# Generated deterministically by seda-macro-lef-normalizer-v1; recipe orfs-ng45-fakeram-metal3-coupledl2-pg-v1.
VERSION 5.8 ;
BUSBITCHARS "[]" ;
DIVIDERCHAR "/" ;

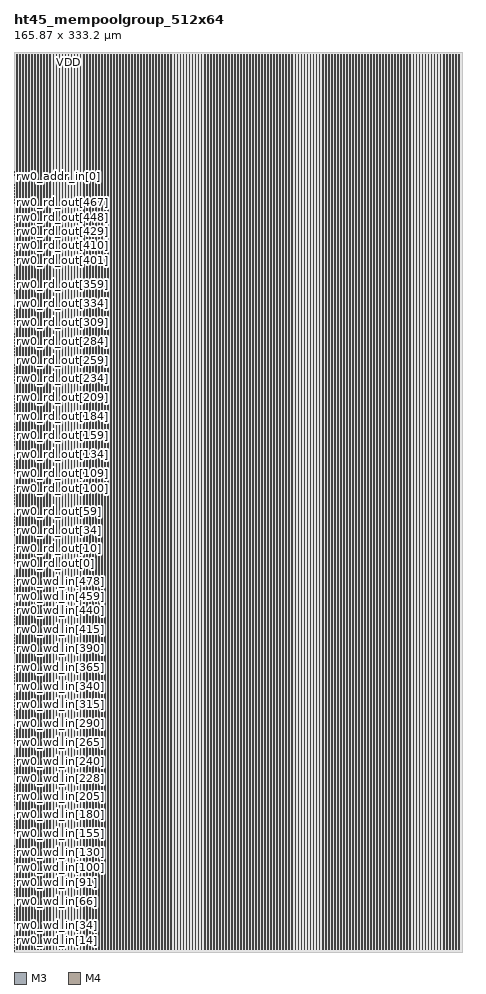
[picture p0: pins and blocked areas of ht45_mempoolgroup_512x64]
MACRO ht45_mempoolgroup_512x64
  FOREIGN ht45_mempoolgroup_512x64 0 0 ;
  CLASS BLOCK ;
  ORIGIN 0 0 ;
  SIZE 165.87 BY 333.2 ;
  SYMMETRY X Y R90 ;
  PIN rw0_wmask_in[0]
    DIRECTION INPUT ;
    USE SIGNAL ;
    SHAPE ABUTMENT ;
    PORT
      LAYER M3 ;
      RECT 0 0.035 0.07 0.105 ;
    END
  END rw0_wmask_in[0]
  PIN rw0_wd_in[0]
    DIRECTION INPUT ;
    USE SIGNAL ;
    SHAPE ABUTMENT ;
    PORT
      LAYER M3 ;
      RECT 0 0.315 0.07 0.385 ;
    END
  END rw0_wd_in[0]
  PIN rw0_wd_in[1]
    DIRECTION INPUT ;
    USE SIGNAL ;
    SHAPE ABUTMENT ;
    PORT
      LAYER M3 ;
      RECT 0 0.595 0.07 0.665 ;
    END
  END rw0_wd_in[1]
  PIN rw0_wd_in[2]
    DIRECTION INPUT ;
    USE SIGNAL ;
    SHAPE ABUTMENT ;
    PORT
      LAYER M3 ;
      RECT 0 0.875 0.07 0.945 ;
    END
  END rw0_wd_in[2]
  PIN rw0_wd_in[3]
    DIRECTION INPUT ;
    USE SIGNAL ;
    SHAPE ABUTMENT ;
    PORT
      LAYER M3 ;
      RECT 0 1.155 0.07 1.225 ;
    END
  END rw0_wd_in[3]
  PIN rw0_wd_in[4]
    DIRECTION INPUT ;
    USE SIGNAL ;
    SHAPE ABUTMENT ;
    PORT
      LAYER M3 ;
      RECT 0 1.435 0.07 1.505 ;
    END
  END rw0_wd_in[4]
  PIN rw0_wd_in[5]
    DIRECTION INPUT ;
    USE SIGNAL ;
    SHAPE ABUTMENT ;
    PORT
      LAYER M3 ;
      RECT 0 1.715 0.07 1.785 ;
    END
  END rw0_wd_in[5]
  PIN rw0_wd_in[6]
    DIRECTION INPUT ;
    USE SIGNAL ;
    SHAPE ABUTMENT ;
    PORT
      LAYER M3 ;
      RECT 0 1.995 0.07 2.065 ;
    END
  END rw0_wd_in[6]
  PIN rw0_wd_in[7]
    DIRECTION INPUT ;
    USE SIGNAL ;
    SHAPE ABUTMENT ;
    PORT
      LAYER M3 ;
      RECT 0 2.275 0.07 2.345 ;
    END
  END rw0_wd_in[7]
  PIN rw0_wd_in[8]
    DIRECTION INPUT ;
    USE SIGNAL ;
    SHAPE ABUTMENT ;
    PORT
      LAYER M3 ;
      RECT 0 2.555 0.07 2.625 ;
    END
  END rw0_wd_in[8]
  PIN rw0_wd_in[9]
    DIRECTION INPUT ;
    USE SIGNAL ;
    SHAPE ABUTMENT ;
    PORT
      LAYER M3 ;
      RECT 0 2.835 0.07 2.905 ;
    END
  END rw0_wd_in[9]
  PIN rw0_wd_in[10]
    DIRECTION INPUT ;
    USE SIGNAL ;
    SHAPE ABUTMENT ;
    PORT
      LAYER M3 ;
      RECT 0 3.115 0.07 3.185 ;
    END
  END rw0_wd_in[10]
  PIN rw0_wd_in[11]
    DIRECTION INPUT ;
    USE SIGNAL ;
    SHAPE ABUTMENT ;
    PORT
      LAYER M3 ;
      RECT 0 3.395 0.07 3.465 ;
    END
  END rw0_wd_in[11]
  PIN rw0_wd_in[12]
    DIRECTION INPUT ;
    USE SIGNAL ;
    SHAPE ABUTMENT ;
    PORT
      LAYER M3 ;
      RECT 0 3.675 0.07 3.745 ;
    END
  END rw0_wd_in[12]
  PIN rw0_wd_in[13]
    DIRECTION INPUT ;
    USE SIGNAL ;
    SHAPE ABUTMENT ;
    PORT
      LAYER M3 ;
      RECT 0 3.955 0.07 4.025 ;
    END
  END rw0_wd_in[13]
  PIN rw0_wd_in[14]
    DIRECTION INPUT ;
    USE SIGNAL ;
    SHAPE ABUTMENT ;
    PORT
      LAYER M3 ;
      RECT 0 4.235 0.07 4.305 ;
    END
  END rw0_wd_in[14]
  PIN rw0_wd_in[15]
    DIRECTION INPUT ;
    USE SIGNAL ;
    SHAPE ABUTMENT ;
    PORT
      LAYER M3 ;
      RECT 0 4.515 0.07 4.585 ;
    END
  END rw0_wd_in[15]
  PIN rw0_wd_in[16]
    DIRECTION INPUT ;
    USE SIGNAL ;
    SHAPE ABUTMENT ;
    PORT
      LAYER M3 ;
      RECT 0 4.795 0.07 4.865 ;
    END
  END rw0_wd_in[16]
  PIN rw0_wd_in[17]
    DIRECTION INPUT ;
    USE SIGNAL ;
    SHAPE ABUTMENT ;
    PORT
      LAYER M3 ;
      RECT 0 5.075 0.07 5.145 ;
    END
  END rw0_wd_in[17]
  PIN rw0_wd_in[18]
    DIRECTION INPUT ;
    USE SIGNAL ;
    SHAPE ABUTMENT ;
    PORT
      LAYER M3 ;
      RECT 0 5.355 0.07 5.425 ;
    END
  END rw0_wd_in[18]
  PIN rw0_wd_in[19]
    DIRECTION INPUT ;
    USE SIGNAL ;
    SHAPE ABUTMENT ;
    PORT
      LAYER M3 ;
      RECT 0 5.635 0.07 5.705 ;
    END
  END rw0_wd_in[19]
  PIN rw0_wd_in[20]
    DIRECTION INPUT ;
    USE SIGNAL ;
    SHAPE ABUTMENT ;
    PORT
      LAYER M3 ;
      RECT 0 5.915 0.07 5.985 ;
    END
  END rw0_wd_in[20]
  PIN rw0_wd_in[21]
    DIRECTION INPUT ;
    USE SIGNAL ;
    SHAPE ABUTMENT ;
    PORT
      LAYER M3 ;
      RECT 0 6.195 0.07 6.265 ;
    END
  END rw0_wd_in[21]
  PIN rw0_wd_in[22]
    DIRECTION INPUT ;
    USE SIGNAL ;
    SHAPE ABUTMENT ;
    PORT
      LAYER M3 ;
      RECT 0 6.475 0.07 6.545 ;
    END
  END rw0_wd_in[22]
  PIN rw0_wd_in[23]
    DIRECTION INPUT ;
    USE SIGNAL ;
    SHAPE ABUTMENT ;
    PORT
      LAYER M3 ;
      RECT 0 6.755 0.07 6.825 ;
    END
  END rw0_wd_in[23]
  PIN rw0_wd_in[24]
    DIRECTION INPUT ;
    USE SIGNAL ;
    SHAPE ABUTMENT ;
    PORT
      LAYER M3 ;
      RECT 0 7.035 0.07 7.105 ;
    END
  END rw0_wd_in[24]
  PIN rw0_wd_in[25]
    DIRECTION INPUT ;
    USE SIGNAL ;
    SHAPE ABUTMENT ;
    PORT
      LAYER M3 ;
      RECT 0 7.315 0.07 7.385 ;
    END
  END rw0_wd_in[25]
  PIN rw0_wd_in[26]
    DIRECTION INPUT ;
    USE SIGNAL ;
    SHAPE ABUTMENT ;
    PORT
      LAYER M3 ;
      RECT 0 7.595 0.07 7.665 ;
    END
  END rw0_wd_in[26]
  PIN rw0_wd_in[27]
    DIRECTION INPUT ;
    USE SIGNAL ;
    SHAPE ABUTMENT ;
    PORT
      LAYER M3 ;
      RECT 0 7.875 0.07 7.945 ;
    END
  END rw0_wd_in[27]
  PIN rw0_wd_in[28]
    DIRECTION INPUT ;
    USE SIGNAL ;
    SHAPE ABUTMENT ;
    PORT
      LAYER M3 ;
      RECT 0 8.155 0.07 8.225 ;
    END
  END rw0_wd_in[28]
  PIN rw0_wd_in[29]
    DIRECTION INPUT ;
    USE SIGNAL ;
    SHAPE ABUTMENT ;
    PORT
      LAYER M3 ;
      RECT 0 8.435 0.07 8.505 ;
    END
  END rw0_wd_in[29]
  PIN rw0_wd_in[30]
    DIRECTION INPUT ;
    USE SIGNAL ;
    SHAPE ABUTMENT ;
    PORT
      LAYER M3 ;
      RECT 0 8.715 0.07 8.785 ;
    END
  END rw0_wd_in[30]
  PIN rw0_wd_in[31]
    DIRECTION INPUT ;
    USE SIGNAL ;
    SHAPE ABUTMENT ;
    PORT
      LAYER M3 ;
      RECT 0 8.995 0.07 9.065 ;
    END
  END rw0_wd_in[31]
  PIN rw0_wd_in[32]
    DIRECTION INPUT ;
    USE SIGNAL ;
    SHAPE ABUTMENT ;
    PORT
      LAYER M3 ;
      RECT 0 9.275 0.07 9.345 ;
    END
  END rw0_wd_in[32]
  PIN rw0_wd_in[33]
    DIRECTION INPUT ;
    USE SIGNAL ;
    SHAPE ABUTMENT ;
    PORT
      LAYER M3 ;
      RECT 0 9.555 0.07 9.625 ;
    END
  END rw0_wd_in[33]
  PIN rw0_wd_in[34]
    DIRECTION INPUT ;
    USE SIGNAL ;
    SHAPE ABUTMENT ;
    PORT
      LAYER M3 ;
      RECT 0 9.835 0.07 9.905 ;
    END
  END rw0_wd_in[34]
  PIN rw0_wd_in[35]
    DIRECTION INPUT ;
    USE SIGNAL ;
    SHAPE ABUTMENT ;
    PORT
      LAYER M3 ;
      RECT 0 10.115 0.07 10.185 ;
    END
  END rw0_wd_in[35]
  PIN rw0_wd_in[36]
    DIRECTION INPUT ;
    USE SIGNAL ;
    SHAPE ABUTMENT ;
    PORT
      LAYER M3 ;
      RECT 0 10.395 0.07 10.465 ;
    END
  END rw0_wd_in[36]
  PIN rw0_wd_in[37]
    DIRECTION INPUT ;
    USE SIGNAL ;
    SHAPE ABUTMENT ;
    PORT
      LAYER M3 ;
      RECT 0 10.675 0.07 10.745 ;
    END
  END rw0_wd_in[37]
  PIN rw0_wd_in[38]
    DIRECTION INPUT ;
    USE SIGNAL ;
    SHAPE ABUTMENT ;
    PORT
      LAYER M3 ;
      RECT 0 10.955 0.07 11.025 ;
    END
  END rw0_wd_in[38]
  PIN rw0_wd_in[39]
    DIRECTION INPUT ;
    USE SIGNAL ;
    SHAPE ABUTMENT ;
    PORT
      LAYER M3 ;
      RECT 0 11.235 0.07 11.305 ;
    END
  END rw0_wd_in[39]
  PIN rw0_wd_in[40]
    DIRECTION INPUT ;
    USE SIGNAL ;
    SHAPE ABUTMENT ;
    PORT
      LAYER M3 ;
      RECT 0 11.515 0.07 11.585 ;
    END
  END rw0_wd_in[40]
  PIN rw0_wd_in[41]
    DIRECTION INPUT ;
    USE SIGNAL ;
    SHAPE ABUTMENT ;
    PORT
      LAYER M3 ;
      RECT 0 11.795 0.07 11.865 ;
    END
  END rw0_wd_in[41]
  PIN rw0_wd_in[42]
    DIRECTION INPUT ;
    USE SIGNAL ;
    SHAPE ABUTMENT ;
    PORT
      LAYER M3 ;
      RECT 0 12.075 0.07 12.145 ;
    END
  END rw0_wd_in[42]
  PIN rw0_wd_in[43]
    DIRECTION INPUT ;
    USE SIGNAL ;
    SHAPE ABUTMENT ;
    PORT
      LAYER M3 ;
      RECT 0 12.355 0.07 12.425 ;
    END
  END rw0_wd_in[43]
  PIN rw0_wd_in[44]
    DIRECTION INPUT ;
    USE SIGNAL ;
    SHAPE ABUTMENT ;
    PORT
      LAYER M3 ;
      RECT 0 12.635 0.07 12.705 ;
    END
  END rw0_wd_in[44]
  PIN rw0_wd_in[45]
    DIRECTION INPUT ;
    USE SIGNAL ;
    SHAPE ABUTMENT ;
    PORT
      LAYER M3 ;
      RECT 0 12.915 0.07 12.985 ;
    END
  END rw0_wd_in[45]
  PIN rw0_wd_in[46]
    DIRECTION INPUT ;
    USE SIGNAL ;
    SHAPE ABUTMENT ;
    PORT
      LAYER M3 ;
      RECT 0 13.195 0.07 13.265 ;
    END
  END rw0_wd_in[46]
  PIN rw0_wd_in[47]
    DIRECTION INPUT ;
    USE SIGNAL ;
    SHAPE ABUTMENT ;
    PORT
      LAYER M3 ;
      RECT 0 13.475 0.07 13.545 ;
    END
  END rw0_wd_in[47]
  PIN rw0_wd_in[48]
    DIRECTION INPUT ;
    USE SIGNAL ;
    SHAPE ABUTMENT ;
    PORT
      LAYER M3 ;
      RECT 0 13.755 0.07 13.825 ;
    END
  END rw0_wd_in[48]
  PIN rw0_wd_in[49]
    DIRECTION INPUT ;
    USE SIGNAL ;
    SHAPE ABUTMENT ;
    PORT
      LAYER M3 ;
      RECT 0 14.035 0.07 14.105 ;
    END
  END rw0_wd_in[49]
  PIN rw0_wd_in[50]
    DIRECTION INPUT ;
    USE SIGNAL ;
    SHAPE ABUTMENT ;
    PORT
      LAYER M3 ;
      RECT 0 14.315 0.07 14.385 ;
    END
  END rw0_wd_in[50]
  PIN rw0_wd_in[51]
    DIRECTION INPUT ;
    USE SIGNAL ;
    SHAPE ABUTMENT ;
    PORT
      LAYER M3 ;
      RECT 0 14.595 0.07 14.665 ;
    END
  END rw0_wd_in[51]
  PIN rw0_wd_in[52]
    DIRECTION INPUT ;
    USE SIGNAL ;
    SHAPE ABUTMENT ;
    PORT
      LAYER M3 ;
      RECT 0 14.875 0.07 14.945 ;
    END
  END rw0_wd_in[52]
  PIN rw0_wd_in[53]
    DIRECTION INPUT ;
    USE SIGNAL ;
    SHAPE ABUTMENT ;
    PORT
      LAYER M3 ;
      RECT 0 15.155 0.07 15.225 ;
    END
  END rw0_wd_in[53]
  PIN rw0_wd_in[54]
    DIRECTION INPUT ;
    USE SIGNAL ;
    SHAPE ABUTMENT ;
    PORT
      LAYER M3 ;
      RECT 0 15.435 0.07 15.505 ;
    END
  END rw0_wd_in[54]
  PIN rw0_wd_in[55]
    DIRECTION INPUT ;
    USE SIGNAL ;
    SHAPE ABUTMENT ;
    PORT
      LAYER M3 ;
      RECT 0 15.715 0.07 15.785 ;
    END
  END rw0_wd_in[55]
  PIN rw0_wd_in[56]
    DIRECTION INPUT ;
    USE SIGNAL ;
    SHAPE ABUTMENT ;
    PORT
      LAYER M3 ;
      RECT 0 15.995 0.07 16.065 ;
    END
  END rw0_wd_in[56]
  PIN rw0_wd_in[57]
    DIRECTION INPUT ;
    USE SIGNAL ;
    SHAPE ABUTMENT ;
    PORT
      LAYER M3 ;
      RECT 0 16.275 0.07 16.345 ;
    END
  END rw0_wd_in[57]
  PIN rw0_wd_in[58]
    DIRECTION INPUT ;
    USE SIGNAL ;
    SHAPE ABUTMENT ;
    PORT
      LAYER M3 ;
      RECT 0 16.555 0.07 16.625 ;
    END
  END rw0_wd_in[58]
  PIN rw0_wd_in[59]
    DIRECTION INPUT ;
    USE SIGNAL ;
    SHAPE ABUTMENT ;
    PORT
      LAYER M3 ;
      RECT 0 16.835 0.07 16.905 ;
    END
  END rw0_wd_in[59]
  PIN rw0_wd_in[60]
    DIRECTION INPUT ;
    USE SIGNAL ;
    SHAPE ABUTMENT ;
    PORT
      LAYER M3 ;
      RECT 0 17.115 0.07 17.185 ;
    END
  END rw0_wd_in[60]
  PIN rw0_wd_in[61]
    DIRECTION INPUT ;
    USE SIGNAL ;
    SHAPE ABUTMENT ;
    PORT
      LAYER M3 ;
      RECT 0 17.395 0.07 17.465 ;
    END
  END rw0_wd_in[61]
  PIN rw0_wd_in[62]
    DIRECTION INPUT ;
    USE SIGNAL ;
    SHAPE ABUTMENT ;
    PORT
      LAYER M3 ;
      RECT 0 17.675 0.07 17.745 ;
    END
  END rw0_wd_in[62]
  PIN rw0_wd_in[63]
    DIRECTION INPUT ;
    USE SIGNAL ;
    SHAPE ABUTMENT ;
    PORT
      LAYER M3 ;
      RECT 0 17.955 0.07 18.025 ;
    END
  END rw0_wd_in[63]
  PIN rw0_wd_in[64]
    DIRECTION INPUT ;
    USE SIGNAL ;
    SHAPE ABUTMENT ;
    PORT
      LAYER M3 ;
      RECT 0 18.235 0.07 18.305 ;
    END
  END rw0_wd_in[64]
  PIN rw0_wd_in[65]
    DIRECTION INPUT ;
    USE SIGNAL ;
    SHAPE ABUTMENT ;
    PORT
      LAYER M3 ;
      RECT 0 18.515 0.07 18.585 ;
    END
  END rw0_wd_in[65]
  PIN rw0_wd_in[66]
    DIRECTION INPUT ;
    USE SIGNAL ;
    SHAPE ABUTMENT ;
    PORT
      LAYER M3 ;
      RECT 0 18.795 0.07 18.865 ;
    END
  END rw0_wd_in[66]
  PIN rw0_wd_in[67]
    DIRECTION INPUT ;
    USE SIGNAL ;
    SHAPE ABUTMENT ;
    PORT
      LAYER M3 ;
      RECT 0 19.075 0.07 19.145 ;
    END
  END rw0_wd_in[67]
  PIN rw0_wd_in[68]
    DIRECTION INPUT ;
    USE SIGNAL ;
    SHAPE ABUTMENT ;
    PORT
      LAYER M3 ;
      RECT 0 19.355 0.07 19.425 ;
    END
  END rw0_wd_in[68]
  PIN rw0_wd_in[69]
    DIRECTION INPUT ;
    USE SIGNAL ;
    SHAPE ABUTMENT ;
    PORT
      LAYER M3 ;
      RECT 0 19.635 0.07 19.705 ;
    END
  END rw0_wd_in[69]
  PIN rw0_wd_in[70]
    DIRECTION INPUT ;
    USE SIGNAL ;
    SHAPE ABUTMENT ;
    PORT
      LAYER M3 ;
      RECT 0 19.915 0.07 19.985 ;
    END
  END rw0_wd_in[70]
  PIN rw0_wd_in[71]
    DIRECTION INPUT ;
    USE SIGNAL ;
    SHAPE ABUTMENT ;
    PORT
      LAYER M3 ;
      RECT 0 20.195 0.07 20.265 ;
    END
  END rw0_wd_in[71]
  PIN rw0_wd_in[72]
    DIRECTION INPUT ;
    USE SIGNAL ;
    SHAPE ABUTMENT ;
    PORT
      LAYER M3 ;
      RECT 0 20.475 0.07 20.545 ;
    END
  END rw0_wd_in[72]
  PIN rw0_wd_in[73]
    DIRECTION INPUT ;
    USE SIGNAL ;
    SHAPE ABUTMENT ;
    PORT
      LAYER M3 ;
      RECT 0 20.755 0.07 20.825 ;
    END
  END rw0_wd_in[73]
  PIN rw0_wd_in[74]
    DIRECTION INPUT ;
    USE SIGNAL ;
    SHAPE ABUTMENT ;
    PORT
      LAYER M3 ;
      RECT 0 21.035 0.07 21.105 ;
    END
  END rw0_wd_in[74]
  PIN rw0_wd_in[75]
    DIRECTION INPUT ;
    USE SIGNAL ;
    SHAPE ABUTMENT ;
    PORT
      LAYER M3 ;
      RECT 0 21.315 0.07 21.385 ;
    END
  END rw0_wd_in[75]
  PIN rw0_wd_in[76]
    DIRECTION INPUT ;
    USE SIGNAL ;
    SHAPE ABUTMENT ;
    PORT
      LAYER M3 ;
      RECT 0 21.595 0.07 21.665 ;
    END
  END rw0_wd_in[76]
  PIN rw0_wd_in[77]
    DIRECTION INPUT ;
    USE SIGNAL ;
    SHAPE ABUTMENT ;
    PORT
      LAYER M3 ;
      RECT 0 21.875 0.07 21.945 ;
    END
  END rw0_wd_in[77]
  PIN rw0_wd_in[78]
    DIRECTION INPUT ;
    USE SIGNAL ;
    SHAPE ABUTMENT ;
    PORT
      LAYER M3 ;
      RECT 0 22.155 0.07 22.225 ;
    END
  END rw0_wd_in[78]
  PIN rw0_wd_in[79]
    DIRECTION INPUT ;
    USE SIGNAL ;
    SHAPE ABUTMENT ;
    PORT
      LAYER M3 ;
      RECT 0 22.435 0.07 22.505 ;
    END
  END rw0_wd_in[79]
  PIN rw0_wd_in[80]
    DIRECTION INPUT ;
    USE SIGNAL ;
    SHAPE ABUTMENT ;
    PORT
      LAYER M3 ;
      RECT 0 22.715 0.07 22.785 ;
    END
  END rw0_wd_in[80]
  PIN rw0_wd_in[81]
    DIRECTION INPUT ;
    USE SIGNAL ;
    SHAPE ABUTMENT ;
    PORT
      LAYER M3 ;
      RECT 0 22.995 0.07 23.065 ;
    END
  END rw0_wd_in[81]
  PIN rw0_wd_in[82]
    DIRECTION INPUT ;
    USE SIGNAL ;
    SHAPE ABUTMENT ;
    PORT
      LAYER M3 ;
      RECT 0 23.275 0.07 23.345 ;
    END
  END rw0_wd_in[82]
  PIN rw0_wd_in[83]
    DIRECTION INPUT ;
    USE SIGNAL ;
    SHAPE ABUTMENT ;
    PORT
      LAYER M3 ;
      RECT 0 23.555 0.07 23.625 ;
    END
  END rw0_wd_in[83]
  PIN rw0_wd_in[84]
    DIRECTION INPUT ;
    USE SIGNAL ;
    SHAPE ABUTMENT ;
    PORT
      LAYER M3 ;
      RECT 0 23.835 0.07 23.905 ;
    END
  END rw0_wd_in[84]
  PIN rw0_wd_in[85]
    DIRECTION INPUT ;
    USE SIGNAL ;
    SHAPE ABUTMENT ;
    PORT
      LAYER M3 ;
      RECT 0 24.115 0.07 24.185 ;
    END
  END rw0_wd_in[85]
  PIN rw0_wd_in[86]
    DIRECTION INPUT ;
    USE SIGNAL ;
    SHAPE ABUTMENT ;
    PORT
      LAYER M3 ;
      RECT 0 24.395 0.07 24.465 ;
    END
  END rw0_wd_in[86]
  PIN rw0_wd_in[87]
    DIRECTION INPUT ;
    USE SIGNAL ;
    SHAPE ABUTMENT ;
    PORT
      LAYER M3 ;
      RECT 0 24.675 0.07 24.745 ;
    END
  END rw0_wd_in[87]
  PIN rw0_wd_in[88]
    DIRECTION INPUT ;
    USE SIGNAL ;
    SHAPE ABUTMENT ;
    PORT
      LAYER M3 ;
      RECT 0 24.955 0.07 25.025 ;
    END
  END rw0_wd_in[88]
  PIN rw0_wd_in[89]
    DIRECTION INPUT ;
    USE SIGNAL ;
    SHAPE ABUTMENT ;
    PORT
      LAYER M3 ;
      RECT 0 25.235 0.07 25.305 ;
    END
  END rw0_wd_in[89]
  PIN rw0_wd_in[90]
    DIRECTION INPUT ;
    USE SIGNAL ;
    SHAPE ABUTMENT ;
    PORT
      LAYER M3 ;
      RECT 0 25.515 0.07 25.585 ;
    END
  END rw0_wd_in[90]
  PIN rw0_wd_in[91]
    DIRECTION INPUT ;
    USE SIGNAL ;
    SHAPE ABUTMENT ;
    PORT
      LAYER M3 ;
      RECT 0 25.795 0.07 25.865 ;
    END
  END rw0_wd_in[91]
  PIN rw0_wd_in[92]
    DIRECTION INPUT ;
    USE SIGNAL ;
    SHAPE ABUTMENT ;
    PORT
      LAYER M3 ;
      RECT 0 26.075 0.07 26.145 ;
    END
  END rw0_wd_in[92]
  PIN rw0_wd_in[93]
    DIRECTION INPUT ;
    USE SIGNAL ;
    SHAPE ABUTMENT ;
    PORT
      LAYER M3 ;
      RECT 0 26.355 0.07 26.425 ;
    END
  END rw0_wd_in[93]
  PIN rw0_wd_in[94]
    DIRECTION INPUT ;
    USE SIGNAL ;
    SHAPE ABUTMENT ;
    PORT
      LAYER M3 ;
      RECT 0 26.635 0.07 26.705 ;
    END
  END rw0_wd_in[94]
  PIN rw0_wd_in[95]
    DIRECTION INPUT ;
    USE SIGNAL ;
    SHAPE ABUTMENT ;
    PORT
      LAYER M3 ;
      RECT 0 26.915 0.07 26.985 ;
    END
  END rw0_wd_in[95]
  PIN rw0_wd_in[96]
    DIRECTION INPUT ;
    USE SIGNAL ;
    SHAPE ABUTMENT ;
    PORT
      LAYER M3 ;
      RECT 0 27.195 0.07 27.265 ;
    END
  END rw0_wd_in[96]
  PIN rw0_wd_in[97]
    DIRECTION INPUT ;
    USE SIGNAL ;
    SHAPE ABUTMENT ;
    PORT
      LAYER M3 ;
      RECT 0 27.475 0.07 27.545 ;
    END
  END rw0_wd_in[97]
  PIN rw0_wd_in[98]
    DIRECTION INPUT ;
    USE SIGNAL ;
    SHAPE ABUTMENT ;
    PORT
      LAYER M3 ;
      RECT 0 27.755 0.07 27.825 ;
    END
  END rw0_wd_in[98]
  PIN rw0_wd_in[99]
    DIRECTION INPUT ;
    USE SIGNAL ;
    SHAPE ABUTMENT ;
    PORT
      LAYER M3 ;
      RECT 0 28.035 0.07 28.105 ;
    END
  END rw0_wd_in[99]
  PIN rw0_wd_in[100]
    DIRECTION INPUT ;
    USE SIGNAL ;
    SHAPE ABUTMENT ;
    PORT
      LAYER M3 ;
      RECT 0 28.315 0.07 28.385 ;
    END
  END rw0_wd_in[100]
  PIN rw0_wd_in[101]
    DIRECTION INPUT ;
    USE SIGNAL ;
    SHAPE ABUTMENT ;
    PORT
      LAYER M3 ;
      RECT 0 28.595 0.07 28.665 ;
    END
  END rw0_wd_in[101]
  PIN rw0_wd_in[102]
    DIRECTION INPUT ;
    USE SIGNAL ;
    SHAPE ABUTMENT ;
    PORT
      LAYER M3 ;
      RECT 0 28.875 0.07 28.945 ;
    END
  END rw0_wd_in[102]
  PIN rw0_wd_in[103]
    DIRECTION INPUT ;
    USE SIGNAL ;
    SHAPE ABUTMENT ;
    PORT
      LAYER M3 ;
      RECT 0 29.155 0.07 29.225 ;
    END
  END rw0_wd_in[103]
  PIN rw0_wd_in[104]
    DIRECTION INPUT ;
    USE SIGNAL ;
    SHAPE ABUTMENT ;
    PORT
      LAYER M3 ;
      RECT 0 29.435 0.07 29.505 ;
    END
  END rw0_wd_in[104]
  PIN rw0_wd_in[105]
    DIRECTION INPUT ;
    USE SIGNAL ;
    SHAPE ABUTMENT ;
    PORT
      LAYER M3 ;
      RECT 0 29.715 0.07 29.785 ;
    END
  END rw0_wd_in[105]
  PIN rw0_wd_in[106]
    DIRECTION INPUT ;
    USE SIGNAL ;
    SHAPE ABUTMENT ;
    PORT
      LAYER M3 ;
      RECT 0 29.995 0.07 30.065 ;
    END
  END rw0_wd_in[106]
  PIN rw0_wd_in[107]
    DIRECTION INPUT ;
    USE SIGNAL ;
    SHAPE ABUTMENT ;
    PORT
      LAYER M3 ;
      RECT 0 30.275 0.07 30.345 ;
    END
  END rw0_wd_in[107]
  PIN rw0_wd_in[108]
    DIRECTION INPUT ;
    USE SIGNAL ;
    SHAPE ABUTMENT ;
    PORT
      LAYER M3 ;
      RECT 0 30.555 0.07 30.625 ;
    END
  END rw0_wd_in[108]
  PIN rw0_wd_in[109]
    DIRECTION INPUT ;
    USE SIGNAL ;
    SHAPE ABUTMENT ;
    PORT
      LAYER M3 ;
      RECT 0 30.835 0.07 30.905 ;
    END
  END rw0_wd_in[109]
  PIN rw0_wd_in[110]
    DIRECTION INPUT ;
    USE SIGNAL ;
    SHAPE ABUTMENT ;
    PORT
      LAYER M3 ;
      RECT 0 31.115 0.07 31.185 ;
    END
  END rw0_wd_in[110]
  PIN rw0_wd_in[111]
    DIRECTION INPUT ;
    USE SIGNAL ;
    SHAPE ABUTMENT ;
    PORT
      LAYER M3 ;
      RECT 0 31.395 0.07 31.465 ;
    END
  END rw0_wd_in[111]
  PIN rw0_wd_in[112]
    DIRECTION INPUT ;
    USE SIGNAL ;
    SHAPE ABUTMENT ;
    PORT
      LAYER M3 ;
      RECT 0 31.675 0.07 31.745 ;
    END
  END rw0_wd_in[112]
  PIN rw0_wd_in[113]
    DIRECTION INPUT ;
    USE SIGNAL ;
    SHAPE ABUTMENT ;
    PORT
      LAYER M3 ;
      RECT 0 31.955 0.07 32.025 ;
    END
  END rw0_wd_in[113]
  PIN rw0_wd_in[114]
    DIRECTION INPUT ;
    USE SIGNAL ;
    SHAPE ABUTMENT ;
    PORT
      LAYER M3 ;
      RECT 0 32.235 0.07 32.305 ;
    END
  END rw0_wd_in[114]
  PIN rw0_wd_in[115]
    DIRECTION INPUT ;
    USE SIGNAL ;
    SHAPE ABUTMENT ;
    PORT
      LAYER M3 ;
      RECT 0 32.515 0.07 32.585 ;
    END
  END rw0_wd_in[115]
  PIN rw0_wd_in[116]
    DIRECTION INPUT ;
    USE SIGNAL ;
    SHAPE ABUTMENT ;
    PORT
      LAYER M3 ;
      RECT 0 32.795 0.07 32.865 ;
    END
  END rw0_wd_in[116]
  PIN rw0_wd_in[117]
    DIRECTION INPUT ;
    USE SIGNAL ;
    SHAPE ABUTMENT ;
    PORT
      LAYER M3 ;
      RECT 0 33.075 0.07 33.145 ;
    END
  END rw0_wd_in[117]
  PIN rw0_wd_in[118]
    DIRECTION INPUT ;
    USE SIGNAL ;
    SHAPE ABUTMENT ;
    PORT
      LAYER M3 ;
      RECT 0 33.355 0.07 33.425 ;
    END
  END rw0_wd_in[118]
  PIN rw0_wd_in[119]
    DIRECTION INPUT ;
    USE SIGNAL ;
    SHAPE ABUTMENT ;
    PORT
      LAYER M3 ;
      RECT 0 33.635 0.07 33.705 ;
    END
  END rw0_wd_in[119]
  PIN rw0_wd_in[120]
    DIRECTION INPUT ;
    USE SIGNAL ;
    SHAPE ABUTMENT ;
    PORT
      LAYER M3 ;
      RECT 0 33.915 0.07 33.985 ;
    END
  END rw0_wd_in[120]
  PIN rw0_wd_in[121]
    DIRECTION INPUT ;
    USE SIGNAL ;
    SHAPE ABUTMENT ;
    PORT
      LAYER M3 ;
      RECT 0 34.195 0.07 34.265 ;
    END
  END rw0_wd_in[121]
  PIN rw0_wd_in[122]
    DIRECTION INPUT ;
    USE SIGNAL ;
    SHAPE ABUTMENT ;
    PORT
      LAYER M3 ;
      RECT 0 34.475 0.07 34.545 ;
    END
  END rw0_wd_in[122]
  PIN rw0_wd_in[123]
    DIRECTION INPUT ;
    USE SIGNAL ;
    SHAPE ABUTMENT ;
    PORT
      LAYER M3 ;
      RECT 0 34.755 0.07 34.825 ;
    END
  END rw0_wd_in[123]
  PIN rw0_wd_in[124]
    DIRECTION INPUT ;
    USE SIGNAL ;
    SHAPE ABUTMENT ;
    PORT
      LAYER M3 ;
      RECT 0 35.035 0.07 35.105 ;
    END
  END rw0_wd_in[124]
  PIN rw0_wd_in[125]
    DIRECTION INPUT ;
    USE SIGNAL ;
    SHAPE ABUTMENT ;
    PORT
      LAYER M3 ;
      RECT 0 35.315 0.07 35.385 ;
    END
  END rw0_wd_in[125]
  PIN rw0_wd_in[126]
    DIRECTION INPUT ;
    USE SIGNAL ;
    SHAPE ABUTMENT ;
    PORT
      LAYER M3 ;
      RECT 0 35.595 0.07 35.665 ;
    END
  END rw0_wd_in[126]
  PIN rw0_wd_in[127]
    DIRECTION INPUT ;
    USE SIGNAL ;
    SHAPE ABUTMENT ;
    PORT
      LAYER M3 ;
      RECT 0 35.875 0.07 35.945 ;
    END
  END rw0_wd_in[127]
  PIN rw0_wd_in[128]
    DIRECTION INPUT ;
    USE SIGNAL ;
    SHAPE ABUTMENT ;
    PORT
      LAYER M3 ;
      RECT 0 36.155 0.07 36.225 ;
    END
  END rw0_wd_in[128]
  PIN rw0_wd_in[129]
    DIRECTION INPUT ;
    USE SIGNAL ;
    SHAPE ABUTMENT ;
    PORT
      LAYER M3 ;
      RECT 0 36.435 0.07 36.505 ;
    END
  END rw0_wd_in[129]
  PIN rw0_wd_in[130]
    DIRECTION INPUT ;
    USE SIGNAL ;
    SHAPE ABUTMENT ;
    PORT
      LAYER M3 ;
      RECT 0 36.715 0.07 36.785 ;
    END
  END rw0_wd_in[130]
  PIN rw0_wd_in[131]
    DIRECTION INPUT ;
    USE SIGNAL ;
    SHAPE ABUTMENT ;
    PORT
      LAYER M3 ;
      RECT 0 36.995 0.07 37.065 ;
    END
  END rw0_wd_in[131]
  PIN rw0_wd_in[132]
    DIRECTION INPUT ;
    USE SIGNAL ;
    SHAPE ABUTMENT ;
    PORT
      LAYER M3 ;
      RECT 0 37.275 0.07 37.345 ;
    END
  END rw0_wd_in[132]
  PIN rw0_wd_in[133]
    DIRECTION INPUT ;
    USE SIGNAL ;
    SHAPE ABUTMENT ;
    PORT
      LAYER M3 ;
      RECT 0 37.555 0.07 37.625 ;
    END
  END rw0_wd_in[133]
  PIN rw0_wd_in[134]
    DIRECTION INPUT ;
    USE SIGNAL ;
    SHAPE ABUTMENT ;
    PORT
      LAYER M3 ;
      RECT 0 37.835 0.07 37.905 ;
    END
  END rw0_wd_in[134]
  PIN rw0_wd_in[135]
    DIRECTION INPUT ;
    USE SIGNAL ;
    SHAPE ABUTMENT ;
    PORT
      LAYER M3 ;
      RECT 0 38.115 0.07 38.185 ;
    END
  END rw0_wd_in[135]
  PIN rw0_wd_in[136]
    DIRECTION INPUT ;
    USE SIGNAL ;
    SHAPE ABUTMENT ;
    PORT
      LAYER M3 ;
      RECT 0 38.395 0.07 38.465 ;
    END
  END rw0_wd_in[136]
  PIN rw0_wd_in[137]
    DIRECTION INPUT ;
    USE SIGNAL ;
    SHAPE ABUTMENT ;
    PORT
      LAYER M3 ;
      RECT 0 38.675 0.07 38.745 ;
    END
  END rw0_wd_in[137]
  PIN rw0_wd_in[138]
    DIRECTION INPUT ;
    USE SIGNAL ;
    SHAPE ABUTMENT ;
    PORT
      LAYER M3 ;
      RECT 0 38.955 0.07 39.025 ;
    END
  END rw0_wd_in[138]
  PIN rw0_wd_in[139]
    DIRECTION INPUT ;
    USE SIGNAL ;
    SHAPE ABUTMENT ;
    PORT
      LAYER M3 ;
      RECT 0 39.235 0.07 39.305 ;
    END
  END rw0_wd_in[139]
  PIN rw0_wd_in[140]
    DIRECTION INPUT ;
    USE SIGNAL ;
    SHAPE ABUTMENT ;
    PORT
      LAYER M3 ;
      RECT 0 39.515 0.07 39.585 ;
    END
  END rw0_wd_in[140]
  PIN rw0_wd_in[141]
    DIRECTION INPUT ;
    USE SIGNAL ;
    SHAPE ABUTMENT ;
    PORT
      LAYER M3 ;
      RECT 0 39.795 0.07 39.865 ;
    END
  END rw0_wd_in[141]
  PIN rw0_wd_in[142]
    DIRECTION INPUT ;
    USE SIGNAL ;
    SHAPE ABUTMENT ;
    PORT
      LAYER M3 ;
      RECT 0 40.075 0.07 40.145 ;
    END
  END rw0_wd_in[142]
  PIN rw0_wd_in[143]
    DIRECTION INPUT ;
    USE SIGNAL ;
    SHAPE ABUTMENT ;
    PORT
      LAYER M3 ;
      RECT 0 40.355 0.07 40.425 ;
    END
  END rw0_wd_in[143]
  PIN rw0_wd_in[144]
    DIRECTION INPUT ;
    USE SIGNAL ;
    SHAPE ABUTMENT ;
    PORT
      LAYER M3 ;
      RECT 0 40.635 0.07 40.705 ;
    END
  END rw0_wd_in[144]
  PIN rw0_wd_in[145]
    DIRECTION INPUT ;
    USE SIGNAL ;
    SHAPE ABUTMENT ;
    PORT
      LAYER M3 ;
      RECT 0 40.915 0.07 40.985 ;
    END
  END rw0_wd_in[145]
  PIN rw0_wd_in[146]
    DIRECTION INPUT ;
    USE SIGNAL ;
    SHAPE ABUTMENT ;
    PORT
      LAYER M3 ;
      RECT 0 41.195 0.07 41.265 ;
    END
  END rw0_wd_in[146]
  PIN rw0_wd_in[147]
    DIRECTION INPUT ;
    USE SIGNAL ;
    SHAPE ABUTMENT ;
    PORT
      LAYER M3 ;
      RECT 0 41.475 0.07 41.545 ;
    END
  END rw0_wd_in[147]
  PIN rw0_wd_in[148]
    DIRECTION INPUT ;
    USE SIGNAL ;
    SHAPE ABUTMENT ;
    PORT
      LAYER M3 ;
      RECT 0 41.755 0.07 41.825 ;
    END
  END rw0_wd_in[148]
  PIN rw0_wd_in[149]
    DIRECTION INPUT ;
    USE SIGNAL ;
    SHAPE ABUTMENT ;
    PORT
      LAYER M3 ;
      RECT 0 42.035 0.07 42.105 ;
    END
  END rw0_wd_in[149]
  PIN rw0_wd_in[150]
    DIRECTION INPUT ;
    USE SIGNAL ;
    SHAPE ABUTMENT ;
    PORT
      LAYER M3 ;
      RECT 0 42.315 0.07 42.385 ;
    END
  END rw0_wd_in[150]
  PIN rw0_wd_in[151]
    DIRECTION INPUT ;
    USE SIGNAL ;
    SHAPE ABUTMENT ;
    PORT
      LAYER M3 ;
      RECT 0 42.595 0.07 42.665 ;
    END
  END rw0_wd_in[151]
  PIN rw0_wd_in[152]
    DIRECTION INPUT ;
    USE SIGNAL ;
    SHAPE ABUTMENT ;
    PORT
      LAYER M3 ;
      RECT 0 42.875 0.07 42.945 ;
    END
  END rw0_wd_in[152]
  PIN rw0_wd_in[153]
    DIRECTION INPUT ;
    USE SIGNAL ;
    SHAPE ABUTMENT ;
    PORT
      LAYER M3 ;
      RECT 0 43.155 0.07 43.225 ;
    END
  END rw0_wd_in[153]
  PIN rw0_wd_in[154]
    DIRECTION INPUT ;
    USE SIGNAL ;
    SHAPE ABUTMENT ;
    PORT
      LAYER M3 ;
      RECT 0 43.435 0.07 43.505 ;
    END
  END rw0_wd_in[154]
  PIN rw0_wd_in[155]
    DIRECTION INPUT ;
    USE SIGNAL ;
    SHAPE ABUTMENT ;
    PORT
      LAYER M3 ;
      RECT 0 43.715 0.07 43.785 ;
    END
  END rw0_wd_in[155]
  PIN rw0_wd_in[156]
    DIRECTION INPUT ;
    USE SIGNAL ;
    SHAPE ABUTMENT ;
    PORT
      LAYER M3 ;
      RECT 0 43.995 0.07 44.065 ;
    END
  END rw0_wd_in[156]
  PIN rw0_wd_in[157]
    DIRECTION INPUT ;
    USE SIGNAL ;
    SHAPE ABUTMENT ;
    PORT
      LAYER M3 ;
      RECT 0 44.275 0.07 44.345 ;
    END
  END rw0_wd_in[157]
  PIN rw0_wd_in[158]
    DIRECTION INPUT ;
    USE SIGNAL ;
    SHAPE ABUTMENT ;
    PORT
      LAYER M3 ;
      RECT 0 44.555 0.07 44.625 ;
    END
  END rw0_wd_in[158]
  PIN rw0_wd_in[159]
    DIRECTION INPUT ;
    USE SIGNAL ;
    SHAPE ABUTMENT ;
    PORT
      LAYER M3 ;
      RECT 0 44.835 0.07 44.905 ;
    END
  END rw0_wd_in[159]
  PIN rw0_wd_in[160]
    DIRECTION INPUT ;
    USE SIGNAL ;
    SHAPE ABUTMENT ;
    PORT
      LAYER M3 ;
      RECT 0 45.115 0.07 45.185 ;
    END
  END rw0_wd_in[160]
  PIN rw0_wd_in[161]
    DIRECTION INPUT ;
    USE SIGNAL ;
    SHAPE ABUTMENT ;
    PORT
      LAYER M3 ;
      RECT 0 45.395 0.07 45.465 ;
    END
  END rw0_wd_in[161]
  PIN rw0_wd_in[162]
    DIRECTION INPUT ;
    USE SIGNAL ;
    SHAPE ABUTMENT ;
    PORT
      LAYER M3 ;
      RECT 0 45.675 0.07 45.745 ;
    END
  END rw0_wd_in[162]
  PIN rw0_wd_in[163]
    DIRECTION INPUT ;
    USE SIGNAL ;
    SHAPE ABUTMENT ;
    PORT
      LAYER M3 ;
      RECT 0 45.955 0.07 46.025 ;
    END
  END rw0_wd_in[163]
  PIN rw0_wd_in[164]
    DIRECTION INPUT ;
    USE SIGNAL ;
    SHAPE ABUTMENT ;
    PORT
      LAYER M3 ;
      RECT 0 46.235 0.07 46.305 ;
    END
  END rw0_wd_in[164]
  PIN rw0_wd_in[165]
    DIRECTION INPUT ;
    USE SIGNAL ;
    SHAPE ABUTMENT ;
    PORT
      LAYER M3 ;
      RECT 0 46.515 0.07 46.585 ;
    END
  END rw0_wd_in[165]
  PIN rw0_wd_in[166]
    DIRECTION INPUT ;
    USE SIGNAL ;
    SHAPE ABUTMENT ;
    PORT
      LAYER M3 ;
      RECT 0 46.795 0.07 46.865 ;
    END
  END rw0_wd_in[166]
  PIN rw0_wd_in[167]
    DIRECTION INPUT ;
    USE SIGNAL ;
    SHAPE ABUTMENT ;
    PORT
      LAYER M3 ;
      RECT 0 47.075 0.07 47.145 ;
    END
  END rw0_wd_in[167]
  PIN rw0_wd_in[168]
    DIRECTION INPUT ;
    USE SIGNAL ;
    SHAPE ABUTMENT ;
    PORT
      LAYER M3 ;
      RECT 0 47.355 0.07 47.425 ;
    END
  END rw0_wd_in[168]
  PIN rw0_wd_in[169]
    DIRECTION INPUT ;
    USE SIGNAL ;
    SHAPE ABUTMENT ;
    PORT
      LAYER M3 ;
      RECT 0 47.635 0.07 47.705 ;
    END
  END rw0_wd_in[169]
  PIN rw0_wd_in[170]
    DIRECTION INPUT ;
    USE SIGNAL ;
    SHAPE ABUTMENT ;
    PORT
      LAYER M3 ;
      RECT 0 47.915 0.07 47.985 ;
    END
  END rw0_wd_in[170]
  PIN rw0_wd_in[171]
    DIRECTION INPUT ;
    USE SIGNAL ;
    SHAPE ABUTMENT ;
    PORT
      LAYER M3 ;
      RECT 0 48.195 0.07 48.265 ;
    END
  END rw0_wd_in[171]
  PIN rw0_wd_in[172]
    DIRECTION INPUT ;
    USE SIGNAL ;
    SHAPE ABUTMENT ;
    PORT
      LAYER M3 ;
      RECT 0 48.475 0.07 48.545 ;
    END
  END rw0_wd_in[172]
  PIN rw0_wd_in[173]
    DIRECTION INPUT ;
    USE SIGNAL ;
    SHAPE ABUTMENT ;
    PORT
      LAYER M3 ;
      RECT 0 48.755 0.07 48.825 ;
    END
  END rw0_wd_in[173]
  PIN rw0_wd_in[174]
    DIRECTION INPUT ;
    USE SIGNAL ;
    SHAPE ABUTMENT ;
    PORT
      LAYER M3 ;
      RECT 0 49.035 0.07 49.105 ;
    END
  END rw0_wd_in[174]
  PIN rw0_wd_in[175]
    DIRECTION INPUT ;
    USE SIGNAL ;
    SHAPE ABUTMENT ;
    PORT
      LAYER M3 ;
      RECT 0 49.315 0.07 49.385 ;
    END
  END rw0_wd_in[175]
  PIN rw0_wd_in[176]
    DIRECTION INPUT ;
    USE SIGNAL ;
    SHAPE ABUTMENT ;
    PORT
      LAYER M3 ;
      RECT 0 49.595 0.07 49.665 ;
    END
  END rw0_wd_in[176]
  PIN rw0_wd_in[177]
    DIRECTION INPUT ;
    USE SIGNAL ;
    SHAPE ABUTMENT ;
    PORT
      LAYER M3 ;
      RECT 0 49.875 0.07 49.945 ;
    END
  END rw0_wd_in[177]
  PIN rw0_wd_in[178]
    DIRECTION INPUT ;
    USE SIGNAL ;
    SHAPE ABUTMENT ;
    PORT
      LAYER M3 ;
      RECT 0 50.155 0.07 50.225 ;
    END
  END rw0_wd_in[178]
  PIN rw0_wd_in[179]
    DIRECTION INPUT ;
    USE SIGNAL ;
    SHAPE ABUTMENT ;
    PORT
      LAYER M3 ;
      RECT 0 50.435 0.07 50.505 ;
    END
  END rw0_wd_in[179]
  PIN rw0_wd_in[180]
    DIRECTION INPUT ;
    USE SIGNAL ;
    SHAPE ABUTMENT ;
    PORT
      LAYER M3 ;
      RECT 0 50.715 0.07 50.785 ;
    END
  END rw0_wd_in[180]
  PIN rw0_wd_in[181]
    DIRECTION INPUT ;
    USE SIGNAL ;
    SHAPE ABUTMENT ;
    PORT
      LAYER M3 ;
      RECT 0 50.995 0.07 51.065 ;
    END
  END rw0_wd_in[181]
  PIN rw0_wd_in[182]
    DIRECTION INPUT ;
    USE SIGNAL ;
    SHAPE ABUTMENT ;
    PORT
      LAYER M3 ;
      RECT 0 51.275 0.07 51.345 ;
    END
  END rw0_wd_in[182]
  PIN rw0_wd_in[183]
    DIRECTION INPUT ;
    USE SIGNAL ;
    SHAPE ABUTMENT ;
    PORT
      LAYER M3 ;
      RECT 0 51.555 0.07 51.625 ;
    END
  END rw0_wd_in[183]
  PIN rw0_wd_in[184]
    DIRECTION INPUT ;
    USE SIGNAL ;
    SHAPE ABUTMENT ;
    PORT
      LAYER M3 ;
      RECT 0 51.835 0.07 51.905 ;
    END
  END rw0_wd_in[184]
  PIN rw0_wd_in[185]
    DIRECTION INPUT ;
    USE SIGNAL ;
    SHAPE ABUTMENT ;
    PORT
      LAYER M3 ;
      RECT 0 52.115 0.07 52.185 ;
    END
  END rw0_wd_in[185]
  PIN rw0_wd_in[186]
    DIRECTION INPUT ;
    USE SIGNAL ;
    SHAPE ABUTMENT ;
    PORT
      LAYER M3 ;
      RECT 0 52.395 0.07 52.465 ;
    END
  END rw0_wd_in[186]
  PIN rw0_wd_in[187]
    DIRECTION INPUT ;
    USE SIGNAL ;
    SHAPE ABUTMENT ;
    PORT
      LAYER M3 ;
      RECT 0 52.675 0.07 52.745 ;
    END
  END rw0_wd_in[187]
  PIN rw0_wd_in[188]
    DIRECTION INPUT ;
    USE SIGNAL ;
    SHAPE ABUTMENT ;
    PORT
      LAYER M3 ;
      RECT 0 52.955 0.07 53.025 ;
    END
  END rw0_wd_in[188]
  PIN rw0_wd_in[189]
    DIRECTION INPUT ;
    USE SIGNAL ;
    SHAPE ABUTMENT ;
    PORT
      LAYER M3 ;
      RECT 0 53.235 0.07 53.305 ;
    END
  END rw0_wd_in[189]
  PIN rw0_wd_in[190]
    DIRECTION INPUT ;
    USE SIGNAL ;
    SHAPE ABUTMENT ;
    PORT
      LAYER M3 ;
      RECT 0 53.515 0.07 53.585 ;
    END
  END rw0_wd_in[190]
  PIN rw0_wd_in[191]
    DIRECTION INPUT ;
    USE SIGNAL ;
    SHAPE ABUTMENT ;
    PORT
      LAYER M3 ;
      RECT 0 53.795 0.07 53.865 ;
    END
  END rw0_wd_in[191]
  PIN rw0_wd_in[192]
    DIRECTION INPUT ;
    USE SIGNAL ;
    SHAPE ABUTMENT ;
    PORT
      LAYER M3 ;
      RECT 0 54.075 0.07 54.145 ;
    END
  END rw0_wd_in[192]
  PIN rw0_wd_in[193]
    DIRECTION INPUT ;
    USE SIGNAL ;
    SHAPE ABUTMENT ;
    PORT
      LAYER M3 ;
      RECT 0 54.355 0.07 54.425 ;
    END
  END rw0_wd_in[193]
  PIN rw0_wd_in[194]
    DIRECTION INPUT ;
    USE SIGNAL ;
    SHAPE ABUTMENT ;
    PORT
      LAYER M3 ;
      RECT 0 54.635 0.07 54.705 ;
    END
  END rw0_wd_in[194]
  PIN rw0_wd_in[195]
    DIRECTION INPUT ;
    USE SIGNAL ;
    SHAPE ABUTMENT ;
    PORT
      LAYER M3 ;
      RECT 0 54.915 0.07 54.985 ;
    END
  END rw0_wd_in[195]
  PIN rw0_wd_in[196]
    DIRECTION INPUT ;
    USE SIGNAL ;
    SHAPE ABUTMENT ;
    PORT
      LAYER M3 ;
      RECT 0 55.195 0.07 55.265 ;
    END
  END rw0_wd_in[196]
  PIN rw0_wd_in[197]
    DIRECTION INPUT ;
    USE SIGNAL ;
    SHAPE ABUTMENT ;
    PORT
      LAYER M3 ;
      RECT 0 55.475 0.07 55.545 ;
    END
  END rw0_wd_in[197]
  PIN rw0_wd_in[198]
    DIRECTION INPUT ;
    USE SIGNAL ;
    SHAPE ABUTMENT ;
    PORT
      LAYER M3 ;
      RECT 0 55.755 0.07 55.825 ;
    END
  END rw0_wd_in[198]
  PIN rw0_wd_in[199]
    DIRECTION INPUT ;
    USE SIGNAL ;
    SHAPE ABUTMENT ;
    PORT
      LAYER M3 ;
      RECT 0 56.035 0.07 56.105 ;
    END
  END rw0_wd_in[199]
  PIN rw0_wd_in[200]
    DIRECTION INPUT ;
    USE SIGNAL ;
    SHAPE ABUTMENT ;
    PORT
      LAYER M3 ;
      RECT 0 56.315 0.07 56.385 ;
    END
  END rw0_wd_in[200]
  PIN rw0_wd_in[201]
    DIRECTION INPUT ;
    USE SIGNAL ;
    SHAPE ABUTMENT ;
    PORT
      LAYER M3 ;
      RECT 0 56.595 0.07 56.665 ;
    END
  END rw0_wd_in[201]
  PIN rw0_wd_in[202]
    DIRECTION INPUT ;
    USE SIGNAL ;
    SHAPE ABUTMENT ;
    PORT
      LAYER M3 ;
      RECT 0 56.875 0.07 56.945 ;
    END
  END rw0_wd_in[202]
  PIN rw0_wd_in[203]
    DIRECTION INPUT ;
    USE SIGNAL ;
    SHAPE ABUTMENT ;
    PORT
      LAYER M3 ;
      RECT 0 57.155 0.07 57.225 ;
    END
  END rw0_wd_in[203]
  PIN rw0_wd_in[204]
    DIRECTION INPUT ;
    USE SIGNAL ;
    SHAPE ABUTMENT ;
    PORT
      LAYER M3 ;
      RECT 0 57.435 0.07 57.505 ;
    END
  END rw0_wd_in[204]
  PIN rw0_wd_in[205]
    DIRECTION INPUT ;
    USE SIGNAL ;
    SHAPE ABUTMENT ;
    PORT
      LAYER M3 ;
      RECT 0 57.715 0.07 57.785 ;
    END
  END rw0_wd_in[205]
  PIN rw0_wd_in[206]
    DIRECTION INPUT ;
    USE SIGNAL ;
    SHAPE ABUTMENT ;
    PORT
      LAYER M3 ;
      RECT 0 57.995 0.07 58.065 ;
    END
  END rw0_wd_in[206]
  PIN rw0_wd_in[207]
    DIRECTION INPUT ;
    USE SIGNAL ;
    SHAPE ABUTMENT ;
    PORT
      LAYER M3 ;
      RECT 0 58.275 0.07 58.345 ;
    END
  END rw0_wd_in[207]
  PIN rw0_wd_in[208]
    DIRECTION INPUT ;
    USE SIGNAL ;
    SHAPE ABUTMENT ;
    PORT
      LAYER M3 ;
      RECT 0 58.555 0.07 58.625 ;
    END
  END rw0_wd_in[208]
  PIN rw0_wd_in[209]
    DIRECTION INPUT ;
    USE SIGNAL ;
    SHAPE ABUTMENT ;
    PORT
      LAYER M3 ;
      RECT 0 58.835 0.07 58.905 ;
    END
  END rw0_wd_in[209]
  PIN rw0_wd_in[210]
    DIRECTION INPUT ;
    USE SIGNAL ;
    SHAPE ABUTMENT ;
    PORT
      LAYER M3 ;
      RECT 0 59.115 0.07 59.185 ;
    END
  END rw0_wd_in[210]
  PIN rw0_wd_in[211]
    DIRECTION INPUT ;
    USE SIGNAL ;
    SHAPE ABUTMENT ;
    PORT
      LAYER M3 ;
      RECT 0 59.395 0.07 59.465 ;
    END
  END rw0_wd_in[211]
  PIN rw0_wd_in[212]
    DIRECTION INPUT ;
    USE SIGNAL ;
    SHAPE ABUTMENT ;
    PORT
      LAYER M3 ;
      RECT 0 59.675 0.07 59.745 ;
    END
  END rw0_wd_in[212]
  PIN rw0_wd_in[213]
    DIRECTION INPUT ;
    USE SIGNAL ;
    SHAPE ABUTMENT ;
    PORT
      LAYER M3 ;
      RECT 0 59.955 0.07 60.025 ;
    END
  END rw0_wd_in[213]
  PIN rw0_wd_in[214]
    DIRECTION INPUT ;
    USE SIGNAL ;
    SHAPE ABUTMENT ;
    PORT
      LAYER M3 ;
      RECT 0 60.235 0.07 60.305 ;
    END
  END rw0_wd_in[214]
  PIN rw0_wd_in[215]
    DIRECTION INPUT ;
    USE SIGNAL ;
    SHAPE ABUTMENT ;
    PORT
      LAYER M3 ;
      RECT 0 60.515 0.07 60.585 ;
    END
  END rw0_wd_in[215]
  PIN rw0_wd_in[216]
    DIRECTION INPUT ;
    USE SIGNAL ;
    SHAPE ABUTMENT ;
    PORT
      LAYER M3 ;
      RECT 0 60.795 0.07 60.865 ;
    END
  END rw0_wd_in[216]
  PIN rw0_wd_in[217]
    DIRECTION INPUT ;
    USE SIGNAL ;
    SHAPE ABUTMENT ;
    PORT
      LAYER M3 ;
      RECT 0 61.075 0.07 61.145 ;
    END
  END rw0_wd_in[217]
  PIN rw0_wd_in[218]
    DIRECTION INPUT ;
    USE SIGNAL ;
    SHAPE ABUTMENT ;
    PORT
      LAYER M3 ;
      RECT 0 61.355 0.07 61.425 ;
    END
  END rw0_wd_in[218]
  PIN rw0_wd_in[219]
    DIRECTION INPUT ;
    USE SIGNAL ;
    SHAPE ABUTMENT ;
    PORT
      LAYER M3 ;
      RECT 0 61.635 0.07 61.705 ;
    END
  END rw0_wd_in[219]
  PIN rw0_wd_in[220]
    DIRECTION INPUT ;
    USE SIGNAL ;
    SHAPE ABUTMENT ;
    PORT
      LAYER M3 ;
      RECT 0 61.915 0.07 61.985 ;
    END
  END rw0_wd_in[220]
  PIN rw0_wd_in[221]
    DIRECTION INPUT ;
    USE SIGNAL ;
    SHAPE ABUTMENT ;
    PORT
      LAYER M3 ;
      RECT 0 62.195 0.07 62.265 ;
    END
  END rw0_wd_in[221]
  PIN rw0_wd_in[222]
    DIRECTION INPUT ;
    USE SIGNAL ;
    SHAPE ABUTMENT ;
    PORT
      LAYER M3 ;
      RECT 0 62.475 0.07 62.545 ;
    END
  END rw0_wd_in[222]
  PIN rw0_wd_in[223]
    DIRECTION INPUT ;
    USE SIGNAL ;
    SHAPE ABUTMENT ;
    PORT
      LAYER M3 ;
      RECT 0 62.755 0.07 62.825 ;
    END
  END rw0_wd_in[223]
  PIN rw0_wd_in[224]
    DIRECTION INPUT ;
    USE SIGNAL ;
    SHAPE ABUTMENT ;
    PORT
      LAYER M3 ;
      RECT 0 63.035 0.07 63.105 ;
    END
  END rw0_wd_in[224]
  PIN rw0_wd_in[225]
    DIRECTION INPUT ;
    USE SIGNAL ;
    SHAPE ABUTMENT ;
    PORT
      LAYER M3 ;
      RECT 0 63.315 0.07 63.385 ;
    END
  END rw0_wd_in[225]
  PIN rw0_wd_in[226]
    DIRECTION INPUT ;
    USE SIGNAL ;
    SHAPE ABUTMENT ;
    PORT
      LAYER M3 ;
      RECT 0 63.595 0.07 63.665 ;
    END
  END rw0_wd_in[226]
  PIN rw0_wd_in[227]
    DIRECTION INPUT ;
    USE SIGNAL ;
    SHAPE ABUTMENT ;
    PORT
      LAYER M3 ;
      RECT 0 63.875 0.07 63.945 ;
    END
  END rw0_wd_in[227]
  PIN rw0_wd_in[228]
    DIRECTION INPUT ;
    USE SIGNAL ;
    SHAPE ABUTMENT ;
    PORT
      LAYER M3 ;
      RECT 0 64.155 0.07 64.225 ;
    END
  END rw0_wd_in[228]
  PIN rw0_wd_in[229]
    DIRECTION INPUT ;
    USE SIGNAL ;
    SHAPE ABUTMENT ;
    PORT
      LAYER M3 ;
      RECT 0 64.435 0.07 64.505 ;
    END
  END rw0_wd_in[229]
  PIN rw0_wd_in[230]
    DIRECTION INPUT ;
    USE SIGNAL ;
    SHAPE ABUTMENT ;
    PORT
      LAYER M3 ;
      RECT 0 64.715 0.07 64.785 ;
    END
  END rw0_wd_in[230]
  PIN rw0_wd_in[231]
    DIRECTION INPUT ;
    USE SIGNAL ;
    SHAPE ABUTMENT ;
    PORT
      LAYER M3 ;
      RECT 0 64.995 0.07 65.065 ;
    END
  END rw0_wd_in[231]
  PIN rw0_wd_in[232]
    DIRECTION INPUT ;
    USE SIGNAL ;
    SHAPE ABUTMENT ;
    PORT
      LAYER M3 ;
      RECT 0 65.275 0.07 65.345 ;
    END
  END rw0_wd_in[232]
  PIN rw0_wd_in[233]
    DIRECTION INPUT ;
    USE SIGNAL ;
    SHAPE ABUTMENT ;
    PORT
      LAYER M3 ;
      RECT 0 65.555 0.07 65.625 ;
    END
  END rw0_wd_in[233]
  PIN rw0_wd_in[234]
    DIRECTION INPUT ;
    USE SIGNAL ;
    SHAPE ABUTMENT ;
    PORT
      LAYER M3 ;
      RECT 0 65.835 0.07 65.905 ;
    END
  END rw0_wd_in[234]
  PIN rw0_wd_in[235]
    DIRECTION INPUT ;
    USE SIGNAL ;
    SHAPE ABUTMENT ;
    PORT
      LAYER M3 ;
      RECT 0 66.115 0.07 66.185 ;
    END
  END rw0_wd_in[235]
  PIN rw0_wd_in[236]
    DIRECTION INPUT ;
    USE SIGNAL ;
    SHAPE ABUTMENT ;
    PORT
      LAYER M3 ;
      RECT 0 66.395 0.07 66.465 ;
    END
  END rw0_wd_in[236]
  PIN rw0_wd_in[237]
    DIRECTION INPUT ;
    USE SIGNAL ;
    SHAPE ABUTMENT ;
    PORT
      LAYER M3 ;
      RECT 0 66.675 0.07 66.745 ;
    END
  END rw0_wd_in[237]
  PIN rw0_wd_in[238]
    DIRECTION INPUT ;
    USE SIGNAL ;
    SHAPE ABUTMENT ;
    PORT
      LAYER M3 ;
      RECT 0 66.955 0.07 67.025 ;
    END
  END rw0_wd_in[238]
  PIN rw0_wd_in[239]
    DIRECTION INPUT ;
    USE SIGNAL ;
    SHAPE ABUTMENT ;
    PORT
      LAYER M3 ;
      RECT 0 67.235 0.07 67.305 ;
    END
  END rw0_wd_in[239]
  PIN rw0_wd_in[240]
    DIRECTION INPUT ;
    USE SIGNAL ;
    SHAPE ABUTMENT ;
    PORT
      LAYER M3 ;
      RECT 0 67.515 0.07 67.585 ;
    END
  END rw0_wd_in[240]
  PIN rw0_wd_in[241]
    DIRECTION INPUT ;
    USE SIGNAL ;
    SHAPE ABUTMENT ;
    PORT
      LAYER M3 ;
      RECT 0 67.795 0.07 67.865 ;
    END
  END rw0_wd_in[241]
  PIN rw0_wd_in[242]
    DIRECTION INPUT ;
    USE SIGNAL ;
    SHAPE ABUTMENT ;
    PORT
      LAYER M3 ;
      RECT 0 68.075 0.07 68.145 ;
    END
  END rw0_wd_in[242]
  PIN rw0_wd_in[243]
    DIRECTION INPUT ;
    USE SIGNAL ;
    SHAPE ABUTMENT ;
    PORT
      LAYER M3 ;
      RECT 0 68.355 0.07 68.425 ;
    END
  END rw0_wd_in[243]
  PIN rw0_wd_in[244]
    DIRECTION INPUT ;
    USE SIGNAL ;
    SHAPE ABUTMENT ;
    PORT
      LAYER M3 ;
      RECT 0 68.635 0.07 68.705 ;
    END
  END rw0_wd_in[244]
  PIN rw0_wd_in[245]
    DIRECTION INPUT ;
    USE SIGNAL ;
    SHAPE ABUTMENT ;
    PORT
      LAYER M3 ;
      RECT 0 68.915 0.07 68.985 ;
    END
  END rw0_wd_in[245]
  PIN rw0_wd_in[246]
    DIRECTION INPUT ;
    USE SIGNAL ;
    SHAPE ABUTMENT ;
    PORT
      LAYER M3 ;
      RECT 0 69.195 0.07 69.265 ;
    END
  END rw0_wd_in[246]
  PIN rw0_wd_in[247]
    DIRECTION INPUT ;
    USE SIGNAL ;
    SHAPE ABUTMENT ;
    PORT
      LAYER M3 ;
      RECT 0 69.475 0.07 69.545 ;
    END
  END rw0_wd_in[247]
  PIN rw0_wd_in[248]
    DIRECTION INPUT ;
    USE SIGNAL ;
    SHAPE ABUTMENT ;
    PORT
      LAYER M3 ;
      RECT 0 69.755 0.07 69.825 ;
    END
  END rw0_wd_in[248]
  PIN rw0_wd_in[249]
    DIRECTION INPUT ;
    USE SIGNAL ;
    SHAPE ABUTMENT ;
    PORT
      LAYER M3 ;
      RECT 0 70.035 0.07 70.105 ;
    END
  END rw0_wd_in[249]
  PIN rw0_wd_in[250]
    DIRECTION INPUT ;
    USE SIGNAL ;
    SHAPE ABUTMENT ;
    PORT
      LAYER M3 ;
      RECT 0 70.315 0.07 70.385 ;
    END
  END rw0_wd_in[250]
  PIN rw0_wd_in[251]
    DIRECTION INPUT ;
    USE SIGNAL ;
    SHAPE ABUTMENT ;
    PORT
      LAYER M3 ;
      RECT 0 70.595 0.07 70.665 ;
    END
  END rw0_wd_in[251]
  PIN rw0_wd_in[252]
    DIRECTION INPUT ;
    USE SIGNAL ;
    SHAPE ABUTMENT ;
    PORT
      LAYER M3 ;
      RECT 0 70.875 0.07 70.945 ;
    END
  END rw0_wd_in[252]
  PIN rw0_wd_in[253]
    DIRECTION INPUT ;
    USE SIGNAL ;
    SHAPE ABUTMENT ;
    PORT
      LAYER M3 ;
      RECT 0 71.155 0.07 71.225 ;
    END
  END rw0_wd_in[253]
  PIN rw0_wd_in[254]
    DIRECTION INPUT ;
    USE SIGNAL ;
    SHAPE ABUTMENT ;
    PORT
      LAYER M3 ;
      RECT 0 71.435 0.07 71.505 ;
    END
  END rw0_wd_in[254]
  PIN rw0_wd_in[255]
    DIRECTION INPUT ;
    USE SIGNAL ;
    SHAPE ABUTMENT ;
    PORT
      LAYER M3 ;
      RECT 0 71.715 0.07 71.785 ;
    END
  END rw0_wd_in[255]
  PIN rw0_wd_in[256]
    DIRECTION INPUT ;
    USE SIGNAL ;
    SHAPE ABUTMENT ;
    PORT
      LAYER M3 ;
      RECT 0 71.995 0.07 72.065 ;
    END
  END rw0_wd_in[256]
  PIN rw0_wd_in[257]
    DIRECTION INPUT ;
    USE SIGNAL ;
    SHAPE ABUTMENT ;
    PORT
      LAYER M3 ;
      RECT 0 72.275 0.07 72.345 ;
    END
  END rw0_wd_in[257]
  PIN rw0_wd_in[258]
    DIRECTION INPUT ;
    USE SIGNAL ;
    SHAPE ABUTMENT ;
    PORT
      LAYER M3 ;
      RECT 0 72.555 0.07 72.625 ;
    END
  END rw0_wd_in[258]
  PIN rw0_wd_in[259]
    DIRECTION INPUT ;
    USE SIGNAL ;
    SHAPE ABUTMENT ;
    PORT
      LAYER M3 ;
      RECT 0 72.835 0.07 72.905 ;
    END
  END rw0_wd_in[259]
  PIN rw0_wd_in[260]
    DIRECTION INPUT ;
    USE SIGNAL ;
    SHAPE ABUTMENT ;
    PORT
      LAYER M3 ;
      RECT 0 73.115 0.07 73.185 ;
    END
  END rw0_wd_in[260]
  PIN rw0_wd_in[261]
    DIRECTION INPUT ;
    USE SIGNAL ;
    SHAPE ABUTMENT ;
    PORT
      LAYER M3 ;
      RECT 0 73.395 0.07 73.465 ;
    END
  END rw0_wd_in[261]
  PIN rw0_wd_in[262]
    DIRECTION INPUT ;
    USE SIGNAL ;
    SHAPE ABUTMENT ;
    PORT
      LAYER M3 ;
      RECT 0 73.675 0.07 73.745 ;
    END
  END rw0_wd_in[262]
  PIN rw0_wd_in[263]
    DIRECTION INPUT ;
    USE SIGNAL ;
    SHAPE ABUTMENT ;
    PORT
      LAYER M3 ;
      RECT 0 73.955 0.07 74.025 ;
    END
  END rw0_wd_in[263]
  PIN rw0_wd_in[264]
    DIRECTION INPUT ;
    USE SIGNAL ;
    SHAPE ABUTMENT ;
    PORT
      LAYER M3 ;
      RECT 0 74.235 0.07 74.305 ;
    END
  END rw0_wd_in[264]
  PIN rw0_wd_in[265]
    DIRECTION INPUT ;
    USE SIGNAL ;
    SHAPE ABUTMENT ;
    PORT
      LAYER M3 ;
      RECT 0 74.515 0.07 74.585 ;
    END
  END rw0_wd_in[265]
  PIN rw0_wd_in[266]
    DIRECTION INPUT ;
    USE SIGNAL ;
    SHAPE ABUTMENT ;
    PORT
      LAYER M3 ;
      RECT 0 74.795 0.07 74.865 ;
    END
  END rw0_wd_in[266]
  PIN rw0_wd_in[267]
    DIRECTION INPUT ;
    USE SIGNAL ;
    SHAPE ABUTMENT ;
    PORT
      LAYER M3 ;
      RECT 0 75.075 0.07 75.145 ;
    END
  END rw0_wd_in[267]
  PIN rw0_wd_in[268]
    DIRECTION INPUT ;
    USE SIGNAL ;
    SHAPE ABUTMENT ;
    PORT
      LAYER M3 ;
      RECT 0 75.355 0.07 75.425 ;
    END
  END rw0_wd_in[268]
  PIN rw0_wd_in[269]
    DIRECTION INPUT ;
    USE SIGNAL ;
    SHAPE ABUTMENT ;
    PORT
      LAYER M3 ;
      RECT 0 75.635 0.07 75.705 ;
    END
  END rw0_wd_in[269]
  PIN rw0_wd_in[270]
    DIRECTION INPUT ;
    USE SIGNAL ;
    SHAPE ABUTMENT ;
    PORT
      LAYER M3 ;
      RECT 0 75.915 0.07 75.985 ;
    END
  END rw0_wd_in[270]
  PIN rw0_wd_in[271]
    DIRECTION INPUT ;
    USE SIGNAL ;
    SHAPE ABUTMENT ;
    PORT
      LAYER M3 ;
      RECT 0 76.195 0.07 76.265 ;
    END
  END rw0_wd_in[271]
  PIN rw0_wd_in[272]
    DIRECTION INPUT ;
    USE SIGNAL ;
    SHAPE ABUTMENT ;
    PORT
      LAYER M3 ;
      RECT 0 76.475 0.07 76.545 ;
    END
  END rw0_wd_in[272]
  PIN rw0_wd_in[273]
    DIRECTION INPUT ;
    USE SIGNAL ;
    SHAPE ABUTMENT ;
    PORT
      LAYER M3 ;
      RECT 0 76.755 0.07 76.825 ;
    END
  END rw0_wd_in[273]
  PIN rw0_wd_in[274]
    DIRECTION INPUT ;
    USE SIGNAL ;
    SHAPE ABUTMENT ;
    PORT
      LAYER M3 ;
      RECT 0 77.035 0.07 77.105 ;
    END
  END rw0_wd_in[274]
  PIN rw0_wd_in[275]
    DIRECTION INPUT ;
    USE SIGNAL ;
    SHAPE ABUTMENT ;
    PORT
      LAYER M3 ;
      RECT 0 77.315 0.07 77.385 ;
    END
  END rw0_wd_in[275]
  PIN rw0_wd_in[276]
    DIRECTION INPUT ;
    USE SIGNAL ;
    SHAPE ABUTMENT ;
    PORT
      LAYER M3 ;
      RECT 0 77.595 0.07 77.665 ;
    END
  END rw0_wd_in[276]
  PIN rw0_wd_in[277]
    DIRECTION INPUT ;
    USE SIGNAL ;
    SHAPE ABUTMENT ;
    PORT
      LAYER M3 ;
      RECT 0 77.875 0.07 77.945 ;
    END
  END rw0_wd_in[277]
  PIN rw0_wd_in[278]
    DIRECTION INPUT ;
    USE SIGNAL ;
    SHAPE ABUTMENT ;
    PORT
      LAYER M3 ;
      RECT 0 78.155 0.07 78.225 ;
    END
  END rw0_wd_in[278]
  PIN rw0_wd_in[279]
    DIRECTION INPUT ;
    USE SIGNAL ;
    SHAPE ABUTMENT ;
    PORT
      LAYER M3 ;
      RECT 0 78.435 0.07 78.505 ;
    END
  END rw0_wd_in[279]
  PIN rw0_wd_in[280]
    DIRECTION INPUT ;
    USE SIGNAL ;
    SHAPE ABUTMENT ;
    PORT
      LAYER M3 ;
      RECT 0 78.715 0.07 78.785 ;
    END
  END rw0_wd_in[280]
  PIN rw0_wd_in[281]
    DIRECTION INPUT ;
    USE SIGNAL ;
    SHAPE ABUTMENT ;
    PORT
      LAYER M3 ;
      RECT 0 78.995 0.07 79.065 ;
    END
  END rw0_wd_in[281]
  PIN rw0_wd_in[282]
    DIRECTION INPUT ;
    USE SIGNAL ;
    SHAPE ABUTMENT ;
    PORT
      LAYER M3 ;
      RECT 0 79.275 0.07 79.345 ;
    END
  END rw0_wd_in[282]
  PIN rw0_wd_in[283]
    DIRECTION INPUT ;
    USE SIGNAL ;
    SHAPE ABUTMENT ;
    PORT
      LAYER M3 ;
      RECT 0 79.555 0.07 79.625 ;
    END
  END rw0_wd_in[283]
  PIN rw0_wd_in[284]
    DIRECTION INPUT ;
    USE SIGNAL ;
    SHAPE ABUTMENT ;
    PORT
      LAYER M3 ;
      RECT 0 79.835 0.07 79.905 ;
    END
  END rw0_wd_in[284]
  PIN rw0_wd_in[285]
    DIRECTION INPUT ;
    USE SIGNAL ;
    SHAPE ABUTMENT ;
    PORT
      LAYER M3 ;
      RECT 0 80.115 0.07 80.185 ;
    END
  END rw0_wd_in[285]
  PIN rw0_wd_in[286]
    DIRECTION INPUT ;
    USE SIGNAL ;
    SHAPE ABUTMENT ;
    PORT
      LAYER M3 ;
      RECT 0 80.395 0.07 80.465 ;
    END
  END rw0_wd_in[286]
  PIN rw0_wd_in[287]
    DIRECTION INPUT ;
    USE SIGNAL ;
    SHAPE ABUTMENT ;
    PORT
      LAYER M3 ;
      RECT 0 80.675 0.07 80.745 ;
    END
  END rw0_wd_in[287]
  PIN rw0_wd_in[288]
    DIRECTION INPUT ;
    USE SIGNAL ;
    SHAPE ABUTMENT ;
    PORT
      LAYER M3 ;
      RECT 0 80.955 0.07 81.025 ;
    END
  END rw0_wd_in[288]
  PIN rw0_wd_in[289]
    DIRECTION INPUT ;
    USE SIGNAL ;
    SHAPE ABUTMENT ;
    PORT
      LAYER M3 ;
      RECT 0 81.235 0.07 81.305 ;
    END
  END rw0_wd_in[289]
  PIN rw0_wd_in[290]
    DIRECTION INPUT ;
    USE SIGNAL ;
    SHAPE ABUTMENT ;
    PORT
      LAYER M3 ;
      RECT 0 81.515 0.07 81.585 ;
    END
  END rw0_wd_in[290]
  PIN rw0_wd_in[291]
    DIRECTION INPUT ;
    USE SIGNAL ;
    SHAPE ABUTMENT ;
    PORT
      LAYER M3 ;
      RECT 0 81.795 0.07 81.865 ;
    END
  END rw0_wd_in[291]
  PIN rw0_wd_in[292]
    DIRECTION INPUT ;
    USE SIGNAL ;
    SHAPE ABUTMENT ;
    PORT
      LAYER M3 ;
      RECT 0 82.075 0.07 82.145 ;
    END
  END rw0_wd_in[292]
  PIN rw0_wd_in[293]
    DIRECTION INPUT ;
    USE SIGNAL ;
    SHAPE ABUTMENT ;
    PORT
      LAYER M3 ;
      RECT 0 82.355 0.07 82.425 ;
    END
  END rw0_wd_in[293]
  PIN rw0_wd_in[294]
    DIRECTION INPUT ;
    USE SIGNAL ;
    SHAPE ABUTMENT ;
    PORT
      LAYER M3 ;
      RECT 0 82.635 0.07 82.705 ;
    END
  END rw0_wd_in[294]
  PIN rw0_wd_in[295]
    DIRECTION INPUT ;
    USE SIGNAL ;
    SHAPE ABUTMENT ;
    PORT
      LAYER M3 ;
      RECT 0 82.915 0.07 82.985 ;
    END
  END rw0_wd_in[295]
  PIN rw0_wd_in[296]
    DIRECTION INPUT ;
    USE SIGNAL ;
    SHAPE ABUTMENT ;
    PORT
      LAYER M3 ;
      RECT 0 83.195 0.07 83.265 ;
    END
  END rw0_wd_in[296]
  PIN rw0_wd_in[297]
    DIRECTION INPUT ;
    USE SIGNAL ;
    SHAPE ABUTMENT ;
    PORT
      LAYER M3 ;
      RECT 0 83.475 0.07 83.545 ;
    END
  END rw0_wd_in[297]
  PIN rw0_wd_in[298]
    DIRECTION INPUT ;
    USE SIGNAL ;
    SHAPE ABUTMENT ;
    PORT
      LAYER M3 ;
      RECT 0 83.755 0.07 83.825 ;
    END
  END rw0_wd_in[298]
  PIN rw0_wd_in[299]
    DIRECTION INPUT ;
    USE SIGNAL ;
    SHAPE ABUTMENT ;
    PORT
      LAYER M3 ;
      RECT 0 84.035 0.07 84.105 ;
    END
  END rw0_wd_in[299]
  PIN rw0_wd_in[300]
    DIRECTION INPUT ;
    USE SIGNAL ;
    SHAPE ABUTMENT ;
    PORT
      LAYER M3 ;
      RECT 0 84.315 0.07 84.385 ;
    END
  END rw0_wd_in[300]
  PIN rw0_wd_in[301]
    DIRECTION INPUT ;
    USE SIGNAL ;
    SHAPE ABUTMENT ;
    PORT
      LAYER M3 ;
      RECT 0 84.595 0.07 84.665 ;
    END
  END rw0_wd_in[301]
  PIN rw0_wd_in[302]
    DIRECTION INPUT ;
    USE SIGNAL ;
    SHAPE ABUTMENT ;
    PORT
      LAYER M3 ;
      RECT 0 84.875 0.07 84.945 ;
    END
  END rw0_wd_in[302]
  PIN rw0_wd_in[303]
    DIRECTION INPUT ;
    USE SIGNAL ;
    SHAPE ABUTMENT ;
    PORT
      LAYER M3 ;
      RECT 0 85.155 0.07 85.225 ;
    END
  END rw0_wd_in[303]
  PIN rw0_wd_in[304]
    DIRECTION INPUT ;
    USE SIGNAL ;
    SHAPE ABUTMENT ;
    PORT
      LAYER M3 ;
      RECT 0 85.435 0.07 85.505 ;
    END
  END rw0_wd_in[304]
  PIN rw0_wd_in[305]
    DIRECTION INPUT ;
    USE SIGNAL ;
    SHAPE ABUTMENT ;
    PORT
      LAYER M3 ;
      RECT 0 85.715 0.07 85.785 ;
    END
  END rw0_wd_in[305]
  PIN rw0_wd_in[306]
    DIRECTION INPUT ;
    USE SIGNAL ;
    SHAPE ABUTMENT ;
    PORT
      LAYER M3 ;
      RECT 0 85.995 0.07 86.065 ;
    END
  END rw0_wd_in[306]
  PIN rw0_wd_in[307]
    DIRECTION INPUT ;
    USE SIGNAL ;
    SHAPE ABUTMENT ;
    PORT
      LAYER M3 ;
      RECT 0 86.275 0.07 86.345 ;
    END
  END rw0_wd_in[307]
  PIN rw0_wd_in[308]
    DIRECTION INPUT ;
    USE SIGNAL ;
    SHAPE ABUTMENT ;
    PORT
      LAYER M3 ;
      RECT 0 86.555 0.07 86.625 ;
    END
  END rw0_wd_in[308]
  PIN rw0_wd_in[309]
    DIRECTION INPUT ;
    USE SIGNAL ;
    SHAPE ABUTMENT ;
    PORT
      LAYER M3 ;
      RECT 0 86.835 0.07 86.905 ;
    END
  END rw0_wd_in[309]
  PIN rw0_wd_in[310]
    DIRECTION INPUT ;
    USE SIGNAL ;
    SHAPE ABUTMENT ;
    PORT
      LAYER M3 ;
      RECT 0 87.115 0.07 87.185 ;
    END
  END rw0_wd_in[310]
  PIN rw0_wd_in[311]
    DIRECTION INPUT ;
    USE SIGNAL ;
    SHAPE ABUTMENT ;
    PORT
      LAYER M3 ;
      RECT 0 87.395 0.07 87.465 ;
    END
  END rw0_wd_in[311]
  PIN rw0_wd_in[312]
    DIRECTION INPUT ;
    USE SIGNAL ;
    SHAPE ABUTMENT ;
    PORT
      LAYER M3 ;
      RECT 0 87.675 0.07 87.745 ;
    END
  END rw0_wd_in[312]
  PIN rw0_wd_in[313]
    DIRECTION INPUT ;
    USE SIGNAL ;
    SHAPE ABUTMENT ;
    PORT
      LAYER M3 ;
      RECT 0 87.955 0.07 88.025 ;
    END
  END rw0_wd_in[313]
  PIN rw0_wd_in[314]
    DIRECTION INPUT ;
    USE SIGNAL ;
    SHAPE ABUTMENT ;
    PORT
      LAYER M3 ;
      RECT 0 88.235 0.07 88.305 ;
    END
  END rw0_wd_in[314]
  PIN rw0_wd_in[315]
    DIRECTION INPUT ;
    USE SIGNAL ;
    SHAPE ABUTMENT ;
    PORT
      LAYER M3 ;
      RECT 0 88.515 0.07 88.585 ;
    END
  END rw0_wd_in[315]
  PIN rw0_wd_in[316]
    DIRECTION INPUT ;
    USE SIGNAL ;
    SHAPE ABUTMENT ;
    PORT
      LAYER M3 ;
      RECT 0 88.795 0.07 88.865 ;
    END
  END rw0_wd_in[316]
  PIN rw0_wd_in[317]
    DIRECTION INPUT ;
    USE SIGNAL ;
    SHAPE ABUTMENT ;
    PORT
      LAYER M3 ;
      RECT 0 89.075 0.07 89.145 ;
    END
  END rw0_wd_in[317]
  PIN rw0_wd_in[318]
    DIRECTION INPUT ;
    USE SIGNAL ;
    SHAPE ABUTMENT ;
    PORT
      LAYER M3 ;
      RECT 0 89.355 0.07 89.425 ;
    END
  END rw0_wd_in[318]
  PIN rw0_wd_in[319]
    DIRECTION INPUT ;
    USE SIGNAL ;
    SHAPE ABUTMENT ;
    PORT
      LAYER M3 ;
      RECT 0 89.635 0.07 89.705 ;
    END
  END rw0_wd_in[319]
  PIN rw0_wd_in[320]
    DIRECTION INPUT ;
    USE SIGNAL ;
    SHAPE ABUTMENT ;
    PORT
      LAYER M3 ;
      RECT 0 89.915 0.07 89.985 ;
    END
  END rw0_wd_in[320]
  PIN rw0_wd_in[321]
    DIRECTION INPUT ;
    USE SIGNAL ;
    SHAPE ABUTMENT ;
    PORT
      LAYER M3 ;
      RECT 0 90.195 0.07 90.265 ;
    END
  END rw0_wd_in[321]
  PIN rw0_wd_in[322]
    DIRECTION INPUT ;
    USE SIGNAL ;
    SHAPE ABUTMENT ;
    PORT
      LAYER M3 ;
      RECT 0 90.475 0.07 90.545 ;
    END
  END rw0_wd_in[322]
  PIN rw0_wd_in[323]
    DIRECTION INPUT ;
    USE SIGNAL ;
    SHAPE ABUTMENT ;
    PORT
      LAYER M3 ;
      RECT 0 90.755 0.07 90.825 ;
    END
  END rw0_wd_in[323]
  PIN rw0_wd_in[324]
    DIRECTION INPUT ;
    USE SIGNAL ;
    SHAPE ABUTMENT ;
    PORT
      LAYER M3 ;
      RECT 0 91.035 0.07 91.105 ;
    END
  END rw0_wd_in[324]
  PIN rw0_wd_in[325]
    DIRECTION INPUT ;
    USE SIGNAL ;
    SHAPE ABUTMENT ;
    PORT
      LAYER M3 ;
      RECT 0 91.315 0.07 91.385 ;
    END
  END rw0_wd_in[325]
  PIN rw0_wd_in[326]
    DIRECTION INPUT ;
    USE SIGNAL ;
    SHAPE ABUTMENT ;
    PORT
      LAYER M3 ;
      RECT 0 91.595 0.07 91.665 ;
    END
  END rw0_wd_in[326]
  PIN rw0_wd_in[327]
    DIRECTION INPUT ;
    USE SIGNAL ;
    SHAPE ABUTMENT ;
    PORT
      LAYER M3 ;
      RECT 0 91.875 0.07 91.945 ;
    END
  END rw0_wd_in[327]
  PIN rw0_wd_in[328]
    DIRECTION INPUT ;
    USE SIGNAL ;
    SHAPE ABUTMENT ;
    PORT
      LAYER M3 ;
      RECT 0 92.155 0.07 92.225 ;
    END
  END rw0_wd_in[328]
  PIN rw0_wd_in[329]
    DIRECTION INPUT ;
    USE SIGNAL ;
    SHAPE ABUTMENT ;
    PORT
      LAYER M3 ;
      RECT 0 92.435 0.07 92.505 ;
    END
  END rw0_wd_in[329]
  PIN rw0_wd_in[330]
    DIRECTION INPUT ;
    USE SIGNAL ;
    SHAPE ABUTMENT ;
    PORT
      LAYER M3 ;
      RECT 0 92.715 0.07 92.785 ;
    END
  END rw0_wd_in[330]
  PIN rw0_wd_in[331]
    DIRECTION INPUT ;
    USE SIGNAL ;
    SHAPE ABUTMENT ;
    PORT
      LAYER M3 ;
      RECT 0 92.995 0.07 93.065 ;
    END
  END rw0_wd_in[331]
  PIN rw0_wd_in[332]
    DIRECTION INPUT ;
    USE SIGNAL ;
    SHAPE ABUTMENT ;
    PORT
      LAYER M3 ;
      RECT 0 93.275 0.07 93.345 ;
    END
  END rw0_wd_in[332]
  PIN rw0_wd_in[333]
    DIRECTION INPUT ;
    USE SIGNAL ;
    SHAPE ABUTMENT ;
    PORT
      LAYER M3 ;
      RECT 0 93.555 0.07 93.625 ;
    END
  END rw0_wd_in[333]
  PIN rw0_wd_in[334]
    DIRECTION INPUT ;
    USE SIGNAL ;
    SHAPE ABUTMENT ;
    PORT
      LAYER M3 ;
      RECT 0 93.835 0.07 93.905 ;
    END
  END rw0_wd_in[334]
  PIN rw0_wd_in[335]
    DIRECTION INPUT ;
    USE SIGNAL ;
    SHAPE ABUTMENT ;
    PORT
      LAYER M3 ;
      RECT 0 94.115 0.07 94.185 ;
    END
  END rw0_wd_in[335]
  PIN rw0_wd_in[336]
    DIRECTION INPUT ;
    USE SIGNAL ;
    SHAPE ABUTMENT ;
    PORT
      LAYER M3 ;
      RECT 0 94.395 0.07 94.465 ;
    END
  END rw0_wd_in[336]
  PIN rw0_wd_in[337]
    DIRECTION INPUT ;
    USE SIGNAL ;
    SHAPE ABUTMENT ;
    PORT
      LAYER M3 ;
      RECT 0 94.675 0.07 94.745 ;
    END
  END rw0_wd_in[337]
  PIN rw0_wd_in[338]
    DIRECTION INPUT ;
    USE SIGNAL ;
    SHAPE ABUTMENT ;
    PORT
      LAYER M3 ;
      RECT 0 94.955 0.07 95.025 ;
    END
  END rw0_wd_in[338]
  PIN rw0_wd_in[339]
    DIRECTION INPUT ;
    USE SIGNAL ;
    SHAPE ABUTMENT ;
    PORT
      LAYER M3 ;
      RECT 0 95.235 0.07 95.305 ;
    END
  END rw0_wd_in[339]
  PIN rw0_wd_in[340]
    DIRECTION INPUT ;
    USE SIGNAL ;
    SHAPE ABUTMENT ;
    PORT
      LAYER M3 ;
      RECT 0 95.515 0.07 95.585 ;
    END
  END rw0_wd_in[340]
  PIN rw0_wd_in[341]
    DIRECTION INPUT ;
    USE SIGNAL ;
    SHAPE ABUTMENT ;
    PORT
      LAYER M3 ;
      RECT 0 95.795 0.07 95.865 ;
    END
  END rw0_wd_in[341]
  PIN rw0_wd_in[342]
    DIRECTION INPUT ;
    USE SIGNAL ;
    SHAPE ABUTMENT ;
    PORT
      LAYER M3 ;
      RECT 0 96.075 0.07 96.145 ;
    END
  END rw0_wd_in[342]
  PIN rw0_wd_in[343]
    DIRECTION INPUT ;
    USE SIGNAL ;
    SHAPE ABUTMENT ;
    PORT
      LAYER M3 ;
      RECT 0 96.355 0.07 96.425 ;
    END
  END rw0_wd_in[343]
  PIN rw0_wd_in[344]
    DIRECTION INPUT ;
    USE SIGNAL ;
    SHAPE ABUTMENT ;
    PORT
      LAYER M3 ;
      RECT 0 96.635 0.07 96.705 ;
    END
  END rw0_wd_in[344]
  PIN rw0_wd_in[345]
    DIRECTION INPUT ;
    USE SIGNAL ;
    SHAPE ABUTMENT ;
    PORT
      LAYER M3 ;
      RECT 0 96.915 0.07 96.985 ;
    END
  END rw0_wd_in[345]
  PIN rw0_wd_in[346]
    DIRECTION INPUT ;
    USE SIGNAL ;
    SHAPE ABUTMENT ;
    PORT
      LAYER M3 ;
      RECT 0 97.195 0.07 97.265 ;
    END
  END rw0_wd_in[346]
  PIN rw0_wd_in[347]
    DIRECTION INPUT ;
    USE SIGNAL ;
    SHAPE ABUTMENT ;
    PORT
      LAYER M3 ;
      RECT 0 97.475 0.07 97.545 ;
    END
  END rw0_wd_in[347]
  PIN rw0_wd_in[348]
    DIRECTION INPUT ;
    USE SIGNAL ;
    SHAPE ABUTMENT ;
    PORT
      LAYER M3 ;
      RECT 0 97.755 0.07 97.825 ;
    END
  END rw0_wd_in[348]
  PIN rw0_wd_in[349]
    DIRECTION INPUT ;
    USE SIGNAL ;
    SHAPE ABUTMENT ;
    PORT
      LAYER M3 ;
      RECT 0 98.035 0.07 98.105 ;
    END
  END rw0_wd_in[349]
  PIN rw0_wd_in[350]
    DIRECTION INPUT ;
    USE SIGNAL ;
    SHAPE ABUTMENT ;
    PORT
      LAYER M3 ;
      RECT 0 98.315 0.07 98.385 ;
    END
  END rw0_wd_in[350]
  PIN rw0_wd_in[351]
    DIRECTION INPUT ;
    USE SIGNAL ;
    SHAPE ABUTMENT ;
    PORT
      LAYER M3 ;
      RECT 0 98.595 0.07 98.665 ;
    END
  END rw0_wd_in[351]
  PIN rw0_wd_in[352]
    DIRECTION INPUT ;
    USE SIGNAL ;
    SHAPE ABUTMENT ;
    PORT
      LAYER M3 ;
      RECT 0 98.875 0.07 98.945 ;
    END
  END rw0_wd_in[352]
  PIN rw0_wd_in[353]
    DIRECTION INPUT ;
    USE SIGNAL ;
    SHAPE ABUTMENT ;
    PORT
      LAYER M3 ;
      RECT 0 99.155 0.07 99.225 ;
    END
  END rw0_wd_in[353]
  PIN rw0_wd_in[354]
    DIRECTION INPUT ;
    USE SIGNAL ;
    SHAPE ABUTMENT ;
    PORT
      LAYER M3 ;
      RECT 0 99.435 0.07 99.505 ;
    END
  END rw0_wd_in[354]
  PIN rw0_wd_in[355]
    DIRECTION INPUT ;
    USE SIGNAL ;
    SHAPE ABUTMENT ;
    PORT
      LAYER M3 ;
      RECT 0 99.715 0.07 99.785 ;
    END
  END rw0_wd_in[355]
  PIN rw0_wd_in[356]
    DIRECTION INPUT ;
    USE SIGNAL ;
    SHAPE ABUTMENT ;
    PORT
      LAYER M3 ;
      RECT 0 99.995 0.07 100.065 ;
    END
  END rw0_wd_in[356]
  PIN rw0_wd_in[357]
    DIRECTION INPUT ;
    USE SIGNAL ;
    SHAPE ABUTMENT ;
    PORT
      LAYER M3 ;
      RECT 0 100.275 0.07 100.345 ;
    END
  END rw0_wd_in[357]
  PIN rw0_wd_in[358]
    DIRECTION INPUT ;
    USE SIGNAL ;
    SHAPE ABUTMENT ;
    PORT
      LAYER M3 ;
      RECT 0 100.555 0.07 100.625 ;
    END
  END rw0_wd_in[358]
  PIN rw0_wd_in[359]
    DIRECTION INPUT ;
    USE SIGNAL ;
    SHAPE ABUTMENT ;
    PORT
      LAYER M3 ;
      RECT 0 100.835 0.07 100.905 ;
    END
  END rw0_wd_in[359]
  PIN rw0_wd_in[360]
    DIRECTION INPUT ;
    USE SIGNAL ;
    SHAPE ABUTMENT ;
    PORT
      LAYER M3 ;
      RECT 0 101.115 0.07 101.185 ;
    END
  END rw0_wd_in[360]
  PIN rw0_wd_in[361]
    DIRECTION INPUT ;
    USE SIGNAL ;
    SHAPE ABUTMENT ;
    PORT
      LAYER M3 ;
      RECT 0 101.395 0.07 101.465 ;
    END
  END rw0_wd_in[361]
  PIN rw0_wd_in[362]
    DIRECTION INPUT ;
    USE SIGNAL ;
    SHAPE ABUTMENT ;
    PORT
      LAYER M3 ;
      RECT 0 101.675 0.07 101.745 ;
    END
  END rw0_wd_in[362]
  PIN rw0_wd_in[363]
    DIRECTION INPUT ;
    USE SIGNAL ;
    SHAPE ABUTMENT ;
    PORT
      LAYER M3 ;
      RECT 0 101.955 0.07 102.025 ;
    END
  END rw0_wd_in[363]
  PIN rw0_wd_in[364]
    DIRECTION INPUT ;
    USE SIGNAL ;
    SHAPE ABUTMENT ;
    PORT
      LAYER M3 ;
      RECT 0 102.235 0.07 102.305 ;
    END
  END rw0_wd_in[364]
  PIN rw0_wd_in[365]
    DIRECTION INPUT ;
    USE SIGNAL ;
    SHAPE ABUTMENT ;
    PORT
      LAYER M3 ;
      RECT 0 102.515 0.07 102.585 ;
    END
  END rw0_wd_in[365]
  PIN rw0_wd_in[366]
    DIRECTION INPUT ;
    USE SIGNAL ;
    SHAPE ABUTMENT ;
    PORT
      LAYER M3 ;
      RECT 0 102.795 0.07 102.865 ;
    END
  END rw0_wd_in[366]
  PIN rw0_wd_in[367]
    DIRECTION INPUT ;
    USE SIGNAL ;
    SHAPE ABUTMENT ;
    PORT
      LAYER M3 ;
      RECT 0 103.075 0.07 103.145 ;
    END
  END rw0_wd_in[367]
  PIN rw0_wd_in[368]
    DIRECTION INPUT ;
    USE SIGNAL ;
    SHAPE ABUTMENT ;
    PORT
      LAYER M3 ;
      RECT 0 103.355 0.07 103.425 ;
    END
  END rw0_wd_in[368]
  PIN rw0_wd_in[369]
    DIRECTION INPUT ;
    USE SIGNAL ;
    SHAPE ABUTMENT ;
    PORT
      LAYER M3 ;
      RECT 0 103.635 0.07 103.705 ;
    END
  END rw0_wd_in[369]
  PIN rw0_wd_in[370]
    DIRECTION INPUT ;
    USE SIGNAL ;
    SHAPE ABUTMENT ;
    PORT
      LAYER M3 ;
      RECT 0 103.915 0.07 103.985 ;
    END
  END rw0_wd_in[370]
  PIN rw0_wd_in[371]
    DIRECTION INPUT ;
    USE SIGNAL ;
    SHAPE ABUTMENT ;
    PORT
      LAYER M3 ;
      RECT 0 104.195 0.07 104.265 ;
    END
  END rw0_wd_in[371]
  PIN rw0_wd_in[372]
    DIRECTION INPUT ;
    USE SIGNAL ;
    SHAPE ABUTMENT ;
    PORT
      LAYER M3 ;
      RECT 0 104.475 0.07 104.545 ;
    END
  END rw0_wd_in[372]
  PIN rw0_wd_in[373]
    DIRECTION INPUT ;
    USE SIGNAL ;
    SHAPE ABUTMENT ;
    PORT
      LAYER M3 ;
      RECT 0 104.755 0.07 104.825 ;
    END
  END rw0_wd_in[373]
  PIN rw0_wd_in[374]
    DIRECTION INPUT ;
    USE SIGNAL ;
    SHAPE ABUTMENT ;
    PORT
      LAYER M3 ;
      RECT 0 105.035 0.07 105.105 ;
    END
  END rw0_wd_in[374]
  PIN rw0_wd_in[375]
    DIRECTION INPUT ;
    USE SIGNAL ;
    SHAPE ABUTMENT ;
    PORT
      LAYER M3 ;
      RECT 0 105.315 0.07 105.385 ;
    END
  END rw0_wd_in[375]
  PIN rw0_wd_in[376]
    DIRECTION INPUT ;
    USE SIGNAL ;
    SHAPE ABUTMENT ;
    PORT
      LAYER M3 ;
      RECT 0 105.595 0.07 105.665 ;
    END
  END rw0_wd_in[376]
  PIN rw0_wd_in[377]
    DIRECTION INPUT ;
    USE SIGNAL ;
    SHAPE ABUTMENT ;
    PORT
      LAYER M3 ;
      RECT 0 105.875 0.07 105.945 ;
    END
  END rw0_wd_in[377]
  PIN rw0_wd_in[378]
    DIRECTION INPUT ;
    USE SIGNAL ;
    SHAPE ABUTMENT ;
    PORT
      LAYER M3 ;
      RECT 0 106.155 0.07 106.225 ;
    END
  END rw0_wd_in[378]
  PIN rw0_wd_in[379]
    DIRECTION INPUT ;
    USE SIGNAL ;
    SHAPE ABUTMENT ;
    PORT
      LAYER M3 ;
      RECT 0 106.435 0.07 106.505 ;
    END
  END rw0_wd_in[379]
  PIN rw0_wd_in[380]
    DIRECTION INPUT ;
    USE SIGNAL ;
    SHAPE ABUTMENT ;
    PORT
      LAYER M3 ;
      RECT 0 106.715 0.07 106.785 ;
    END
  END rw0_wd_in[380]
  PIN rw0_wd_in[381]
    DIRECTION INPUT ;
    USE SIGNAL ;
    SHAPE ABUTMENT ;
    PORT
      LAYER M3 ;
      RECT 0 106.995 0.07 107.065 ;
    END
  END rw0_wd_in[381]
  PIN rw0_wd_in[382]
    DIRECTION INPUT ;
    USE SIGNAL ;
    SHAPE ABUTMENT ;
    PORT
      LAYER M3 ;
      RECT 0 107.275 0.07 107.345 ;
    END
  END rw0_wd_in[382]
  PIN rw0_wd_in[383]
    DIRECTION INPUT ;
    USE SIGNAL ;
    SHAPE ABUTMENT ;
    PORT
      LAYER M3 ;
      RECT 0 107.555 0.07 107.625 ;
    END
  END rw0_wd_in[383]
  PIN rw0_wd_in[384]
    DIRECTION INPUT ;
    USE SIGNAL ;
    SHAPE ABUTMENT ;
    PORT
      LAYER M3 ;
      RECT 0 107.835 0.07 107.905 ;
    END
  END rw0_wd_in[384]
  PIN rw0_wd_in[385]
    DIRECTION INPUT ;
    USE SIGNAL ;
    SHAPE ABUTMENT ;
    PORT
      LAYER M3 ;
      RECT 0 108.115 0.07 108.185 ;
    END
  END rw0_wd_in[385]
  PIN rw0_wd_in[386]
    DIRECTION INPUT ;
    USE SIGNAL ;
    SHAPE ABUTMENT ;
    PORT
      LAYER M3 ;
      RECT 0 108.395 0.07 108.465 ;
    END
  END rw0_wd_in[386]
  PIN rw0_wd_in[387]
    DIRECTION INPUT ;
    USE SIGNAL ;
    SHAPE ABUTMENT ;
    PORT
      LAYER M3 ;
      RECT 0 108.675 0.07 108.745 ;
    END
  END rw0_wd_in[387]
  PIN rw0_wd_in[388]
    DIRECTION INPUT ;
    USE SIGNAL ;
    SHAPE ABUTMENT ;
    PORT
      LAYER M3 ;
      RECT 0 108.955 0.07 109.025 ;
    END
  END rw0_wd_in[388]
  PIN rw0_wd_in[389]
    DIRECTION INPUT ;
    USE SIGNAL ;
    SHAPE ABUTMENT ;
    PORT
      LAYER M3 ;
      RECT 0 109.235 0.07 109.305 ;
    END
  END rw0_wd_in[389]
  PIN rw0_wd_in[390]
    DIRECTION INPUT ;
    USE SIGNAL ;
    SHAPE ABUTMENT ;
    PORT
      LAYER M3 ;
      RECT 0 109.515 0.07 109.585 ;
    END
  END rw0_wd_in[390]
  PIN rw0_wd_in[391]
    DIRECTION INPUT ;
    USE SIGNAL ;
    SHAPE ABUTMENT ;
    PORT
      LAYER M3 ;
      RECT 0 109.795 0.07 109.865 ;
    END
  END rw0_wd_in[391]
  PIN rw0_wd_in[392]
    DIRECTION INPUT ;
    USE SIGNAL ;
    SHAPE ABUTMENT ;
    PORT
      LAYER M3 ;
      RECT 0 110.075 0.07 110.145 ;
    END
  END rw0_wd_in[392]
  PIN rw0_wd_in[393]
    DIRECTION INPUT ;
    USE SIGNAL ;
    SHAPE ABUTMENT ;
    PORT
      LAYER M3 ;
      RECT 0 110.355 0.07 110.425 ;
    END
  END rw0_wd_in[393]
  PIN rw0_wd_in[394]
    DIRECTION INPUT ;
    USE SIGNAL ;
    SHAPE ABUTMENT ;
    PORT
      LAYER M3 ;
      RECT 0 110.635 0.07 110.705 ;
    END
  END rw0_wd_in[394]
  PIN rw0_wd_in[395]
    DIRECTION INPUT ;
    USE SIGNAL ;
    SHAPE ABUTMENT ;
    PORT
      LAYER M3 ;
      RECT 0 110.915 0.07 110.985 ;
    END
  END rw0_wd_in[395]
  PIN rw0_wd_in[396]
    DIRECTION INPUT ;
    USE SIGNAL ;
    SHAPE ABUTMENT ;
    PORT
      LAYER M3 ;
      RECT 0 111.195 0.07 111.265 ;
    END
  END rw0_wd_in[396]
  PIN rw0_wd_in[397]
    DIRECTION INPUT ;
    USE SIGNAL ;
    SHAPE ABUTMENT ;
    PORT
      LAYER M3 ;
      RECT 0 111.475 0.07 111.545 ;
    END
  END rw0_wd_in[397]
  PIN rw0_wd_in[398]
    DIRECTION INPUT ;
    USE SIGNAL ;
    SHAPE ABUTMENT ;
    PORT
      LAYER M3 ;
      RECT 0 111.755 0.07 111.825 ;
    END
  END rw0_wd_in[398]
  PIN rw0_wd_in[399]
    DIRECTION INPUT ;
    USE SIGNAL ;
    SHAPE ABUTMENT ;
    PORT
      LAYER M3 ;
      RECT 0 112.035 0.07 112.105 ;
    END
  END rw0_wd_in[399]
  PIN rw0_wd_in[400]
    DIRECTION INPUT ;
    USE SIGNAL ;
    SHAPE ABUTMENT ;
    PORT
      LAYER M3 ;
      RECT 0 112.315 0.07 112.385 ;
    END
  END rw0_wd_in[400]
  PIN rw0_wd_in[401]
    DIRECTION INPUT ;
    USE SIGNAL ;
    SHAPE ABUTMENT ;
    PORT
      LAYER M3 ;
      RECT 0 112.595 0.07 112.665 ;
    END
  END rw0_wd_in[401]
  PIN rw0_wd_in[402]
    DIRECTION INPUT ;
    USE SIGNAL ;
    SHAPE ABUTMENT ;
    PORT
      LAYER M3 ;
      RECT 0 112.875 0.07 112.945 ;
    END
  END rw0_wd_in[402]
  PIN rw0_wd_in[403]
    DIRECTION INPUT ;
    USE SIGNAL ;
    SHAPE ABUTMENT ;
    PORT
      LAYER M3 ;
      RECT 0 113.155 0.07 113.225 ;
    END
  END rw0_wd_in[403]
  PIN rw0_wd_in[404]
    DIRECTION INPUT ;
    USE SIGNAL ;
    SHAPE ABUTMENT ;
    PORT
      LAYER M3 ;
      RECT 0 113.435 0.07 113.505 ;
    END
  END rw0_wd_in[404]
  PIN rw0_wd_in[405]
    DIRECTION INPUT ;
    USE SIGNAL ;
    SHAPE ABUTMENT ;
    PORT
      LAYER M3 ;
      RECT 0 113.715 0.07 113.785 ;
    END
  END rw0_wd_in[405]
  PIN rw0_wd_in[406]
    DIRECTION INPUT ;
    USE SIGNAL ;
    SHAPE ABUTMENT ;
    PORT
      LAYER M3 ;
      RECT 0 113.995 0.07 114.065 ;
    END
  END rw0_wd_in[406]
  PIN rw0_wd_in[407]
    DIRECTION INPUT ;
    USE SIGNAL ;
    SHAPE ABUTMENT ;
    PORT
      LAYER M3 ;
      RECT 0 114.275 0.07 114.345 ;
    END
  END rw0_wd_in[407]
  PIN rw0_wd_in[408]
    DIRECTION INPUT ;
    USE SIGNAL ;
    SHAPE ABUTMENT ;
    PORT
      LAYER M3 ;
      RECT 0 114.555 0.07 114.625 ;
    END
  END rw0_wd_in[408]
  PIN rw0_wd_in[409]
    DIRECTION INPUT ;
    USE SIGNAL ;
    SHAPE ABUTMENT ;
    PORT
      LAYER M3 ;
      RECT 0 114.835 0.07 114.905 ;
    END
  END rw0_wd_in[409]
  PIN rw0_wd_in[410]
    DIRECTION INPUT ;
    USE SIGNAL ;
    SHAPE ABUTMENT ;
    PORT
      LAYER M3 ;
      RECT 0 115.115 0.07 115.185 ;
    END
  END rw0_wd_in[410]
  PIN rw0_wd_in[411]
    DIRECTION INPUT ;
    USE SIGNAL ;
    SHAPE ABUTMENT ;
    PORT
      LAYER M3 ;
      RECT 0 115.395 0.07 115.465 ;
    END
  END rw0_wd_in[411]
  PIN rw0_wd_in[412]
    DIRECTION INPUT ;
    USE SIGNAL ;
    SHAPE ABUTMENT ;
    PORT
      LAYER M3 ;
      RECT 0 115.675 0.07 115.745 ;
    END
  END rw0_wd_in[412]
  PIN rw0_wd_in[413]
    DIRECTION INPUT ;
    USE SIGNAL ;
    SHAPE ABUTMENT ;
    PORT
      LAYER M3 ;
      RECT 0 115.955 0.07 116.025 ;
    END
  END rw0_wd_in[413]
  PIN rw0_wd_in[414]
    DIRECTION INPUT ;
    USE SIGNAL ;
    SHAPE ABUTMENT ;
    PORT
      LAYER M3 ;
      RECT 0 116.235 0.07 116.305 ;
    END
  END rw0_wd_in[414]
  PIN rw0_wd_in[415]
    DIRECTION INPUT ;
    USE SIGNAL ;
    SHAPE ABUTMENT ;
    PORT
      LAYER M3 ;
      RECT 0 116.515 0.07 116.585 ;
    END
  END rw0_wd_in[415]
  PIN rw0_wd_in[416]
    DIRECTION INPUT ;
    USE SIGNAL ;
    SHAPE ABUTMENT ;
    PORT
      LAYER M3 ;
      RECT 0 116.795 0.07 116.865 ;
    END
  END rw0_wd_in[416]
  PIN rw0_wd_in[417]
    DIRECTION INPUT ;
    USE SIGNAL ;
    SHAPE ABUTMENT ;
    PORT
      LAYER M3 ;
      RECT 0 117.075 0.07 117.145 ;
    END
  END rw0_wd_in[417]
  PIN rw0_wd_in[418]
    DIRECTION INPUT ;
    USE SIGNAL ;
    SHAPE ABUTMENT ;
    PORT
      LAYER M3 ;
      RECT 0 117.355 0.07 117.425 ;
    END
  END rw0_wd_in[418]
  PIN rw0_wd_in[419]
    DIRECTION INPUT ;
    USE SIGNAL ;
    SHAPE ABUTMENT ;
    PORT
      LAYER M3 ;
      RECT 0 117.635 0.07 117.705 ;
    END
  END rw0_wd_in[419]
  PIN rw0_wd_in[420]
    DIRECTION INPUT ;
    USE SIGNAL ;
    SHAPE ABUTMENT ;
    PORT
      LAYER M3 ;
      RECT 0 117.915 0.07 117.985 ;
    END
  END rw0_wd_in[420]
  PIN rw0_wd_in[421]
    DIRECTION INPUT ;
    USE SIGNAL ;
    SHAPE ABUTMENT ;
    PORT
      LAYER M3 ;
      RECT 0 118.195 0.07 118.265 ;
    END
  END rw0_wd_in[421]
  PIN rw0_wd_in[422]
    DIRECTION INPUT ;
    USE SIGNAL ;
    SHAPE ABUTMENT ;
    PORT
      LAYER M3 ;
      RECT 0 118.475 0.07 118.545 ;
    END
  END rw0_wd_in[422]
  PIN rw0_wd_in[423]
    DIRECTION INPUT ;
    USE SIGNAL ;
    SHAPE ABUTMENT ;
    PORT
      LAYER M3 ;
      RECT 0 118.755 0.07 118.825 ;
    END
  END rw0_wd_in[423]
  PIN rw0_wd_in[424]
    DIRECTION INPUT ;
    USE SIGNAL ;
    SHAPE ABUTMENT ;
    PORT
      LAYER M3 ;
      RECT 0 119.035 0.07 119.105 ;
    END
  END rw0_wd_in[424]
  PIN rw0_wd_in[425]
    DIRECTION INPUT ;
    USE SIGNAL ;
    SHAPE ABUTMENT ;
    PORT
      LAYER M3 ;
      RECT 0 119.315 0.07 119.385 ;
    END
  END rw0_wd_in[425]
  PIN rw0_wd_in[426]
    DIRECTION INPUT ;
    USE SIGNAL ;
    SHAPE ABUTMENT ;
    PORT
      LAYER M3 ;
      RECT 0 119.595 0.07 119.665 ;
    END
  END rw0_wd_in[426]
  PIN rw0_wd_in[427]
    DIRECTION INPUT ;
    USE SIGNAL ;
    SHAPE ABUTMENT ;
    PORT
      LAYER M3 ;
      RECT 0 119.875 0.07 119.945 ;
    END
  END rw0_wd_in[427]
  PIN rw0_wd_in[428]
    DIRECTION INPUT ;
    USE SIGNAL ;
    SHAPE ABUTMENT ;
    PORT
      LAYER M3 ;
      RECT 0 120.155 0.07 120.225 ;
    END
  END rw0_wd_in[428]
  PIN rw0_wd_in[429]
    DIRECTION INPUT ;
    USE SIGNAL ;
    SHAPE ABUTMENT ;
    PORT
      LAYER M3 ;
      RECT 0 120.435 0.07 120.505 ;
    END
  END rw0_wd_in[429]
  PIN rw0_wd_in[430]
    DIRECTION INPUT ;
    USE SIGNAL ;
    SHAPE ABUTMENT ;
    PORT
      LAYER M3 ;
      RECT 0 120.715 0.07 120.785 ;
    END
  END rw0_wd_in[430]
  PIN rw0_wd_in[431]
    DIRECTION INPUT ;
    USE SIGNAL ;
    SHAPE ABUTMENT ;
    PORT
      LAYER M3 ;
      RECT 0 120.995 0.07 121.065 ;
    END
  END rw0_wd_in[431]
  PIN rw0_wd_in[432]
    DIRECTION INPUT ;
    USE SIGNAL ;
    SHAPE ABUTMENT ;
    PORT
      LAYER M3 ;
      RECT 0 121.275 0.07 121.345 ;
    END
  END rw0_wd_in[432]
  PIN rw0_wd_in[433]
    DIRECTION INPUT ;
    USE SIGNAL ;
    SHAPE ABUTMENT ;
    PORT
      LAYER M3 ;
      RECT 0 121.555 0.07 121.625 ;
    END
  END rw0_wd_in[433]
  PIN rw0_wd_in[434]
    DIRECTION INPUT ;
    USE SIGNAL ;
    SHAPE ABUTMENT ;
    PORT
      LAYER M3 ;
      RECT 0 121.835 0.07 121.905 ;
    END
  END rw0_wd_in[434]
  PIN rw0_wd_in[435]
    DIRECTION INPUT ;
    USE SIGNAL ;
    SHAPE ABUTMENT ;
    PORT
      LAYER M3 ;
      RECT 0 122.115 0.07 122.185 ;
    END
  END rw0_wd_in[435]
  PIN rw0_wd_in[436]
    DIRECTION INPUT ;
    USE SIGNAL ;
    SHAPE ABUTMENT ;
    PORT
      LAYER M3 ;
      RECT 0 122.395 0.07 122.465 ;
    END
  END rw0_wd_in[436]
  PIN rw0_wd_in[437]
    DIRECTION INPUT ;
    USE SIGNAL ;
    SHAPE ABUTMENT ;
    PORT
      LAYER M3 ;
      RECT 0 122.675 0.07 122.745 ;
    END
  END rw0_wd_in[437]
  PIN rw0_wd_in[438]
    DIRECTION INPUT ;
    USE SIGNAL ;
    SHAPE ABUTMENT ;
    PORT
      LAYER M3 ;
      RECT 0 122.955 0.07 123.025 ;
    END
  END rw0_wd_in[438]
  PIN rw0_wd_in[439]
    DIRECTION INPUT ;
    USE SIGNAL ;
    SHAPE ABUTMENT ;
    PORT
      LAYER M3 ;
      RECT 0 123.235 0.07 123.305 ;
    END
  END rw0_wd_in[439]
  PIN rw0_wd_in[440]
    DIRECTION INPUT ;
    USE SIGNAL ;
    SHAPE ABUTMENT ;
    PORT
      LAYER M3 ;
      RECT 0 123.515 0.07 123.585 ;
    END
  END rw0_wd_in[440]
  PIN rw0_wd_in[441]
    DIRECTION INPUT ;
    USE SIGNAL ;
    SHAPE ABUTMENT ;
    PORT
      LAYER M3 ;
      RECT 0 123.795 0.07 123.865 ;
    END
  END rw0_wd_in[441]
  PIN rw0_wd_in[442]
    DIRECTION INPUT ;
    USE SIGNAL ;
    SHAPE ABUTMENT ;
    PORT
      LAYER M3 ;
      RECT 0 124.075 0.07 124.145 ;
    END
  END rw0_wd_in[442]
  PIN rw0_wd_in[443]
    DIRECTION INPUT ;
    USE SIGNAL ;
    SHAPE ABUTMENT ;
    PORT
      LAYER M3 ;
      RECT 0 124.355 0.07 124.425 ;
    END
  END rw0_wd_in[443]
  PIN rw0_wd_in[444]
    DIRECTION INPUT ;
    USE SIGNAL ;
    SHAPE ABUTMENT ;
    PORT
      LAYER M3 ;
      RECT 0 124.635 0.07 124.705 ;
    END
  END rw0_wd_in[444]
  PIN rw0_wd_in[445]
    DIRECTION INPUT ;
    USE SIGNAL ;
    SHAPE ABUTMENT ;
    PORT
      LAYER M3 ;
      RECT 0 124.915 0.07 124.985 ;
    END
  END rw0_wd_in[445]
  PIN rw0_wd_in[446]
    DIRECTION INPUT ;
    USE SIGNAL ;
    SHAPE ABUTMENT ;
    PORT
      LAYER M3 ;
      RECT 0 125.195 0.07 125.265 ;
    END
  END rw0_wd_in[446]
  PIN rw0_wd_in[447]
    DIRECTION INPUT ;
    USE SIGNAL ;
    SHAPE ABUTMENT ;
    PORT
      LAYER M3 ;
      RECT 0 125.475 0.07 125.545 ;
    END
  END rw0_wd_in[447]
  PIN rw0_wd_in[448]
    DIRECTION INPUT ;
    USE SIGNAL ;
    SHAPE ABUTMENT ;
    PORT
      LAYER M3 ;
      RECT 0 125.755 0.07 125.825 ;
    END
  END rw0_wd_in[448]
  PIN rw0_wd_in[449]
    DIRECTION INPUT ;
    USE SIGNAL ;
    SHAPE ABUTMENT ;
    PORT
      LAYER M3 ;
      RECT 0 126.035 0.07 126.105 ;
    END
  END rw0_wd_in[449]
  PIN rw0_wd_in[450]
    DIRECTION INPUT ;
    USE SIGNAL ;
    SHAPE ABUTMENT ;
    PORT
      LAYER M3 ;
      RECT 0 126.315 0.07 126.385 ;
    END
  END rw0_wd_in[450]
  PIN rw0_wd_in[451]
    DIRECTION INPUT ;
    USE SIGNAL ;
    SHAPE ABUTMENT ;
    PORT
      LAYER M3 ;
      RECT 0 126.595 0.07 126.665 ;
    END
  END rw0_wd_in[451]
  PIN rw0_wd_in[452]
    DIRECTION INPUT ;
    USE SIGNAL ;
    SHAPE ABUTMENT ;
    PORT
      LAYER M3 ;
      RECT 0 126.875 0.07 126.945 ;
    END
  END rw0_wd_in[452]
  PIN rw0_wd_in[453]
    DIRECTION INPUT ;
    USE SIGNAL ;
    SHAPE ABUTMENT ;
    PORT
      LAYER M3 ;
      RECT 0 127.155 0.07 127.225 ;
    END
  END rw0_wd_in[453]
  PIN rw0_wd_in[454]
    DIRECTION INPUT ;
    USE SIGNAL ;
    SHAPE ABUTMENT ;
    PORT
      LAYER M3 ;
      RECT 0 127.435 0.07 127.505 ;
    END
  END rw0_wd_in[454]
  PIN rw0_wd_in[455]
    DIRECTION INPUT ;
    USE SIGNAL ;
    SHAPE ABUTMENT ;
    PORT
      LAYER M3 ;
      RECT 0 127.715 0.07 127.785 ;
    END
  END rw0_wd_in[455]
  PIN rw0_wd_in[456]
    DIRECTION INPUT ;
    USE SIGNAL ;
    SHAPE ABUTMENT ;
    PORT
      LAYER M3 ;
      RECT 0 127.995 0.07 128.065 ;
    END
  END rw0_wd_in[456]
  PIN rw0_wd_in[457]
    DIRECTION INPUT ;
    USE SIGNAL ;
    SHAPE ABUTMENT ;
    PORT
      LAYER M3 ;
      RECT 0 128.275 0.07 128.345 ;
    END
  END rw0_wd_in[457]
  PIN rw0_wd_in[458]
    DIRECTION INPUT ;
    USE SIGNAL ;
    SHAPE ABUTMENT ;
    PORT
      LAYER M3 ;
      RECT 0 128.555 0.07 128.625 ;
    END
  END rw0_wd_in[458]
  PIN rw0_wd_in[459]
    DIRECTION INPUT ;
    USE SIGNAL ;
    SHAPE ABUTMENT ;
    PORT
      LAYER M3 ;
      RECT 0 128.835 0.07 128.905 ;
    END
  END rw0_wd_in[459]
  PIN rw0_wd_in[460]
    DIRECTION INPUT ;
    USE SIGNAL ;
    SHAPE ABUTMENT ;
    PORT
      LAYER M3 ;
      RECT 0 129.115 0.07 129.185 ;
    END
  END rw0_wd_in[460]
  PIN rw0_wd_in[461]
    DIRECTION INPUT ;
    USE SIGNAL ;
    SHAPE ABUTMENT ;
    PORT
      LAYER M3 ;
      RECT 0 129.395 0.07 129.465 ;
    END
  END rw0_wd_in[461]
  PIN rw0_wd_in[462]
    DIRECTION INPUT ;
    USE SIGNAL ;
    SHAPE ABUTMENT ;
    PORT
      LAYER M3 ;
      RECT 0 129.675 0.07 129.745 ;
    END
  END rw0_wd_in[462]
  PIN rw0_wd_in[463]
    DIRECTION INPUT ;
    USE SIGNAL ;
    SHAPE ABUTMENT ;
    PORT
      LAYER M3 ;
      RECT 0 129.955 0.07 130.025 ;
    END
  END rw0_wd_in[463]
  PIN rw0_wd_in[464]
    DIRECTION INPUT ;
    USE SIGNAL ;
    SHAPE ABUTMENT ;
    PORT
      LAYER M3 ;
      RECT 0 130.235 0.07 130.305 ;
    END
  END rw0_wd_in[464]
  PIN rw0_wd_in[465]
    DIRECTION INPUT ;
    USE SIGNAL ;
    SHAPE ABUTMENT ;
    PORT
      LAYER M3 ;
      RECT 0 130.515 0.07 130.585 ;
    END
  END rw0_wd_in[465]
  PIN rw0_wd_in[466]
    DIRECTION INPUT ;
    USE SIGNAL ;
    SHAPE ABUTMENT ;
    PORT
      LAYER M3 ;
      RECT 0 130.795 0.07 130.865 ;
    END
  END rw0_wd_in[466]
  PIN rw0_wd_in[467]
    DIRECTION INPUT ;
    USE SIGNAL ;
    SHAPE ABUTMENT ;
    PORT
      LAYER M3 ;
      RECT 0 131.075 0.07 131.145 ;
    END
  END rw0_wd_in[467]
  PIN rw0_wd_in[468]
    DIRECTION INPUT ;
    USE SIGNAL ;
    SHAPE ABUTMENT ;
    PORT
      LAYER M3 ;
      RECT 0 131.355 0.07 131.425 ;
    END
  END rw0_wd_in[468]
  PIN rw0_wd_in[469]
    DIRECTION INPUT ;
    USE SIGNAL ;
    SHAPE ABUTMENT ;
    PORT
      LAYER M3 ;
      RECT 0 131.635 0.07 131.705 ;
    END
  END rw0_wd_in[469]
  PIN rw0_wd_in[470]
    DIRECTION INPUT ;
    USE SIGNAL ;
    SHAPE ABUTMENT ;
    PORT
      LAYER M3 ;
      RECT 0 131.915 0.07 131.985 ;
    END
  END rw0_wd_in[470]
  PIN rw0_wd_in[471]
    DIRECTION INPUT ;
    USE SIGNAL ;
    SHAPE ABUTMENT ;
    PORT
      LAYER M3 ;
      RECT 0 132.195 0.07 132.265 ;
    END
  END rw0_wd_in[471]
  PIN rw0_wd_in[472]
    DIRECTION INPUT ;
    USE SIGNAL ;
    SHAPE ABUTMENT ;
    PORT
      LAYER M3 ;
      RECT 0 132.475 0.07 132.545 ;
    END
  END rw0_wd_in[472]
  PIN rw0_wd_in[473]
    DIRECTION INPUT ;
    USE SIGNAL ;
    SHAPE ABUTMENT ;
    PORT
      LAYER M3 ;
      RECT 0 132.755 0.07 132.825 ;
    END
  END rw0_wd_in[473]
  PIN rw0_wd_in[474]
    DIRECTION INPUT ;
    USE SIGNAL ;
    SHAPE ABUTMENT ;
    PORT
      LAYER M3 ;
      RECT 0 133.035 0.07 133.105 ;
    END
  END rw0_wd_in[474]
  PIN rw0_wd_in[475]
    DIRECTION INPUT ;
    USE SIGNAL ;
    SHAPE ABUTMENT ;
    PORT
      LAYER M3 ;
      RECT 0 133.315 0.07 133.385 ;
    END
  END rw0_wd_in[475]
  PIN rw0_wd_in[476]
    DIRECTION INPUT ;
    USE SIGNAL ;
    SHAPE ABUTMENT ;
    PORT
      LAYER M3 ;
      RECT 0 133.595 0.07 133.665 ;
    END
  END rw0_wd_in[476]
  PIN rw0_wd_in[477]
    DIRECTION INPUT ;
    USE SIGNAL ;
    SHAPE ABUTMENT ;
    PORT
      LAYER M3 ;
      RECT 0 133.875 0.07 133.945 ;
    END
  END rw0_wd_in[477]
  PIN rw0_wd_in[478]
    DIRECTION INPUT ;
    USE SIGNAL ;
    SHAPE ABUTMENT ;
    PORT
      LAYER M3 ;
      RECT 0 134.155 0.07 134.225 ;
    END
  END rw0_wd_in[478]
  PIN rw0_wd_in[479]
    DIRECTION INPUT ;
    USE SIGNAL ;
    SHAPE ABUTMENT ;
    PORT
      LAYER M3 ;
      RECT 0 134.435 0.07 134.505 ;
    END
  END rw0_wd_in[479]
  PIN rw0_wd_in[480]
    DIRECTION INPUT ;
    USE SIGNAL ;
    SHAPE ABUTMENT ;
    PORT
      LAYER M3 ;
      RECT 0 134.715 0.07 134.785 ;
    END
  END rw0_wd_in[480]
  PIN rw0_wd_in[481]
    DIRECTION INPUT ;
    USE SIGNAL ;
    SHAPE ABUTMENT ;
    PORT
      LAYER M3 ;
      RECT 0 134.995 0.07 135.065 ;
    END
  END rw0_wd_in[481]
  PIN rw0_wd_in[482]
    DIRECTION INPUT ;
    USE SIGNAL ;
    SHAPE ABUTMENT ;
    PORT
      LAYER M3 ;
      RECT 0 135.275 0.07 135.345 ;
    END
  END rw0_wd_in[482]
  PIN rw0_wd_in[483]
    DIRECTION INPUT ;
    USE SIGNAL ;
    SHAPE ABUTMENT ;
    PORT
      LAYER M3 ;
      RECT 0 135.555 0.07 135.625 ;
    END
  END rw0_wd_in[483]
  PIN rw0_wd_in[484]
    DIRECTION INPUT ;
    USE SIGNAL ;
    SHAPE ABUTMENT ;
    PORT
      LAYER M3 ;
      RECT 0 135.835 0.07 135.905 ;
    END
  END rw0_wd_in[484]
  PIN rw0_wd_in[485]
    DIRECTION INPUT ;
    USE SIGNAL ;
    SHAPE ABUTMENT ;
    PORT
      LAYER M3 ;
      RECT 0 136.115 0.07 136.185 ;
    END
  END rw0_wd_in[485]
  PIN rw0_wd_in[486]
    DIRECTION INPUT ;
    USE SIGNAL ;
    SHAPE ABUTMENT ;
    PORT
      LAYER M3 ;
      RECT 0 136.395 0.07 136.465 ;
    END
  END rw0_wd_in[486]
  PIN rw0_wd_in[487]
    DIRECTION INPUT ;
    USE SIGNAL ;
    SHAPE ABUTMENT ;
    PORT
      LAYER M3 ;
      RECT 0 136.675 0.07 136.745 ;
    END
  END rw0_wd_in[487]
  PIN rw0_wd_in[488]
    DIRECTION INPUT ;
    USE SIGNAL ;
    SHAPE ABUTMENT ;
    PORT
      LAYER M3 ;
      RECT 0 136.955 0.07 137.025 ;
    END
  END rw0_wd_in[488]
  PIN rw0_wd_in[489]
    DIRECTION INPUT ;
    USE SIGNAL ;
    SHAPE ABUTMENT ;
    PORT
      LAYER M3 ;
      RECT 0 137.235 0.07 137.305 ;
    END
  END rw0_wd_in[489]
  PIN rw0_wd_in[490]
    DIRECTION INPUT ;
    USE SIGNAL ;
    SHAPE ABUTMENT ;
    PORT
      LAYER M3 ;
      RECT 0 137.515 0.07 137.585 ;
    END
  END rw0_wd_in[490]
  PIN rw0_wd_in[491]
    DIRECTION INPUT ;
    USE SIGNAL ;
    SHAPE ABUTMENT ;
    PORT
      LAYER M3 ;
      RECT 0 137.795 0.07 137.865 ;
    END
  END rw0_wd_in[491]
  PIN rw0_wd_in[492]
    DIRECTION INPUT ;
    USE SIGNAL ;
    SHAPE ABUTMENT ;
    PORT
      LAYER M3 ;
      RECT 0 138.075 0.07 138.145 ;
    END
  END rw0_wd_in[492]
  PIN rw0_wd_in[493]
    DIRECTION INPUT ;
    USE SIGNAL ;
    SHAPE ABUTMENT ;
    PORT
      LAYER M3 ;
      RECT 0 138.355 0.07 138.425 ;
    END
  END rw0_wd_in[493]
  PIN rw0_wd_in[494]
    DIRECTION INPUT ;
    USE SIGNAL ;
    SHAPE ABUTMENT ;
    PORT
      LAYER M3 ;
      RECT 0 138.635 0.07 138.705 ;
    END
  END rw0_wd_in[494]
  PIN rw0_wd_in[495]
    DIRECTION INPUT ;
    USE SIGNAL ;
    SHAPE ABUTMENT ;
    PORT
      LAYER M3 ;
      RECT 0 138.915 0.07 138.985 ;
    END
  END rw0_wd_in[495]
  PIN rw0_wd_in[496]
    DIRECTION INPUT ;
    USE SIGNAL ;
    SHAPE ABUTMENT ;
    PORT
      LAYER M3 ;
      RECT 0 139.195 0.07 139.265 ;
    END
  END rw0_wd_in[496]
  PIN rw0_wd_in[497]
    DIRECTION INPUT ;
    USE SIGNAL ;
    SHAPE ABUTMENT ;
    PORT
      LAYER M3 ;
      RECT 0 139.475 0.07 139.545 ;
    END
  END rw0_wd_in[497]
  PIN rw0_wd_in[498]
    DIRECTION INPUT ;
    USE SIGNAL ;
    SHAPE ABUTMENT ;
    PORT
      LAYER M3 ;
      RECT 0 139.755 0.07 139.825 ;
    END
  END rw0_wd_in[498]
  PIN rw0_wd_in[499]
    DIRECTION INPUT ;
    USE SIGNAL ;
    SHAPE ABUTMENT ;
    PORT
      LAYER M3 ;
      RECT 0 140.035 0.07 140.105 ;
    END
  END rw0_wd_in[499]
  PIN rw0_wd_in[500]
    DIRECTION INPUT ;
    USE SIGNAL ;
    SHAPE ABUTMENT ;
    PORT
      LAYER M3 ;
      RECT 0 140.315 0.07 140.385 ;
    END
  END rw0_wd_in[500]
  PIN rw0_wd_in[501]
    DIRECTION INPUT ;
    USE SIGNAL ;
    SHAPE ABUTMENT ;
    PORT
      LAYER M3 ;
      RECT 0 140.595 0.07 140.665 ;
    END
  END rw0_wd_in[501]
  PIN rw0_wd_in[502]
    DIRECTION INPUT ;
    USE SIGNAL ;
    SHAPE ABUTMENT ;
    PORT
      LAYER M3 ;
      RECT 0 140.875 0.07 140.945 ;
    END
  END rw0_wd_in[502]
  PIN rw0_wd_in[503]
    DIRECTION INPUT ;
    USE SIGNAL ;
    SHAPE ABUTMENT ;
    PORT
      LAYER M3 ;
      RECT 0 141.155 0.07 141.225 ;
    END
  END rw0_wd_in[503]
  PIN rw0_wd_in[504]
    DIRECTION INPUT ;
    USE SIGNAL ;
    SHAPE ABUTMENT ;
    PORT
      LAYER M3 ;
      RECT 0 141.435 0.07 141.505 ;
    END
  END rw0_wd_in[504]
  PIN rw0_wd_in[505]
    DIRECTION INPUT ;
    USE SIGNAL ;
    SHAPE ABUTMENT ;
    PORT
      LAYER M3 ;
      RECT 0 141.715 0.07 141.785 ;
    END
  END rw0_wd_in[505]
  PIN rw0_wd_in[506]
    DIRECTION INPUT ;
    USE SIGNAL ;
    SHAPE ABUTMENT ;
    PORT
      LAYER M3 ;
      RECT 0 141.995 0.07 142.065 ;
    END
  END rw0_wd_in[506]
  PIN rw0_wd_in[507]
    DIRECTION INPUT ;
    USE SIGNAL ;
    SHAPE ABUTMENT ;
    PORT
      LAYER M3 ;
      RECT 0 142.275 0.07 142.345 ;
    END
  END rw0_wd_in[507]
  PIN rw0_wd_in[508]
    DIRECTION INPUT ;
    USE SIGNAL ;
    SHAPE ABUTMENT ;
    PORT
      LAYER M3 ;
      RECT 0 142.555 0.07 142.625 ;
    END
  END rw0_wd_in[508]
  PIN rw0_wd_in[509]
    DIRECTION INPUT ;
    USE SIGNAL ;
    SHAPE ABUTMENT ;
    PORT
      LAYER M3 ;
      RECT 0 142.835 0.07 142.905 ;
    END
  END rw0_wd_in[509]
  PIN rw0_wd_in[510]
    DIRECTION INPUT ;
    USE SIGNAL ;
    SHAPE ABUTMENT ;
    PORT
      LAYER M3 ;
      RECT 0 143.115 0.07 143.185 ;
    END
  END rw0_wd_in[510]
  PIN rw0_wd_in[511]
    DIRECTION INPUT ;
    USE SIGNAL ;
    SHAPE ABUTMENT ;
    PORT
      LAYER M3 ;
      RECT 0 143.395 0.07 143.465 ;
    END
  END rw0_wd_in[511]
  PIN rw0_rd_out[0]
    DIRECTION OUTPUT ;
    USE SIGNAL ;
    SHAPE ABUTMENT ;
    PORT
      LAYER M3 ;
      RECT 0 143.675 0.07 143.745 ;
    END
  END rw0_rd_out[0]
  PIN rw0_rd_out[1]
    DIRECTION OUTPUT ;
    USE SIGNAL ;
    SHAPE ABUTMENT ;
    PORT
      LAYER M3 ;
      RECT 0 143.955 0.07 144.025 ;
    END
  END rw0_rd_out[1]
  PIN rw0_rd_out[2]
    DIRECTION OUTPUT ;
    USE SIGNAL ;
    SHAPE ABUTMENT ;
    PORT
      LAYER M3 ;
      RECT 0 144.235 0.07 144.305 ;
    END
  END rw0_rd_out[2]
  PIN rw0_rd_out[3]
    DIRECTION OUTPUT ;
    USE SIGNAL ;
    SHAPE ABUTMENT ;
    PORT
      LAYER M3 ;
      RECT 0 144.515 0.07 144.585 ;
    END
  END rw0_rd_out[3]
  PIN rw0_rd_out[4]
    DIRECTION OUTPUT ;
    USE SIGNAL ;
    SHAPE ABUTMENT ;
    PORT
      LAYER M3 ;
      RECT 0 144.795 0.07 144.865 ;
    END
  END rw0_rd_out[4]
  PIN rw0_rd_out[5]
    DIRECTION OUTPUT ;
    USE SIGNAL ;
    SHAPE ABUTMENT ;
    PORT
      LAYER M3 ;
      RECT 0 145.075 0.07 145.145 ;
    END
  END rw0_rd_out[5]
  PIN rw0_rd_out[6]
    DIRECTION OUTPUT ;
    USE SIGNAL ;
    SHAPE ABUTMENT ;
    PORT
      LAYER M3 ;
      RECT 0 145.355 0.07 145.425 ;
    END
  END rw0_rd_out[6]
  PIN rw0_rd_out[7]
    DIRECTION OUTPUT ;
    USE SIGNAL ;
    SHAPE ABUTMENT ;
    PORT
      LAYER M3 ;
      RECT 0 145.635 0.07 145.705 ;
    END
  END rw0_rd_out[7]
  PIN rw0_rd_out[8]
    DIRECTION OUTPUT ;
    USE SIGNAL ;
    SHAPE ABUTMENT ;
    PORT
      LAYER M3 ;
      RECT 0 145.915 0.07 145.985 ;
    END
  END rw0_rd_out[8]
  PIN rw0_rd_out[9]
    DIRECTION OUTPUT ;
    USE SIGNAL ;
    SHAPE ABUTMENT ;
    PORT
      LAYER M3 ;
      RECT 0 146.195 0.07 146.265 ;
    END
  END rw0_rd_out[9]
  PIN rw0_rd_out[10]
    DIRECTION OUTPUT ;
    USE SIGNAL ;
    SHAPE ABUTMENT ;
    PORT
      LAYER M3 ;
      RECT 0 146.475 0.07 146.545 ;
    END
  END rw0_rd_out[10]
  PIN rw0_rd_out[11]
    DIRECTION OUTPUT ;
    USE SIGNAL ;
    SHAPE ABUTMENT ;
    PORT
      LAYER M3 ;
      RECT 0 146.755 0.07 146.825 ;
    END
  END rw0_rd_out[11]
  PIN rw0_rd_out[12]
    DIRECTION OUTPUT ;
    USE SIGNAL ;
    SHAPE ABUTMENT ;
    PORT
      LAYER M3 ;
      RECT 0 147.035 0.07 147.105 ;
    END
  END rw0_rd_out[12]
  PIN rw0_rd_out[13]
    DIRECTION OUTPUT ;
    USE SIGNAL ;
    SHAPE ABUTMENT ;
    PORT
      LAYER M3 ;
      RECT 0 147.315 0.07 147.385 ;
    END
  END rw0_rd_out[13]
  PIN rw0_rd_out[14]
    DIRECTION OUTPUT ;
    USE SIGNAL ;
    SHAPE ABUTMENT ;
    PORT
      LAYER M3 ;
      RECT 0 147.595 0.07 147.665 ;
    END
  END rw0_rd_out[14]
  PIN rw0_rd_out[15]
    DIRECTION OUTPUT ;
    USE SIGNAL ;
    SHAPE ABUTMENT ;
    PORT
      LAYER M3 ;
      RECT 0 147.875 0.07 147.945 ;
    END
  END rw0_rd_out[15]
  PIN rw0_rd_out[16]
    DIRECTION OUTPUT ;
    USE SIGNAL ;
    SHAPE ABUTMENT ;
    PORT
      LAYER M3 ;
      RECT 0 148.155 0.07 148.225 ;
    END
  END rw0_rd_out[16]
  PIN rw0_rd_out[17]
    DIRECTION OUTPUT ;
    USE SIGNAL ;
    SHAPE ABUTMENT ;
    PORT
      LAYER M3 ;
      RECT 0 148.435 0.07 148.505 ;
    END
  END rw0_rd_out[17]
  PIN rw0_rd_out[18]
    DIRECTION OUTPUT ;
    USE SIGNAL ;
    SHAPE ABUTMENT ;
    PORT
      LAYER M3 ;
      RECT 0 148.715 0.07 148.785 ;
    END
  END rw0_rd_out[18]
  PIN rw0_rd_out[19]
    DIRECTION OUTPUT ;
    USE SIGNAL ;
    SHAPE ABUTMENT ;
    PORT
      LAYER M3 ;
      RECT 0 148.995 0.07 149.065 ;
    END
  END rw0_rd_out[19]
  PIN rw0_rd_out[20]
    DIRECTION OUTPUT ;
    USE SIGNAL ;
    SHAPE ABUTMENT ;
    PORT
      LAYER M3 ;
      RECT 0 149.275 0.07 149.345 ;
    END
  END rw0_rd_out[20]
  PIN rw0_rd_out[21]
    DIRECTION OUTPUT ;
    USE SIGNAL ;
    SHAPE ABUTMENT ;
    PORT
      LAYER M3 ;
      RECT 0 149.555 0.07 149.625 ;
    END
  END rw0_rd_out[21]
  PIN rw0_rd_out[22]
    DIRECTION OUTPUT ;
    USE SIGNAL ;
    SHAPE ABUTMENT ;
    PORT
      LAYER M3 ;
      RECT 0 149.835 0.07 149.905 ;
    END
  END rw0_rd_out[22]
  PIN rw0_rd_out[23]
    DIRECTION OUTPUT ;
    USE SIGNAL ;
    SHAPE ABUTMENT ;
    PORT
      LAYER M3 ;
      RECT 0 150.115 0.07 150.185 ;
    END
  END rw0_rd_out[23]
  PIN rw0_rd_out[24]
    DIRECTION OUTPUT ;
    USE SIGNAL ;
    SHAPE ABUTMENT ;
    PORT
      LAYER M3 ;
      RECT 0 150.395 0.07 150.465 ;
    END
  END rw0_rd_out[24]
  PIN rw0_rd_out[25]
    DIRECTION OUTPUT ;
    USE SIGNAL ;
    SHAPE ABUTMENT ;
    PORT
      LAYER M3 ;
      RECT 0 150.675 0.07 150.745 ;
    END
  END rw0_rd_out[25]
  PIN rw0_rd_out[26]
    DIRECTION OUTPUT ;
    USE SIGNAL ;
    SHAPE ABUTMENT ;
    PORT
      LAYER M3 ;
      RECT 0 150.955 0.07 151.025 ;
    END
  END rw0_rd_out[26]
  PIN rw0_rd_out[27]
    DIRECTION OUTPUT ;
    USE SIGNAL ;
    SHAPE ABUTMENT ;
    PORT
      LAYER M3 ;
      RECT 0 151.235 0.07 151.305 ;
    END
  END rw0_rd_out[27]
  PIN rw0_rd_out[28]
    DIRECTION OUTPUT ;
    USE SIGNAL ;
    SHAPE ABUTMENT ;
    PORT
      LAYER M3 ;
      RECT 0 151.515 0.07 151.585 ;
    END
  END rw0_rd_out[28]
  PIN rw0_rd_out[29]
    DIRECTION OUTPUT ;
    USE SIGNAL ;
    SHAPE ABUTMENT ;
    PORT
      LAYER M3 ;
      RECT 0 151.795 0.07 151.865 ;
    END
  END rw0_rd_out[29]
  PIN rw0_rd_out[30]
    DIRECTION OUTPUT ;
    USE SIGNAL ;
    SHAPE ABUTMENT ;
    PORT
      LAYER M3 ;
      RECT 0 152.075 0.07 152.145 ;
    END
  END rw0_rd_out[30]
  PIN rw0_rd_out[31]
    DIRECTION OUTPUT ;
    USE SIGNAL ;
    SHAPE ABUTMENT ;
    PORT
      LAYER M3 ;
      RECT 0 152.355 0.07 152.425 ;
    END
  END rw0_rd_out[31]
  PIN rw0_rd_out[32]
    DIRECTION OUTPUT ;
    USE SIGNAL ;
    SHAPE ABUTMENT ;
    PORT
      LAYER M3 ;
      RECT 0 152.635 0.07 152.705 ;
    END
  END rw0_rd_out[32]
  PIN rw0_rd_out[33]
    DIRECTION OUTPUT ;
    USE SIGNAL ;
    SHAPE ABUTMENT ;
    PORT
      LAYER M3 ;
      RECT 0 152.915 0.07 152.985 ;
    END
  END rw0_rd_out[33]
  PIN rw0_rd_out[34]
    DIRECTION OUTPUT ;
    USE SIGNAL ;
    SHAPE ABUTMENT ;
    PORT
      LAYER M3 ;
      RECT 0 153.195 0.07 153.265 ;
    END
  END rw0_rd_out[34]
  PIN rw0_rd_out[35]
    DIRECTION OUTPUT ;
    USE SIGNAL ;
    SHAPE ABUTMENT ;
    PORT
      LAYER M3 ;
      RECT 0 153.475 0.07 153.545 ;
    END
  END rw0_rd_out[35]
  PIN rw0_rd_out[36]
    DIRECTION OUTPUT ;
    USE SIGNAL ;
    SHAPE ABUTMENT ;
    PORT
      LAYER M3 ;
      RECT 0 153.755 0.07 153.825 ;
    END
  END rw0_rd_out[36]
  PIN rw0_rd_out[37]
    DIRECTION OUTPUT ;
    USE SIGNAL ;
    SHAPE ABUTMENT ;
    PORT
      LAYER M3 ;
      RECT 0 154.035 0.07 154.105 ;
    END
  END rw0_rd_out[37]
  PIN rw0_rd_out[38]
    DIRECTION OUTPUT ;
    USE SIGNAL ;
    SHAPE ABUTMENT ;
    PORT
      LAYER M3 ;
      RECT 0 154.315 0.07 154.385 ;
    END
  END rw0_rd_out[38]
  PIN rw0_rd_out[39]
    DIRECTION OUTPUT ;
    USE SIGNAL ;
    SHAPE ABUTMENT ;
    PORT
      LAYER M3 ;
      RECT 0 154.595 0.07 154.665 ;
    END
  END rw0_rd_out[39]
  PIN rw0_rd_out[40]
    DIRECTION OUTPUT ;
    USE SIGNAL ;
    SHAPE ABUTMENT ;
    PORT
      LAYER M3 ;
      RECT 0 154.875 0.07 154.945 ;
    END
  END rw0_rd_out[40]
  PIN rw0_rd_out[41]
    DIRECTION OUTPUT ;
    USE SIGNAL ;
    SHAPE ABUTMENT ;
    PORT
      LAYER M3 ;
      RECT 0 155.155 0.07 155.225 ;
    END
  END rw0_rd_out[41]
  PIN rw0_rd_out[42]
    DIRECTION OUTPUT ;
    USE SIGNAL ;
    SHAPE ABUTMENT ;
    PORT
      LAYER M3 ;
      RECT 0 155.435 0.07 155.505 ;
    END
  END rw0_rd_out[42]
  PIN rw0_rd_out[43]
    DIRECTION OUTPUT ;
    USE SIGNAL ;
    SHAPE ABUTMENT ;
    PORT
      LAYER M3 ;
      RECT 0 155.715 0.07 155.785 ;
    END
  END rw0_rd_out[43]
  PIN rw0_rd_out[44]
    DIRECTION OUTPUT ;
    USE SIGNAL ;
    SHAPE ABUTMENT ;
    PORT
      LAYER M3 ;
      RECT 0 155.995 0.07 156.065 ;
    END
  END rw0_rd_out[44]
  PIN rw0_rd_out[45]
    DIRECTION OUTPUT ;
    USE SIGNAL ;
    SHAPE ABUTMENT ;
    PORT
      LAYER M3 ;
      RECT 0 156.275 0.07 156.345 ;
    END
  END rw0_rd_out[45]
  PIN rw0_rd_out[46]
    DIRECTION OUTPUT ;
    USE SIGNAL ;
    SHAPE ABUTMENT ;
    PORT
      LAYER M3 ;
      RECT 0 156.555 0.07 156.625 ;
    END
  END rw0_rd_out[46]
  PIN rw0_rd_out[47]
    DIRECTION OUTPUT ;
    USE SIGNAL ;
    SHAPE ABUTMENT ;
    PORT
      LAYER M3 ;
      RECT 0 156.835 0.07 156.905 ;
    END
  END rw0_rd_out[47]
  PIN rw0_rd_out[48]
    DIRECTION OUTPUT ;
    USE SIGNAL ;
    SHAPE ABUTMENT ;
    PORT
      LAYER M3 ;
      RECT 0 157.115 0.07 157.185 ;
    END
  END rw0_rd_out[48]
  PIN rw0_rd_out[49]
    DIRECTION OUTPUT ;
    USE SIGNAL ;
    SHAPE ABUTMENT ;
    PORT
      LAYER M3 ;
      RECT 0 157.395 0.07 157.465 ;
    END
  END rw0_rd_out[49]
  PIN rw0_rd_out[50]
    DIRECTION OUTPUT ;
    USE SIGNAL ;
    SHAPE ABUTMENT ;
    PORT
      LAYER M3 ;
      RECT 0 157.675 0.07 157.745 ;
    END
  END rw0_rd_out[50]
  PIN rw0_rd_out[51]
    DIRECTION OUTPUT ;
    USE SIGNAL ;
    SHAPE ABUTMENT ;
    PORT
      LAYER M3 ;
      RECT 0 157.955 0.07 158.025 ;
    END
  END rw0_rd_out[51]
  PIN rw0_rd_out[52]
    DIRECTION OUTPUT ;
    USE SIGNAL ;
    SHAPE ABUTMENT ;
    PORT
      LAYER M3 ;
      RECT 0 158.235 0.07 158.305 ;
    END
  END rw0_rd_out[52]
  PIN rw0_rd_out[53]
    DIRECTION OUTPUT ;
    USE SIGNAL ;
    SHAPE ABUTMENT ;
    PORT
      LAYER M3 ;
      RECT 0 158.515 0.07 158.585 ;
    END
  END rw0_rd_out[53]
  PIN rw0_rd_out[54]
    DIRECTION OUTPUT ;
    USE SIGNAL ;
    SHAPE ABUTMENT ;
    PORT
      LAYER M3 ;
      RECT 0 158.795 0.07 158.865 ;
    END
  END rw0_rd_out[54]
  PIN rw0_rd_out[55]
    DIRECTION OUTPUT ;
    USE SIGNAL ;
    SHAPE ABUTMENT ;
    PORT
      LAYER M3 ;
      RECT 0 159.075 0.07 159.145 ;
    END
  END rw0_rd_out[55]
  PIN rw0_rd_out[56]
    DIRECTION OUTPUT ;
    USE SIGNAL ;
    SHAPE ABUTMENT ;
    PORT
      LAYER M3 ;
      RECT 0 159.355 0.07 159.425 ;
    END
  END rw0_rd_out[56]
  PIN rw0_rd_out[57]
    DIRECTION OUTPUT ;
    USE SIGNAL ;
    SHAPE ABUTMENT ;
    PORT
      LAYER M3 ;
      RECT 0 159.635 0.07 159.705 ;
    END
  END rw0_rd_out[57]
  PIN rw0_rd_out[58]
    DIRECTION OUTPUT ;
    USE SIGNAL ;
    SHAPE ABUTMENT ;
    PORT
      LAYER M3 ;
      RECT 0 159.915 0.07 159.985 ;
    END
  END rw0_rd_out[58]
  PIN rw0_rd_out[59]
    DIRECTION OUTPUT ;
    USE SIGNAL ;
    SHAPE ABUTMENT ;
    PORT
      LAYER M3 ;
      RECT 0 160.195 0.07 160.265 ;
    END
  END rw0_rd_out[59]
  PIN rw0_rd_out[60]
    DIRECTION OUTPUT ;
    USE SIGNAL ;
    SHAPE ABUTMENT ;
    PORT
      LAYER M3 ;
      RECT 0 160.475 0.07 160.545 ;
    END
  END rw0_rd_out[60]
  PIN rw0_rd_out[61]
    DIRECTION OUTPUT ;
    USE SIGNAL ;
    SHAPE ABUTMENT ;
    PORT
      LAYER M3 ;
      RECT 0 160.755 0.07 160.825 ;
    END
  END rw0_rd_out[61]
  PIN rw0_rd_out[62]
    DIRECTION OUTPUT ;
    USE SIGNAL ;
    SHAPE ABUTMENT ;
    PORT
      LAYER M3 ;
      RECT 0 161.035 0.07 161.105 ;
    END
  END rw0_rd_out[62]
  PIN rw0_rd_out[63]
    DIRECTION OUTPUT ;
    USE SIGNAL ;
    SHAPE ABUTMENT ;
    PORT
      LAYER M3 ;
      RECT 0 161.315 0.07 161.385 ;
    END
  END rw0_rd_out[63]
  PIN rw0_rd_out[64]
    DIRECTION OUTPUT ;
    USE SIGNAL ;
    SHAPE ABUTMENT ;
    PORT
      LAYER M3 ;
      RECT 0 161.595 0.07 161.665 ;
    END
  END rw0_rd_out[64]
  PIN rw0_rd_out[65]
    DIRECTION OUTPUT ;
    USE SIGNAL ;
    SHAPE ABUTMENT ;
    PORT
      LAYER M3 ;
      RECT 0 161.875 0.07 161.945 ;
    END
  END rw0_rd_out[65]
  PIN rw0_rd_out[66]
    DIRECTION OUTPUT ;
    USE SIGNAL ;
    SHAPE ABUTMENT ;
    PORT
      LAYER M3 ;
      RECT 0 162.155 0.07 162.225 ;
    END
  END rw0_rd_out[66]
  PIN rw0_rd_out[67]
    DIRECTION OUTPUT ;
    USE SIGNAL ;
    SHAPE ABUTMENT ;
    PORT
      LAYER M3 ;
      RECT 0 162.435 0.07 162.505 ;
    END
  END rw0_rd_out[67]
  PIN rw0_rd_out[68]
    DIRECTION OUTPUT ;
    USE SIGNAL ;
    SHAPE ABUTMENT ;
    PORT
      LAYER M3 ;
      RECT 0 162.715 0.07 162.785 ;
    END
  END rw0_rd_out[68]
  PIN rw0_rd_out[69]
    DIRECTION OUTPUT ;
    USE SIGNAL ;
    SHAPE ABUTMENT ;
    PORT
      LAYER M3 ;
      RECT 0 162.995 0.07 163.065 ;
    END
  END rw0_rd_out[69]
  PIN rw0_rd_out[70]
    DIRECTION OUTPUT ;
    USE SIGNAL ;
    SHAPE ABUTMENT ;
    PORT
      LAYER M3 ;
      RECT 0 163.275 0.07 163.345 ;
    END
  END rw0_rd_out[70]
  PIN rw0_rd_out[71]
    DIRECTION OUTPUT ;
    USE SIGNAL ;
    SHAPE ABUTMENT ;
    PORT
      LAYER M3 ;
      RECT 0 163.555 0.07 163.625 ;
    END
  END rw0_rd_out[71]
  PIN rw0_rd_out[72]
    DIRECTION OUTPUT ;
    USE SIGNAL ;
    SHAPE ABUTMENT ;
    PORT
      LAYER M3 ;
      RECT 0 163.835 0.07 163.905 ;
    END
  END rw0_rd_out[72]
  PIN rw0_rd_out[73]
    DIRECTION OUTPUT ;
    USE SIGNAL ;
    SHAPE ABUTMENT ;
    PORT
      LAYER M3 ;
      RECT 0 164.115 0.07 164.185 ;
    END
  END rw0_rd_out[73]
  PIN rw0_rd_out[74]
    DIRECTION OUTPUT ;
    USE SIGNAL ;
    SHAPE ABUTMENT ;
    PORT
      LAYER M3 ;
      RECT 0 164.395 0.07 164.465 ;
    END
  END rw0_rd_out[74]
  PIN rw0_rd_out[75]
    DIRECTION OUTPUT ;
    USE SIGNAL ;
    SHAPE ABUTMENT ;
    PORT
      LAYER M3 ;
      RECT 0 164.675 0.07 164.745 ;
    END
  END rw0_rd_out[75]
  PIN rw0_rd_out[76]
    DIRECTION OUTPUT ;
    USE SIGNAL ;
    SHAPE ABUTMENT ;
    PORT
      LAYER M3 ;
      RECT 0 164.955 0.07 165.025 ;
    END
  END rw0_rd_out[76]
  PIN rw0_rd_out[77]
    DIRECTION OUTPUT ;
    USE SIGNAL ;
    SHAPE ABUTMENT ;
    PORT
      LAYER M3 ;
      RECT 0 165.235 0.07 165.305 ;
    END
  END rw0_rd_out[77]
  PIN rw0_rd_out[78]
    DIRECTION OUTPUT ;
    USE SIGNAL ;
    SHAPE ABUTMENT ;
    PORT
      LAYER M3 ;
      RECT 0 165.515 0.07 165.585 ;
    END
  END rw0_rd_out[78]
  PIN rw0_rd_out[79]
    DIRECTION OUTPUT ;
    USE SIGNAL ;
    SHAPE ABUTMENT ;
    PORT
      LAYER M3 ;
      RECT 0 165.795 0.07 165.865 ;
    END
  END rw0_rd_out[79]
  PIN rw0_rd_out[80]
    DIRECTION OUTPUT ;
    USE SIGNAL ;
    SHAPE ABUTMENT ;
    PORT
      LAYER M3 ;
      RECT 0 166.075 0.07 166.145 ;
    END
  END rw0_rd_out[80]
  PIN rw0_rd_out[81]
    DIRECTION OUTPUT ;
    USE SIGNAL ;
    SHAPE ABUTMENT ;
    PORT
      LAYER M3 ;
      RECT 0 166.355 0.07 166.425 ;
    END
  END rw0_rd_out[81]
  PIN rw0_rd_out[82]
    DIRECTION OUTPUT ;
    USE SIGNAL ;
    SHAPE ABUTMENT ;
    PORT
      LAYER M3 ;
      RECT 0 166.635 0.07 166.705 ;
    END
  END rw0_rd_out[82]
  PIN rw0_rd_out[83]
    DIRECTION OUTPUT ;
    USE SIGNAL ;
    SHAPE ABUTMENT ;
    PORT
      LAYER M3 ;
      RECT 0 166.915 0.07 166.985 ;
    END
  END rw0_rd_out[83]
  PIN rw0_rd_out[84]
    DIRECTION OUTPUT ;
    USE SIGNAL ;
    SHAPE ABUTMENT ;
    PORT
      LAYER M3 ;
      RECT 0 167.195 0.07 167.265 ;
    END
  END rw0_rd_out[84]
  PIN rw0_rd_out[85]
    DIRECTION OUTPUT ;
    USE SIGNAL ;
    SHAPE ABUTMENT ;
    PORT
      LAYER M3 ;
      RECT 0 167.475 0.07 167.545 ;
    END
  END rw0_rd_out[85]
  PIN rw0_rd_out[86]
    DIRECTION OUTPUT ;
    USE SIGNAL ;
    SHAPE ABUTMENT ;
    PORT
      LAYER M3 ;
      RECT 0 167.755 0.07 167.825 ;
    END
  END rw0_rd_out[86]
  PIN rw0_rd_out[87]
    DIRECTION OUTPUT ;
    USE SIGNAL ;
    SHAPE ABUTMENT ;
    PORT
      LAYER M3 ;
      RECT 0 168.035 0.07 168.105 ;
    END
  END rw0_rd_out[87]
  PIN rw0_rd_out[88]
    DIRECTION OUTPUT ;
    USE SIGNAL ;
    SHAPE ABUTMENT ;
    PORT
      LAYER M3 ;
      RECT 0 168.315 0.07 168.385 ;
    END
  END rw0_rd_out[88]
  PIN rw0_rd_out[89]
    DIRECTION OUTPUT ;
    USE SIGNAL ;
    SHAPE ABUTMENT ;
    PORT
      LAYER M3 ;
      RECT 0 168.595 0.07 168.665 ;
    END
  END rw0_rd_out[89]
  PIN rw0_rd_out[90]
    DIRECTION OUTPUT ;
    USE SIGNAL ;
    SHAPE ABUTMENT ;
    PORT
      LAYER M3 ;
      RECT 0 168.875 0.07 168.945 ;
    END
  END rw0_rd_out[90]
  PIN rw0_rd_out[91]
    DIRECTION OUTPUT ;
    USE SIGNAL ;
    SHAPE ABUTMENT ;
    PORT
      LAYER M3 ;
      RECT 0 169.155 0.07 169.225 ;
    END
  END rw0_rd_out[91]
  PIN rw0_rd_out[92]
    DIRECTION OUTPUT ;
    USE SIGNAL ;
    SHAPE ABUTMENT ;
    PORT
      LAYER M3 ;
      RECT 0 169.435 0.07 169.505 ;
    END
  END rw0_rd_out[92]
  PIN rw0_rd_out[93]
    DIRECTION OUTPUT ;
    USE SIGNAL ;
    SHAPE ABUTMENT ;
    PORT
      LAYER M3 ;
      RECT 0 169.715 0.07 169.785 ;
    END
  END rw0_rd_out[93]
  PIN rw0_rd_out[94]
    DIRECTION OUTPUT ;
    USE SIGNAL ;
    SHAPE ABUTMENT ;
    PORT
      LAYER M3 ;
      RECT 0 169.995 0.07 170.065 ;
    END
  END rw0_rd_out[94]
  PIN rw0_rd_out[95]
    DIRECTION OUTPUT ;
    USE SIGNAL ;
    SHAPE ABUTMENT ;
    PORT
      LAYER M3 ;
      RECT 0 170.275 0.07 170.345 ;
    END
  END rw0_rd_out[95]
  PIN rw0_rd_out[96]
    DIRECTION OUTPUT ;
    USE SIGNAL ;
    SHAPE ABUTMENT ;
    PORT
      LAYER M3 ;
      RECT 0 170.555 0.07 170.625 ;
    END
  END rw0_rd_out[96]
  PIN rw0_rd_out[97]
    DIRECTION OUTPUT ;
    USE SIGNAL ;
    SHAPE ABUTMENT ;
    PORT
      LAYER M3 ;
      RECT 0 170.835 0.07 170.905 ;
    END
  END rw0_rd_out[97]
  PIN rw0_rd_out[98]
    DIRECTION OUTPUT ;
    USE SIGNAL ;
    SHAPE ABUTMENT ;
    PORT
      LAYER M3 ;
      RECT 0 171.115 0.07 171.185 ;
    END
  END rw0_rd_out[98]
  PIN rw0_rd_out[99]
    DIRECTION OUTPUT ;
    USE SIGNAL ;
    SHAPE ABUTMENT ;
    PORT
      LAYER M3 ;
      RECT 0 171.395 0.07 171.465 ;
    END
  END rw0_rd_out[99]
  PIN rw0_rd_out[100]
    DIRECTION OUTPUT ;
    USE SIGNAL ;
    SHAPE ABUTMENT ;
    PORT
      LAYER M3 ;
      RECT 0 171.675 0.07 171.745 ;
    END
  END rw0_rd_out[100]
  PIN rw0_rd_out[101]
    DIRECTION OUTPUT ;
    USE SIGNAL ;
    SHAPE ABUTMENT ;
    PORT
      LAYER M3 ;
      RECT 0 171.955 0.07 172.025 ;
    END
  END rw0_rd_out[101]
  PIN rw0_rd_out[102]
    DIRECTION OUTPUT ;
    USE SIGNAL ;
    SHAPE ABUTMENT ;
    PORT
      LAYER M3 ;
      RECT 0 172.235 0.07 172.305 ;
    END
  END rw0_rd_out[102]
  PIN rw0_rd_out[103]
    DIRECTION OUTPUT ;
    USE SIGNAL ;
    SHAPE ABUTMENT ;
    PORT
      LAYER M3 ;
      RECT 0 172.515 0.07 172.585 ;
    END
  END rw0_rd_out[103]
  PIN rw0_rd_out[104]
    DIRECTION OUTPUT ;
    USE SIGNAL ;
    SHAPE ABUTMENT ;
    PORT
      LAYER M3 ;
      RECT 0 172.795 0.07 172.865 ;
    END
  END rw0_rd_out[104]
  PIN rw0_rd_out[105]
    DIRECTION OUTPUT ;
    USE SIGNAL ;
    SHAPE ABUTMENT ;
    PORT
      LAYER M3 ;
      RECT 0 173.075 0.07 173.145 ;
    END
  END rw0_rd_out[105]
  PIN rw0_rd_out[106]
    DIRECTION OUTPUT ;
    USE SIGNAL ;
    SHAPE ABUTMENT ;
    PORT
      LAYER M3 ;
      RECT 0 173.355 0.07 173.425 ;
    END
  END rw0_rd_out[106]
  PIN rw0_rd_out[107]
    DIRECTION OUTPUT ;
    USE SIGNAL ;
    SHAPE ABUTMENT ;
    PORT
      LAYER M3 ;
      RECT 0 173.635 0.07 173.705 ;
    END
  END rw0_rd_out[107]
  PIN rw0_rd_out[108]
    DIRECTION OUTPUT ;
    USE SIGNAL ;
    SHAPE ABUTMENT ;
    PORT
      LAYER M3 ;
      RECT 0 173.915 0.07 173.985 ;
    END
  END rw0_rd_out[108]
  PIN rw0_rd_out[109]
    DIRECTION OUTPUT ;
    USE SIGNAL ;
    SHAPE ABUTMENT ;
    PORT
      LAYER M3 ;
      RECT 0 174.195 0.07 174.265 ;
    END
  END rw0_rd_out[109]
  PIN rw0_rd_out[110]
    DIRECTION OUTPUT ;
    USE SIGNAL ;
    SHAPE ABUTMENT ;
    PORT
      LAYER M3 ;
      RECT 0 174.475 0.07 174.545 ;
    END
  END rw0_rd_out[110]
  PIN rw0_rd_out[111]
    DIRECTION OUTPUT ;
    USE SIGNAL ;
    SHAPE ABUTMENT ;
    PORT
      LAYER M3 ;
      RECT 0 174.755 0.07 174.825 ;
    END
  END rw0_rd_out[111]
  PIN rw0_rd_out[112]
    DIRECTION OUTPUT ;
    USE SIGNAL ;
    SHAPE ABUTMENT ;
    PORT
      LAYER M3 ;
      RECT 0 175.035 0.07 175.105 ;
    END
  END rw0_rd_out[112]
  PIN rw0_rd_out[113]
    DIRECTION OUTPUT ;
    USE SIGNAL ;
    SHAPE ABUTMENT ;
    PORT
      LAYER M3 ;
      RECT 0 175.315 0.07 175.385 ;
    END
  END rw0_rd_out[113]
  PIN rw0_rd_out[114]
    DIRECTION OUTPUT ;
    USE SIGNAL ;
    SHAPE ABUTMENT ;
    PORT
      LAYER M3 ;
      RECT 0 175.595 0.07 175.665 ;
    END
  END rw0_rd_out[114]
  PIN rw0_rd_out[115]
    DIRECTION OUTPUT ;
    USE SIGNAL ;
    SHAPE ABUTMENT ;
    PORT
      LAYER M3 ;
      RECT 0 175.875 0.07 175.945 ;
    END
  END rw0_rd_out[115]
  PIN rw0_rd_out[116]
    DIRECTION OUTPUT ;
    USE SIGNAL ;
    SHAPE ABUTMENT ;
    PORT
      LAYER M3 ;
      RECT 0 176.155 0.07 176.225 ;
    END
  END rw0_rd_out[116]
  PIN rw0_rd_out[117]
    DIRECTION OUTPUT ;
    USE SIGNAL ;
    SHAPE ABUTMENT ;
    PORT
      LAYER M3 ;
      RECT 0 176.435 0.07 176.505 ;
    END
  END rw0_rd_out[117]
  PIN rw0_rd_out[118]
    DIRECTION OUTPUT ;
    USE SIGNAL ;
    SHAPE ABUTMENT ;
    PORT
      LAYER M3 ;
      RECT 0 176.715 0.07 176.785 ;
    END
  END rw0_rd_out[118]
  PIN rw0_rd_out[119]
    DIRECTION OUTPUT ;
    USE SIGNAL ;
    SHAPE ABUTMENT ;
    PORT
      LAYER M3 ;
      RECT 0 176.995 0.07 177.065 ;
    END
  END rw0_rd_out[119]
  PIN rw0_rd_out[120]
    DIRECTION OUTPUT ;
    USE SIGNAL ;
    SHAPE ABUTMENT ;
    PORT
      LAYER M3 ;
      RECT 0 177.275 0.07 177.345 ;
    END
  END rw0_rd_out[120]
  PIN rw0_rd_out[121]
    DIRECTION OUTPUT ;
    USE SIGNAL ;
    SHAPE ABUTMENT ;
    PORT
      LAYER M3 ;
      RECT 0 177.555 0.07 177.625 ;
    END
  END rw0_rd_out[121]
  PIN rw0_rd_out[122]
    DIRECTION OUTPUT ;
    USE SIGNAL ;
    SHAPE ABUTMENT ;
    PORT
      LAYER M3 ;
      RECT 0 177.835 0.07 177.905 ;
    END
  END rw0_rd_out[122]
  PIN rw0_rd_out[123]
    DIRECTION OUTPUT ;
    USE SIGNAL ;
    SHAPE ABUTMENT ;
    PORT
      LAYER M3 ;
      RECT 0 178.115 0.07 178.185 ;
    END
  END rw0_rd_out[123]
  PIN rw0_rd_out[124]
    DIRECTION OUTPUT ;
    USE SIGNAL ;
    SHAPE ABUTMENT ;
    PORT
      LAYER M3 ;
      RECT 0 178.395 0.07 178.465 ;
    END
  END rw0_rd_out[124]
  PIN rw0_rd_out[125]
    DIRECTION OUTPUT ;
    USE SIGNAL ;
    SHAPE ABUTMENT ;
    PORT
      LAYER M3 ;
      RECT 0 178.675 0.07 178.745 ;
    END
  END rw0_rd_out[125]
  PIN rw0_rd_out[126]
    DIRECTION OUTPUT ;
    USE SIGNAL ;
    SHAPE ABUTMENT ;
    PORT
      LAYER M3 ;
      RECT 0 178.955 0.07 179.025 ;
    END
  END rw0_rd_out[126]
  PIN rw0_rd_out[127]
    DIRECTION OUTPUT ;
    USE SIGNAL ;
    SHAPE ABUTMENT ;
    PORT
      LAYER M3 ;
      RECT 0 179.235 0.07 179.305 ;
    END
  END rw0_rd_out[127]
  PIN rw0_rd_out[128]
    DIRECTION OUTPUT ;
    USE SIGNAL ;
    SHAPE ABUTMENT ;
    PORT
      LAYER M3 ;
      RECT 0 179.515 0.07 179.585 ;
    END
  END rw0_rd_out[128]
  PIN rw0_rd_out[129]
    DIRECTION OUTPUT ;
    USE SIGNAL ;
    SHAPE ABUTMENT ;
    PORT
      LAYER M3 ;
      RECT 0 179.795 0.07 179.865 ;
    END
  END rw0_rd_out[129]
  PIN rw0_rd_out[130]
    DIRECTION OUTPUT ;
    USE SIGNAL ;
    SHAPE ABUTMENT ;
    PORT
      LAYER M3 ;
      RECT 0 180.075 0.07 180.145 ;
    END
  END rw0_rd_out[130]
  PIN rw0_rd_out[131]
    DIRECTION OUTPUT ;
    USE SIGNAL ;
    SHAPE ABUTMENT ;
    PORT
      LAYER M3 ;
      RECT 0 180.355 0.07 180.425 ;
    END
  END rw0_rd_out[131]
  PIN rw0_rd_out[132]
    DIRECTION OUTPUT ;
    USE SIGNAL ;
    SHAPE ABUTMENT ;
    PORT
      LAYER M3 ;
      RECT 0 180.635 0.07 180.705 ;
    END
  END rw0_rd_out[132]
  PIN rw0_rd_out[133]
    DIRECTION OUTPUT ;
    USE SIGNAL ;
    SHAPE ABUTMENT ;
    PORT
      LAYER M3 ;
      RECT 0 180.915 0.07 180.985 ;
    END
  END rw0_rd_out[133]
  PIN rw0_rd_out[134]
    DIRECTION OUTPUT ;
    USE SIGNAL ;
    SHAPE ABUTMENT ;
    PORT
      LAYER M3 ;
      RECT 0 181.195 0.07 181.265 ;
    END
  END rw0_rd_out[134]
  PIN rw0_rd_out[135]
    DIRECTION OUTPUT ;
    USE SIGNAL ;
    SHAPE ABUTMENT ;
    PORT
      LAYER M3 ;
      RECT 0 181.475 0.07 181.545 ;
    END
  END rw0_rd_out[135]
  PIN rw0_rd_out[136]
    DIRECTION OUTPUT ;
    USE SIGNAL ;
    SHAPE ABUTMENT ;
    PORT
      LAYER M3 ;
      RECT 0 181.755 0.07 181.825 ;
    END
  END rw0_rd_out[136]
  PIN rw0_rd_out[137]
    DIRECTION OUTPUT ;
    USE SIGNAL ;
    SHAPE ABUTMENT ;
    PORT
      LAYER M3 ;
      RECT 0 182.035 0.07 182.105 ;
    END
  END rw0_rd_out[137]
  PIN rw0_rd_out[138]
    DIRECTION OUTPUT ;
    USE SIGNAL ;
    SHAPE ABUTMENT ;
    PORT
      LAYER M3 ;
      RECT 0 182.315 0.07 182.385 ;
    END
  END rw0_rd_out[138]
  PIN rw0_rd_out[139]
    DIRECTION OUTPUT ;
    USE SIGNAL ;
    SHAPE ABUTMENT ;
    PORT
      LAYER M3 ;
      RECT 0 182.595 0.07 182.665 ;
    END
  END rw0_rd_out[139]
  PIN rw0_rd_out[140]
    DIRECTION OUTPUT ;
    USE SIGNAL ;
    SHAPE ABUTMENT ;
    PORT
      LAYER M3 ;
      RECT 0 182.875 0.07 182.945 ;
    END
  END rw0_rd_out[140]
  PIN rw0_rd_out[141]
    DIRECTION OUTPUT ;
    USE SIGNAL ;
    SHAPE ABUTMENT ;
    PORT
      LAYER M3 ;
      RECT 0 183.155 0.07 183.225 ;
    END
  END rw0_rd_out[141]
  PIN rw0_rd_out[142]
    DIRECTION OUTPUT ;
    USE SIGNAL ;
    SHAPE ABUTMENT ;
    PORT
      LAYER M3 ;
      RECT 0 183.435 0.07 183.505 ;
    END
  END rw0_rd_out[142]
  PIN rw0_rd_out[143]
    DIRECTION OUTPUT ;
    USE SIGNAL ;
    SHAPE ABUTMENT ;
    PORT
      LAYER M3 ;
      RECT 0 183.715 0.07 183.785 ;
    END
  END rw0_rd_out[143]
  PIN rw0_rd_out[144]
    DIRECTION OUTPUT ;
    USE SIGNAL ;
    SHAPE ABUTMENT ;
    PORT
      LAYER M3 ;
      RECT 0 183.995 0.07 184.065 ;
    END
  END rw0_rd_out[144]
  PIN rw0_rd_out[145]
    DIRECTION OUTPUT ;
    USE SIGNAL ;
    SHAPE ABUTMENT ;
    PORT
      LAYER M3 ;
      RECT 0 184.275 0.07 184.345 ;
    END
  END rw0_rd_out[145]
  PIN rw0_rd_out[146]
    DIRECTION OUTPUT ;
    USE SIGNAL ;
    SHAPE ABUTMENT ;
    PORT
      LAYER M3 ;
      RECT 0 184.555 0.07 184.625 ;
    END
  END rw0_rd_out[146]
  PIN rw0_rd_out[147]
    DIRECTION OUTPUT ;
    USE SIGNAL ;
    SHAPE ABUTMENT ;
    PORT
      LAYER M3 ;
      RECT 0 184.835 0.07 184.905 ;
    END
  END rw0_rd_out[147]
  PIN rw0_rd_out[148]
    DIRECTION OUTPUT ;
    USE SIGNAL ;
    SHAPE ABUTMENT ;
    PORT
      LAYER M3 ;
      RECT 0 185.115 0.07 185.185 ;
    END
  END rw0_rd_out[148]
  PIN rw0_rd_out[149]
    DIRECTION OUTPUT ;
    USE SIGNAL ;
    SHAPE ABUTMENT ;
    PORT
      LAYER M3 ;
      RECT 0 185.395 0.07 185.465 ;
    END
  END rw0_rd_out[149]
  PIN rw0_rd_out[150]
    DIRECTION OUTPUT ;
    USE SIGNAL ;
    SHAPE ABUTMENT ;
    PORT
      LAYER M3 ;
      RECT 0 185.675 0.07 185.745 ;
    END
  END rw0_rd_out[150]
  PIN rw0_rd_out[151]
    DIRECTION OUTPUT ;
    USE SIGNAL ;
    SHAPE ABUTMENT ;
    PORT
      LAYER M3 ;
      RECT 0 185.955 0.07 186.025 ;
    END
  END rw0_rd_out[151]
  PIN rw0_rd_out[152]
    DIRECTION OUTPUT ;
    USE SIGNAL ;
    SHAPE ABUTMENT ;
    PORT
      LAYER M3 ;
      RECT 0 186.235 0.07 186.305 ;
    END
  END rw0_rd_out[152]
  PIN rw0_rd_out[153]
    DIRECTION OUTPUT ;
    USE SIGNAL ;
    SHAPE ABUTMENT ;
    PORT
      LAYER M3 ;
      RECT 0 186.515 0.07 186.585 ;
    END
  END rw0_rd_out[153]
  PIN rw0_rd_out[154]
    DIRECTION OUTPUT ;
    USE SIGNAL ;
    SHAPE ABUTMENT ;
    PORT
      LAYER M3 ;
      RECT 0 186.795 0.07 186.865 ;
    END
  END rw0_rd_out[154]
  PIN rw0_rd_out[155]
    DIRECTION OUTPUT ;
    USE SIGNAL ;
    SHAPE ABUTMENT ;
    PORT
      LAYER M3 ;
      RECT 0 187.075 0.07 187.145 ;
    END
  END rw0_rd_out[155]
  PIN rw0_rd_out[156]
    DIRECTION OUTPUT ;
    USE SIGNAL ;
    SHAPE ABUTMENT ;
    PORT
      LAYER M3 ;
      RECT 0 187.355 0.07 187.425 ;
    END
  END rw0_rd_out[156]
  PIN rw0_rd_out[157]
    DIRECTION OUTPUT ;
    USE SIGNAL ;
    SHAPE ABUTMENT ;
    PORT
      LAYER M3 ;
      RECT 0 187.635 0.07 187.705 ;
    END
  END rw0_rd_out[157]
  PIN rw0_rd_out[158]
    DIRECTION OUTPUT ;
    USE SIGNAL ;
    SHAPE ABUTMENT ;
    PORT
      LAYER M3 ;
      RECT 0 187.915 0.07 187.985 ;
    END
  END rw0_rd_out[158]
  PIN rw0_rd_out[159]
    DIRECTION OUTPUT ;
    USE SIGNAL ;
    SHAPE ABUTMENT ;
    PORT
      LAYER M3 ;
      RECT 0 188.195 0.07 188.265 ;
    END
  END rw0_rd_out[159]
  PIN rw0_rd_out[160]
    DIRECTION OUTPUT ;
    USE SIGNAL ;
    SHAPE ABUTMENT ;
    PORT
      LAYER M3 ;
      RECT 0 188.475 0.07 188.545 ;
    END
  END rw0_rd_out[160]
  PIN rw0_rd_out[161]
    DIRECTION OUTPUT ;
    USE SIGNAL ;
    SHAPE ABUTMENT ;
    PORT
      LAYER M3 ;
      RECT 0 188.755 0.07 188.825 ;
    END
  END rw0_rd_out[161]
  PIN rw0_rd_out[162]
    DIRECTION OUTPUT ;
    USE SIGNAL ;
    SHAPE ABUTMENT ;
    PORT
      LAYER M3 ;
      RECT 0 189.035 0.07 189.105 ;
    END
  END rw0_rd_out[162]
  PIN rw0_rd_out[163]
    DIRECTION OUTPUT ;
    USE SIGNAL ;
    SHAPE ABUTMENT ;
    PORT
      LAYER M3 ;
      RECT 0 189.315 0.07 189.385 ;
    END
  END rw0_rd_out[163]
  PIN rw0_rd_out[164]
    DIRECTION OUTPUT ;
    USE SIGNAL ;
    SHAPE ABUTMENT ;
    PORT
      LAYER M3 ;
      RECT 0 189.595 0.07 189.665 ;
    END
  END rw0_rd_out[164]
  PIN rw0_rd_out[165]
    DIRECTION OUTPUT ;
    USE SIGNAL ;
    SHAPE ABUTMENT ;
    PORT
      LAYER M3 ;
      RECT 0 189.875 0.07 189.945 ;
    END
  END rw0_rd_out[165]
  PIN rw0_rd_out[166]
    DIRECTION OUTPUT ;
    USE SIGNAL ;
    SHAPE ABUTMENT ;
    PORT
      LAYER M3 ;
      RECT 0 190.155 0.07 190.225 ;
    END
  END rw0_rd_out[166]
  PIN rw0_rd_out[167]
    DIRECTION OUTPUT ;
    USE SIGNAL ;
    SHAPE ABUTMENT ;
    PORT
      LAYER M3 ;
      RECT 0 190.435 0.07 190.505 ;
    END
  END rw0_rd_out[167]
  PIN rw0_rd_out[168]
    DIRECTION OUTPUT ;
    USE SIGNAL ;
    SHAPE ABUTMENT ;
    PORT
      LAYER M3 ;
      RECT 0 190.715 0.07 190.785 ;
    END
  END rw0_rd_out[168]
  PIN rw0_rd_out[169]
    DIRECTION OUTPUT ;
    USE SIGNAL ;
    SHAPE ABUTMENT ;
    PORT
      LAYER M3 ;
      RECT 0 190.995 0.07 191.065 ;
    END
  END rw0_rd_out[169]
  PIN rw0_rd_out[170]
    DIRECTION OUTPUT ;
    USE SIGNAL ;
    SHAPE ABUTMENT ;
    PORT
      LAYER M3 ;
      RECT 0 191.275 0.07 191.345 ;
    END
  END rw0_rd_out[170]
  PIN rw0_rd_out[171]
    DIRECTION OUTPUT ;
    USE SIGNAL ;
    SHAPE ABUTMENT ;
    PORT
      LAYER M3 ;
      RECT 0 191.555 0.07 191.625 ;
    END
  END rw0_rd_out[171]
  PIN rw0_rd_out[172]
    DIRECTION OUTPUT ;
    USE SIGNAL ;
    SHAPE ABUTMENT ;
    PORT
      LAYER M3 ;
      RECT 0 191.835 0.07 191.905 ;
    END
  END rw0_rd_out[172]
  PIN rw0_rd_out[173]
    DIRECTION OUTPUT ;
    USE SIGNAL ;
    SHAPE ABUTMENT ;
    PORT
      LAYER M3 ;
      RECT 0 192.115 0.07 192.185 ;
    END
  END rw0_rd_out[173]
  PIN rw0_rd_out[174]
    DIRECTION OUTPUT ;
    USE SIGNAL ;
    SHAPE ABUTMENT ;
    PORT
      LAYER M3 ;
      RECT 0 192.395 0.07 192.465 ;
    END
  END rw0_rd_out[174]
  PIN rw0_rd_out[175]
    DIRECTION OUTPUT ;
    USE SIGNAL ;
    SHAPE ABUTMENT ;
    PORT
      LAYER M3 ;
      RECT 0 192.675 0.07 192.745 ;
    END
  END rw0_rd_out[175]
  PIN rw0_rd_out[176]
    DIRECTION OUTPUT ;
    USE SIGNAL ;
    SHAPE ABUTMENT ;
    PORT
      LAYER M3 ;
      RECT 0 192.955 0.07 193.025 ;
    END
  END rw0_rd_out[176]
  PIN rw0_rd_out[177]
    DIRECTION OUTPUT ;
    USE SIGNAL ;
    SHAPE ABUTMENT ;
    PORT
      LAYER M3 ;
      RECT 0 193.235 0.07 193.305 ;
    END
  END rw0_rd_out[177]
  PIN rw0_rd_out[178]
    DIRECTION OUTPUT ;
    USE SIGNAL ;
    SHAPE ABUTMENT ;
    PORT
      LAYER M3 ;
      RECT 0 193.515 0.07 193.585 ;
    END
  END rw0_rd_out[178]
  PIN rw0_rd_out[179]
    DIRECTION OUTPUT ;
    USE SIGNAL ;
    SHAPE ABUTMENT ;
    PORT
      LAYER M3 ;
      RECT 0 193.795 0.07 193.865 ;
    END
  END rw0_rd_out[179]
  PIN rw0_rd_out[180]
    DIRECTION OUTPUT ;
    USE SIGNAL ;
    SHAPE ABUTMENT ;
    PORT
      LAYER M3 ;
      RECT 0 194.075 0.07 194.145 ;
    END
  END rw0_rd_out[180]
  PIN rw0_rd_out[181]
    DIRECTION OUTPUT ;
    USE SIGNAL ;
    SHAPE ABUTMENT ;
    PORT
      LAYER M3 ;
      RECT 0 194.355 0.07 194.425 ;
    END
  END rw0_rd_out[181]
  PIN rw0_rd_out[182]
    DIRECTION OUTPUT ;
    USE SIGNAL ;
    SHAPE ABUTMENT ;
    PORT
      LAYER M3 ;
      RECT 0 194.635 0.07 194.705 ;
    END
  END rw0_rd_out[182]
  PIN rw0_rd_out[183]
    DIRECTION OUTPUT ;
    USE SIGNAL ;
    SHAPE ABUTMENT ;
    PORT
      LAYER M3 ;
      RECT 0 194.915 0.07 194.985 ;
    END
  END rw0_rd_out[183]
  PIN rw0_rd_out[184]
    DIRECTION OUTPUT ;
    USE SIGNAL ;
    SHAPE ABUTMENT ;
    PORT
      LAYER M3 ;
      RECT 0 195.195 0.07 195.265 ;
    END
  END rw0_rd_out[184]
  PIN rw0_rd_out[185]
    DIRECTION OUTPUT ;
    USE SIGNAL ;
    SHAPE ABUTMENT ;
    PORT
      LAYER M3 ;
      RECT 0 195.475 0.07 195.545 ;
    END
  END rw0_rd_out[185]
  PIN rw0_rd_out[186]
    DIRECTION OUTPUT ;
    USE SIGNAL ;
    SHAPE ABUTMENT ;
    PORT
      LAYER M3 ;
      RECT 0 195.755 0.07 195.825 ;
    END
  END rw0_rd_out[186]
  PIN rw0_rd_out[187]
    DIRECTION OUTPUT ;
    USE SIGNAL ;
    SHAPE ABUTMENT ;
    PORT
      LAYER M3 ;
      RECT 0 196.035 0.07 196.105 ;
    END
  END rw0_rd_out[187]
  PIN rw0_rd_out[188]
    DIRECTION OUTPUT ;
    USE SIGNAL ;
    SHAPE ABUTMENT ;
    PORT
      LAYER M3 ;
      RECT 0 196.315 0.07 196.385 ;
    END
  END rw0_rd_out[188]
  PIN rw0_rd_out[189]
    DIRECTION OUTPUT ;
    USE SIGNAL ;
    SHAPE ABUTMENT ;
    PORT
      LAYER M3 ;
      RECT 0 196.595 0.07 196.665 ;
    END
  END rw0_rd_out[189]
  PIN rw0_rd_out[190]
    DIRECTION OUTPUT ;
    USE SIGNAL ;
    SHAPE ABUTMENT ;
    PORT
      LAYER M3 ;
      RECT 0 196.875 0.07 196.945 ;
    END
  END rw0_rd_out[190]
  PIN rw0_rd_out[191]
    DIRECTION OUTPUT ;
    USE SIGNAL ;
    SHAPE ABUTMENT ;
    PORT
      LAYER M3 ;
      RECT 0 197.155 0.07 197.225 ;
    END
  END rw0_rd_out[191]
  PIN rw0_rd_out[192]
    DIRECTION OUTPUT ;
    USE SIGNAL ;
    SHAPE ABUTMENT ;
    PORT
      LAYER M3 ;
      RECT 0 197.435 0.07 197.505 ;
    END
  END rw0_rd_out[192]
  PIN rw0_rd_out[193]
    DIRECTION OUTPUT ;
    USE SIGNAL ;
    SHAPE ABUTMENT ;
    PORT
      LAYER M3 ;
      RECT 0 197.715 0.07 197.785 ;
    END
  END rw0_rd_out[193]
  PIN rw0_rd_out[194]
    DIRECTION OUTPUT ;
    USE SIGNAL ;
    SHAPE ABUTMENT ;
    PORT
      LAYER M3 ;
      RECT 0 197.995 0.07 198.065 ;
    END
  END rw0_rd_out[194]
  PIN rw0_rd_out[195]
    DIRECTION OUTPUT ;
    USE SIGNAL ;
    SHAPE ABUTMENT ;
    PORT
      LAYER M3 ;
      RECT 0 198.275 0.07 198.345 ;
    END
  END rw0_rd_out[195]
  PIN rw0_rd_out[196]
    DIRECTION OUTPUT ;
    USE SIGNAL ;
    SHAPE ABUTMENT ;
    PORT
      LAYER M3 ;
      RECT 0 198.555 0.07 198.625 ;
    END
  END rw0_rd_out[196]
  PIN rw0_rd_out[197]
    DIRECTION OUTPUT ;
    USE SIGNAL ;
    SHAPE ABUTMENT ;
    PORT
      LAYER M3 ;
      RECT 0 198.835 0.07 198.905 ;
    END
  END rw0_rd_out[197]
  PIN rw0_rd_out[198]
    DIRECTION OUTPUT ;
    USE SIGNAL ;
    SHAPE ABUTMENT ;
    PORT
      LAYER M3 ;
      RECT 0 199.115 0.07 199.185 ;
    END
  END rw0_rd_out[198]
  PIN rw0_rd_out[199]
    DIRECTION OUTPUT ;
    USE SIGNAL ;
    SHAPE ABUTMENT ;
    PORT
      LAYER M3 ;
      RECT 0 199.395 0.07 199.465 ;
    END
  END rw0_rd_out[199]
  PIN rw0_rd_out[200]
    DIRECTION OUTPUT ;
    USE SIGNAL ;
    SHAPE ABUTMENT ;
    PORT
      LAYER M3 ;
      RECT 0 199.675 0.07 199.745 ;
    END
  END rw0_rd_out[200]
  PIN rw0_rd_out[201]
    DIRECTION OUTPUT ;
    USE SIGNAL ;
    SHAPE ABUTMENT ;
    PORT
      LAYER M3 ;
      RECT 0 199.955 0.07 200.025 ;
    END
  END rw0_rd_out[201]
  PIN rw0_rd_out[202]
    DIRECTION OUTPUT ;
    USE SIGNAL ;
    SHAPE ABUTMENT ;
    PORT
      LAYER M3 ;
      RECT 0 200.235 0.07 200.305 ;
    END
  END rw0_rd_out[202]
  PIN rw0_rd_out[203]
    DIRECTION OUTPUT ;
    USE SIGNAL ;
    SHAPE ABUTMENT ;
    PORT
      LAYER M3 ;
      RECT 0 200.515 0.07 200.585 ;
    END
  END rw0_rd_out[203]
  PIN rw0_rd_out[204]
    DIRECTION OUTPUT ;
    USE SIGNAL ;
    SHAPE ABUTMENT ;
    PORT
      LAYER M3 ;
      RECT 0 200.795 0.07 200.865 ;
    END
  END rw0_rd_out[204]
  PIN rw0_rd_out[205]
    DIRECTION OUTPUT ;
    USE SIGNAL ;
    SHAPE ABUTMENT ;
    PORT
      LAYER M3 ;
      RECT 0 201.075 0.07 201.145 ;
    END
  END rw0_rd_out[205]
  PIN rw0_rd_out[206]
    DIRECTION OUTPUT ;
    USE SIGNAL ;
    SHAPE ABUTMENT ;
    PORT
      LAYER M3 ;
      RECT 0 201.355 0.07 201.425 ;
    END
  END rw0_rd_out[206]
  PIN rw0_rd_out[207]
    DIRECTION OUTPUT ;
    USE SIGNAL ;
    SHAPE ABUTMENT ;
    PORT
      LAYER M3 ;
      RECT 0 201.635 0.07 201.705 ;
    END
  END rw0_rd_out[207]
  PIN rw0_rd_out[208]
    DIRECTION OUTPUT ;
    USE SIGNAL ;
    SHAPE ABUTMENT ;
    PORT
      LAYER M3 ;
      RECT 0 201.915 0.07 201.985 ;
    END
  END rw0_rd_out[208]
  PIN rw0_rd_out[209]
    DIRECTION OUTPUT ;
    USE SIGNAL ;
    SHAPE ABUTMENT ;
    PORT
      LAYER M3 ;
      RECT 0 202.195 0.07 202.265 ;
    END
  END rw0_rd_out[209]
  PIN rw0_rd_out[210]
    DIRECTION OUTPUT ;
    USE SIGNAL ;
    SHAPE ABUTMENT ;
    PORT
      LAYER M3 ;
      RECT 0 202.475 0.07 202.545 ;
    END
  END rw0_rd_out[210]
  PIN rw0_rd_out[211]
    DIRECTION OUTPUT ;
    USE SIGNAL ;
    SHAPE ABUTMENT ;
    PORT
      LAYER M3 ;
      RECT 0 202.755 0.07 202.825 ;
    END
  END rw0_rd_out[211]
  PIN rw0_rd_out[212]
    DIRECTION OUTPUT ;
    USE SIGNAL ;
    SHAPE ABUTMENT ;
    PORT
      LAYER M3 ;
      RECT 0 203.035 0.07 203.105 ;
    END
  END rw0_rd_out[212]
  PIN rw0_rd_out[213]
    DIRECTION OUTPUT ;
    USE SIGNAL ;
    SHAPE ABUTMENT ;
    PORT
      LAYER M3 ;
      RECT 0 203.315 0.07 203.385 ;
    END
  END rw0_rd_out[213]
  PIN rw0_rd_out[214]
    DIRECTION OUTPUT ;
    USE SIGNAL ;
    SHAPE ABUTMENT ;
    PORT
      LAYER M3 ;
      RECT 0 203.595 0.07 203.665 ;
    END
  END rw0_rd_out[214]
  PIN rw0_rd_out[215]
    DIRECTION OUTPUT ;
    USE SIGNAL ;
    SHAPE ABUTMENT ;
    PORT
      LAYER M3 ;
      RECT 0 203.875 0.07 203.945 ;
    END
  END rw0_rd_out[215]
  PIN rw0_rd_out[216]
    DIRECTION OUTPUT ;
    USE SIGNAL ;
    SHAPE ABUTMENT ;
    PORT
      LAYER M3 ;
      RECT 0 204.155 0.07 204.225 ;
    END
  END rw0_rd_out[216]
  PIN rw0_rd_out[217]
    DIRECTION OUTPUT ;
    USE SIGNAL ;
    SHAPE ABUTMENT ;
    PORT
      LAYER M3 ;
      RECT 0 204.435 0.07 204.505 ;
    END
  END rw0_rd_out[217]
  PIN rw0_rd_out[218]
    DIRECTION OUTPUT ;
    USE SIGNAL ;
    SHAPE ABUTMENT ;
    PORT
      LAYER M3 ;
      RECT 0 204.715 0.07 204.785 ;
    END
  END rw0_rd_out[218]
  PIN rw0_rd_out[219]
    DIRECTION OUTPUT ;
    USE SIGNAL ;
    SHAPE ABUTMENT ;
    PORT
      LAYER M3 ;
      RECT 0 204.995 0.07 205.065 ;
    END
  END rw0_rd_out[219]
  PIN rw0_rd_out[220]
    DIRECTION OUTPUT ;
    USE SIGNAL ;
    SHAPE ABUTMENT ;
    PORT
      LAYER M3 ;
      RECT 0 205.275 0.07 205.345 ;
    END
  END rw0_rd_out[220]
  PIN rw0_rd_out[221]
    DIRECTION OUTPUT ;
    USE SIGNAL ;
    SHAPE ABUTMENT ;
    PORT
      LAYER M3 ;
      RECT 0 205.555 0.07 205.625 ;
    END
  END rw0_rd_out[221]
  PIN rw0_rd_out[222]
    DIRECTION OUTPUT ;
    USE SIGNAL ;
    SHAPE ABUTMENT ;
    PORT
      LAYER M3 ;
      RECT 0 205.835 0.07 205.905 ;
    END
  END rw0_rd_out[222]
  PIN rw0_rd_out[223]
    DIRECTION OUTPUT ;
    USE SIGNAL ;
    SHAPE ABUTMENT ;
    PORT
      LAYER M3 ;
      RECT 0 206.115 0.07 206.185 ;
    END
  END rw0_rd_out[223]
  PIN rw0_rd_out[224]
    DIRECTION OUTPUT ;
    USE SIGNAL ;
    SHAPE ABUTMENT ;
    PORT
      LAYER M3 ;
      RECT 0 206.395 0.07 206.465 ;
    END
  END rw0_rd_out[224]
  PIN rw0_rd_out[225]
    DIRECTION OUTPUT ;
    USE SIGNAL ;
    SHAPE ABUTMENT ;
    PORT
      LAYER M3 ;
      RECT 0 206.675 0.07 206.745 ;
    END
  END rw0_rd_out[225]
  PIN rw0_rd_out[226]
    DIRECTION OUTPUT ;
    USE SIGNAL ;
    SHAPE ABUTMENT ;
    PORT
      LAYER M3 ;
      RECT 0 206.955 0.07 207.025 ;
    END
  END rw0_rd_out[226]
  PIN rw0_rd_out[227]
    DIRECTION OUTPUT ;
    USE SIGNAL ;
    SHAPE ABUTMENT ;
    PORT
      LAYER M3 ;
      RECT 0 207.235 0.07 207.305 ;
    END
  END rw0_rd_out[227]
  PIN rw0_rd_out[228]
    DIRECTION OUTPUT ;
    USE SIGNAL ;
    SHAPE ABUTMENT ;
    PORT
      LAYER M3 ;
      RECT 0 207.515 0.07 207.585 ;
    END
  END rw0_rd_out[228]
  PIN rw0_rd_out[229]
    DIRECTION OUTPUT ;
    USE SIGNAL ;
    SHAPE ABUTMENT ;
    PORT
      LAYER M3 ;
      RECT 0 207.795 0.07 207.865 ;
    END
  END rw0_rd_out[229]
  PIN rw0_rd_out[230]
    DIRECTION OUTPUT ;
    USE SIGNAL ;
    SHAPE ABUTMENT ;
    PORT
      LAYER M3 ;
      RECT 0 208.075 0.07 208.145 ;
    END
  END rw0_rd_out[230]
  PIN rw0_rd_out[231]
    DIRECTION OUTPUT ;
    USE SIGNAL ;
    SHAPE ABUTMENT ;
    PORT
      LAYER M3 ;
      RECT 0 208.355 0.07 208.425 ;
    END
  END rw0_rd_out[231]
  PIN rw0_rd_out[232]
    DIRECTION OUTPUT ;
    USE SIGNAL ;
    SHAPE ABUTMENT ;
    PORT
      LAYER M3 ;
      RECT 0 208.635 0.07 208.705 ;
    END
  END rw0_rd_out[232]
  PIN rw0_rd_out[233]
    DIRECTION OUTPUT ;
    USE SIGNAL ;
    SHAPE ABUTMENT ;
    PORT
      LAYER M3 ;
      RECT 0 208.915 0.07 208.985 ;
    END
  END rw0_rd_out[233]
  PIN rw0_rd_out[234]
    DIRECTION OUTPUT ;
    USE SIGNAL ;
    SHAPE ABUTMENT ;
    PORT
      LAYER M3 ;
      RECT 0 209.195 0.07 209.265 ;
    END
  END rw0_rd_out[234]
  PIN rw0_rd_out[235]
    DIRECTION OUTPUT ;
    USE SIGNAL ;
    SHAPE ABUTMENT ;
    PORT
      LAYER M3 ;
      RECT 0 209.475 0.07 209.545 ;
    END
  END rw0_rd_out[235]
  PIN rw0_rd_out[236]
    DIRECTION OUTPUT ;
    USE SIGNAL ;
    SHAPE ABUTMENT ;
    PORT
      LAYER M3 ;
      RECT 0 209.755 0.07 209.825 ;
    END
  END rw0_rd_out[236]
  PIN rw0_rd_out[237]
    DIRECTION OUTPUT ;
    USE SIGNAL ;
    SHAPE ABUTMENT ;
    PORT
      LAYER M3 ;
      RECT 0 210.035 0.07 210.105 ;
    END
  END rw0_rd_out[237]
  PIN rw0_rd_out[238]
    DIRECTION OUTPUT ;
    USE SIGNAL ;
    SHAPE ABUTMENT ;
    PORT
      LAYER M3 ;
      RECT 0 210.315 0.07 210.385 ;
    END
  END rw0_rd_out[238]
  PIN rw0_rd_out[239]
    DIRECTION OUTPUT ;
    USE SIGNAL ;
    SHAPE ABUTMENT ;
    PORT
      LAYER M3 ;
      RECT 0 210.595 0.07 210.665 ;
    END
  END rw0_rd_out[239]
  PIN rw0_rd_out[240]
    DIRECTION OUTPUT ;
    USE SIGNAL ;
    SHAPE ABUTMENT ;
    PORT
      LAYER M3 ;
      RECT 0 210.875 0.07 210.945 ;
    END
  END rw0_rd_out[240]
  PIN rw0_rd_out[241]
    DIRECTION OUTPUT ;
    USE SIGNAL ;
    SHAPE ABUTMENT ;
    PORT
      LAYER M3 ;
      RECT 0 211.155 0.07 211.225 ;
    END
  END rw0_rd_out[241]
  PIN rw0_rd_out[242]
    DIRECTION OUTPUT ;
    USE SIGNAL ;
    SHAPE ABUTMENT ;
    PORT
      LAYER M3 ;
      RECT 0 211.435 0.07 211.505 ;
    END
  END rw0_rd_out[242]
  PIN rw0_rd_out[243]
    DIRECTION OUTPUT ;
    USE SIGNAL ;
    SHAPE ABUTMENT ;
    PORT
      LAYER M3 ;
      RECT 0 211.715 0.07 211.785 ;
    END
  END rw0_rd_out[243]
  PIN rw0_rd_out[244]
    DIRECTION OUTPUT ;
    USE SIGNAL ;
    SHAPE ABUTMENT ;
    PORT
      LAYER M3 ;
      RECT 0 211.995 0.07 212.065 ;
    END
  END rw0_rd_out[244]
  PIN rw0_rd_out[245]
    DIRECTION OUTPUT ;
    USE SIGNAL ;
    SHAPE ABUTMENT ;
    PORT
      LAYER M3 ;
      RECT 0 212.275 0.07 212.345 ;
    END
  END rw0_rd_out[245]
  PIN rw0_rd_out[246]
    DIRECTION OUTPUT ;
    USE SIGNAL ;
    SHAPE ABUTMENT ;
    PORT
      LAYER M3 ;
      RECT 0 212.555 0.07 212.625 ;
    END
  END rw0_rd_out[246]
  PIN rw0_rd_out[247]
    DIRECTION OUTPUT ;
    USE SIGNAL ;
    SHAPE ABUTMENT ;
    PORT
      LAYER M3 ;
      RECT 0 212.835 0.07 212.905 ;
    END
  END rw0_rd_out[247]
  PIN rw0_rd_out[248]
    DIRECTION OUTPUT ;
    USE SIGNAL ;
    SHAPE ABUTMENT ;
    PORT
      LAYER M3 ;
      RECT 0 213.115 0.07 213.185 ;
    END
  END rw0_rd_out[248]
  PIN rw0_rd_out[249]
    DIRECTION OUTPUT ;
    USE SIGNAL ;
    SHAPE ABUTMENT ;
    PORT
      LAYER M3 ;
      RECT 0 213.395 0.07 213.465 ;
    END
  END rw0_rd_out[249]
  PIN rw0_rd_out[250]
    DIRECTION OUTPUT ;
    USE SIGNAL ;
    SHAPE ABUTMENT ;
    PORT
      LAYER M3 ;
      RECT 0 213.675 0.07 213.745 ;
    END
  END rw0_rd_out[250]
  PIN rw0_rd_out[251]
    DIRECTION OUTPUT ;
    USE SIGNAL ;
    SHAPE ABUTMENT ;
    PORT
      LAYER M3 ;
      RECT 0 213.955 0.07 214.025 ;
    END
  END rw0_rd_out[251]
  PIN rw0_rd_out[252]
    DIRECTION OUTPUT ;
    USE SIGNAL ;
    SHAPE ABUTMENT ;
    PORT
      LAYER M3 ;
      RECT 0 214.235 0.07 214.305 ;
    END
  END rw0_rd_out[252]
  PIN rw0_rd_out[253]
    DIRECTION OUTPUT ;
    USE SIGNAL ;
    SHAPE ABUTMENT ;
    PORT
      LAYER M3 ;
      RECT 0 214.515 0.07 214.585 ;
    END
  END rw0_rd_out[253]
  PIN rw0_rd_out[254]
    DIRECTION OUTPUT ;
    USE SIGNAL ;
    SHAPE ABUTMENT ;
    PORT
      LAYER M3 ;
      RECT 0 214.795 0.07 214.865 ;
    END
  END rw0_rd_out[254]
  PIN rw0_rd_out[255]
    DIRECTION OUTPUT ;
    USE SIGNAL ;
    SHAPE ABUTMENT ;
    PORT
      LAYER M3 ;
      RECT 0 215.075 0.07 215.145 ;
    END
  END rw0_rd_out[255]
  PIN rw0_rd_out[256]
    DIRECTION OUTPUT ;
    USE SIGNAL ;
    SHAPE ABUTMENT ;
    PORT
      LAYER M3 ;
      RECT 0 215.355 0.07 215.425 ;
    END
  END rw0_rd_out[256]
  PIN rw0_rd_out[257]
    DIRECTION OUTPUT ;
    USE SIGNAL ;
    SHAPE ABUTMENT ;
    PORT
      LAYER M3 ;
      RECT 0 215.635 0.07 215.705 ;
    END
  END rw0_rd_out[257]
  PIN rw0_rd_out[258]
    DIRECTION OUTPUT ;
    USE SIGNAL ;
    SHAPE ABUTMENT ;
    PORT
      LAYER M3 ;
      RECT 0 215.915 0.07 215.985 ;
    END
  END rw0_rd_out[258]
  PIN rw0_rd_out[259]
    DIRECTION OUTPUT ;
    USE SIGNAL ;
    SHAPE ABUTMENT ;
    PORT
      LAYER M3 ;
      RECT 0 216.195 0.07 216.265 ;
    END
  END rw0_rd_out[259]
  PIN rw0_rd_out[260]
    DIRECTION OUTPUT ;
    USE SIGNAL ;
    SHAPE ABUTMENT ;
    PORT
      LAYER M3 ;
      RECT 0 216.475 0.07 216.545 ;
    END
  END rw0_rd_out[260]
  PIN rw0_rd_out[261]
    DIRECTION OUTPUT ;
    USE SIGNAL ;
    SHAPE ABUTMENT ;
    PORT
      LAYER M3 ;
      RECT 0 216.755 0.07 216.825 ;
    END
  END rw0_rd_out[261]
  PIN rw0_rd_out[262]
    DIRECTION OUTPUT ;
    USE SIGNAL ;
    SHAPE ABUTMENT ;
    PORT
      LAYER M3 ;
      RECT 0 217.035 0.07 217.105 ;
    END
  END rw0_rd_out[262]
  PIN rw0_rd_out[263]
    DIRECTION OUTPUT ;
    USE SIGNAL ;
    SHAPE ABUTMENT ;
    PORT
      LAYER M3 ;
      RECT 0 217.315 0.07 217.385 ;
    END
  END rw0_rd_out[263]
  PIN rw0_rd_out[264]
    DIRECTION OUTPUT ;
    USE SIGNAL ;
    SHAPE ABUTMENT ;
    PORT
      LAYER M3 ;
      RECT 0 217.595 0.07 217.665 ;
    END
  END rw0_rd_out[264]
  PIN rw0_rd_out[265]
    DIRECTION OUTPUT ;
    USE SIGNAL ;
    SHAPE ABUTMENT ;
    PORT
      LAYER M3 ;
      RECT 0 217.875 0.07 217.945 ;
    END
  END rw0_rd_out[265]
  PIN rw0_rd_out[266]
    DIRECTION OUTPUT ;
    USE SIGNAL ;
    SHAPE ABUTMENT ;
    PORT
      LAYER M3 ;
      RECT 0 218.155 0.07 218.225 ;
    END
  END rw0_rd_out[266]
  PIN rw0_rd_out[267]
    DIRECTION OUTPUT ;
    USE SIGNAL ;
    SHAPE ABUTMENT ;
    PORT
      LAYER M3 ;
      RECT 0 218.435 0.07 218.505 ;
    END
  END rw0_rd_out[267]
  PIN rw0_rd_out[268]
    DIRECTION OUTPUT ;
    USE SIGNAL ;
    SHAPE ABUTMENT ;
    PORT
      LAYER M3 ;
      RECT 0 218.715 0.07 218.785 ;
    END
  END rw0_rd_out[268]
  PIN rw0_rd_out[269]
    DIRECTION OUTPUT ;
    USE SIGNAL ;
    SHAPE ABUTMENT ;
    PORT
      LAYER M3 ;
      RECT 0 218.995 0.07 219.065 ;
    END
  END rw0_rd_out[269]
  PIN rw0_rd_out[270]
    DIRECTION OUTPUT ;
    USE SIGNAL ;
    SHAPE ABUTMENT ;
    PORT
      LAYER M3 ;
      RECT 0 219.275 0.07 219.345 ;
    END
  END rw0_rd_out[270]
  PIN rw0_rd_out[271]
    DIRECTION OUTPUT ;
    USE SIGNAL ;
    SHAPE ABUTMENT ;
    PORT
      LAYER M3 ;
      RECT 0 219.555 0.07 219.625 ;
    END
  END rw0_rd_out[271]
  PIN rw0_rd_out[272]
    DIRECTION OUTPUT ;
    USE SIGNAL ;
    SHAPE ABUTMENT ;
    PORT
      LAYER M3 ;
      RECT 0 219.835 0.07 219.905 ;
    END
  END rw0_rd_out[272]
  PIN rw0_rd_out[273]
    DIRECTION OUTPUT ;
    USE SIGNAL ;
    SHAPE ABUTMENT ;
    PORT
      LAYER M3 ;
      RECT 0 220.115 0.07 220.185 ;
    END
  END rw0_rd_out[273]
  PIN rw0_rd_out[274]
    DIRECTION OUTPUT ;
    USE SIGNAL ;
    SHAPE ABUTMENT ;
    PORT
      LAYER M3 ;
      RECT 0 220.395 0.07 220.465 ;
    END
  END rw0_rd_out[274]
  PIN rw0_rd_out[275]
    DIRECTION OUTPUT ;
    USE SIGNAL ;
    SHAPE ABUTMENT ;
    PORT
      LAYER M3 ;
      RECT 0 220.675 0.07 220.745 ;
    END
  END rw0_rd_out[275]
  PIN rw0_rd_out[276]
    DIRECTION OUTPUT ;
    USE SIGNAL ;
    SHAPE ABUTMENT ;
    PORT
      LAYER M3 ;
      RECT 0 220.955 0.07 221.025 ;
    END
  END rw0_rd_out[276]
  PIN rw0_rd_out[277]
    DIRECTION OUTPUT ;
    USE SIGNAL ;
    SHAPE ABUTMENT ;
    PORT
      LAYER M3 ;
      RECT 0 221.235 0.07 221.305 ;
    END
  END rw0_rd_out[277]
  PIN rw0_rd_out[278]
    DIRECTION OUTPUT ;
    USE SIGNAL ;
    SHAPE ABUTMENT ;
    PORT
      LAYER M3 ;
      RECT 0 221.515 0.07 221.585 ;
    END
  END rw0_rd_out[278]
  PIN rw0_rd_out[279]
    DIRECTION OUTPUT ;
    USE SIGNAL ;
    SHAPE ABUTMENT ;
    PORT
      LAYER M3 ;
      RECT 0 221.795 0.07 221.865 ;
    END
  END rw0_rd_out[279]
  PIN rw0_rd_out[280]
    DIRECTION OUTPUT ;
    USE SIGNAL ;
    SHAPE ABUTMENT ;
    PORT
      LAYER M3 ;
      RECT 0 222.075 0.07 222.145 ;
    END
  END rw0_rd_out[280]
  PIN rw0_rd_out[281]
    DIRECTION OUTPUT ;
    USE SIGNAL ;
    SHAPE ABUTMENT ;
    PORT
      LAYER M3 ;
      RECT 0 222.355 0.07 222.425 ;
    END
  END rw0_rd_out[281]
  PIN rw0_rd_out[282]
    DIRECTION OUTPUT ;
    USE SIGNAL ;
    SHAPE ABUTMENT ;
    PORT
      LAYER M3 ;
      RECT 0 222.635 0.07 222.705 ;
    END
  END rw0_rd_out[282]
  PIN rw0_rd_out[283]
    DIRECTION OUTPUT ;
    USE SIGNAL ;
    SHAPE ABUTMENT ;
    PORT
      LAYER M3 ;
      RECT 0 222.915 0.07 222.985 ;
    END
  END rw0_rd_out[283]
  PIN rw0_rd_out[284]
    DIRECTION OUTPUT ;
    USE SIGNAL ;
    SHAPE ABUTMENT ;
    PORT
      LAYER M3 ;
      RECT 0 223.195 0.07 223.265 ;
    END
  END rw0_rd_out[284]
  PIN rw0_rd_out[285]
    DIRECTION OUTPUT ;
    USE SIGNAL ;
    SHAPE ABUTMENT ;
    PORT
      LAYER M3 ;
      RECT 0 223.475 0.07 223.545 ;
    END
  END rw0_rd_out[285]
  PIN rw0_rd_out[286]
    DIRECTION OUTPUT ;
    USE SIGNAL ;
    SHAPE ABUTMENT ;
    PORT
      LAYER M3 ;
      RECT 0 223.755 0.07 223.825 ;
    END
  END rw0_rd_out[286]
  PIN rw0_rd_out[287]
    DIRECTION OUTPUT ;
    USE SIGNAL ;
    SHAPE ABUTMENT ;
    PORT
      LAYER M3 ;
      RECT 0 224.035 0.07 224.105 ;
    END
  END rw0_rd_out[287]
  PIN rw0_rd_out[288]
    DIRECTION OUTPUT ;
    USE SIGNAL ;
    SHAPE ABUTMENT ;
    PORT
      LAYER M3 ;
      RECT 0 224.315 0.07 224.385 ;
    END
  END rw0_rd_out[288]
  PIN rw0_rd_out[289]
    DIRECTION OUTPUT ;
    USE SIGNAL ;
    SHAPE ABUTMENT ;
    PORT
      LAYER M3 ;
      RECT 0 224.595 0.07 224.665 ;
    END
  END rw0_rd_out[289]
  PIN rw0_rd_out[290]
    DIRECTION OUTPUT ;
    USE SIGNAL ;
    SHAPE ABUTMENT ;
    PORT
      LAYER M3 ;
      RECT 0 224.875 0.07 224.945 ;
    END
  END rw0_rd_out[290]
  PIN rw0_rd_out[291]
    DIRECTION OUTPUT ;
    USE SIGNAL ;
    SHAPE ABUTMENT ;
    PORT
      LAYER M3 ;
      RECT 0 225.155 0.07 225.225 ;
    END
  END rw0_rd_out[291]
  PIN rw0_rd_out[292]
    DIRECTION OUTPUT ;
    USE SIGNAL ;
    SHAPE ABUTMENT ;
    PORT
      LAYER M3 ;
      RECT 0 225.435 0.07 225.505 ;
    END
  END rw0_rd_out[292]
  PIN rw0_rd_out[293]
    DIRECTION OUTPUT ;
    USE SIGNAL ;
    SHAPE ABUTMENT ;
    PORT
      LAYER M3 ;
      RECT 0 225.715 0.07 225.785 ;
    END
  END rw0_rd_out[293]
  PIN rw0_rd_out[294]
    DIRECTION OUTPUT ;
    USE SIGNAL ;
    SHAPE ABUTMENT ;
    PORT
      LAYER M3 ;
      RECT 0 225.995 0.07 226.065 ;
    END
  END rw0_rd_out[294]
  PIN rw0_rd_out[295]
    DIRECTION OUTPUT ;
    USE SIGNAL ;
    SHAPE ABUTMENT ;
    PORT
      LAYER M3 ;
      RECT 0 226.275 0.07 226.345 ;
    END
  END rw0_rd_out[295]
  PIN rw0_rd_out[296]
    DIRECTION OUTPUT ;
    USE SIGNAL ;
    SHAPE ABUTMENT ;
    PORT
      LAYER M3 ;
      RECT 0 226.555 0.07 226.625 ;
    END
  END rw0_rd_out[296]
  PIN rw0_rd_out[297]
    DIRECTION OUTPUT ;
    USE SIGNAL ;
    SHAPE ABUTMENT ;
    PORT
      LAYER M3 ;
      RECT 0 226.835 0.07 226.905 ;
    END
  END rw0_rd_out[297]
  PIN rw0_rd_out[298]
    DIRECTION OUTPUT ;
    USE SIGNAL ;
    SHAPE ABUTMENT ;
    PORT
      LAYER M3 ;
      RECT 0 227.115 0.07 227.185 ;
    END
  END rw0_rd_out[298]
  PIN rw0_rd_out[299]
    DIRECTION OUTPUT ;
    USE SIGNAL ;
    SHAPE ABUTMENT ;
    PORT
      LAYER M3 ;
      RECT 0 227.395 0.07 227.465 ;
    END
  END rw0_rd_out[299]
  PIN rw0_rd_out[300]
    DIRECTION OUTPUT ;
    USE SIGNAL ;
    SHAPE ABUTMENT ;
    PORT
      LAYER M3 ;
      RECT 0 227.675 0.07 227.745 ;
    END
  END rw0_rd_out[300]
  PIN rw0_rd_out[301]
    DIRECTION OUTPUT ;
    USE SIGNAL ;
    SHAPE ABUTMENT ;
    PORT
      LAYER M3 ;
      RECT 0 227.955 0.07 228.025 ;
    END
  END rw0_rd_out[301]
  PIN rw0_rd_out[302]
    DIRECTION OUTPUT ;
    USE SIGNAL ;
    SHAPE ABUTMENT ;
    PORT
      LAYER M3 ;
      RECT 0 228.235 0.07 228.305 ;
    END
  END rw0_rd_out[302]
  PIN rw0_rd_out[303]
    DIRECTION OUTPUT ;
    USE SIGNAL ;
    SHAPE ABUTMENT ;
    PORT
      LAYER M3 ;
      RECT 0 228.515 0.07 228.585 ;
    END
  END rw0_rd_out[303]
  PIN rw0_rd_out[304]
    DIRECTION OUTPUT ;
    USE SIGNAL ;
    SHAPE ABUTMENT ;
    PORT
      LAYER M3 ;
      RECT 0 228.795 0.07 228.865 ;
    END
  END rw0_rd_out[304]
  PIN rw0_rd_out[305]
    DIRECTION OUTPUT ;
    USE SIGNAL ;
    SHAPE ABUTMENT ;
    PORT
      LAYER M3 ;
      RECT 0 229.075 0.07 229.145 ;
    END
  END rw0_rd_out[305]
  PIN rw0_rd_out[306]
    DIRECTION OUTPUT ;
    USE SIGNAL ;
    SHAPE ABUTMENT ;
    PORT
      LAYER M3 ;
      RECT 0 229.355 0.07 229.425 ;
    END
  END rw0_rd_out[306]
  PIN rw0_rd_out[307]
    DIRECTION OUTPUT ;
    USE SIGNAL ;
    SHAPE ABUTMENT ;
    PORT
      LAYER M3 ;
      RECT 0 229.635 0.07 229.705 ;
    END
  END rw0_rd_out[307]
  PIN rw0_rd_out[308]
    DIRECTION OUTPUT ;
    USE SIGNAL ;
    SHAPE ABUTMENT ;
    PORT
      LAYER M3 ;
      RECT 0 229.915 0.07 229.985 ;
    END
  END rw0_rd_out[308]
  PIN rw0_rd_out[309]
    DIRECTION OUTPUT ;
    USE SIGNAL ;
    SHAPE ABUTMENT ;
    PORT
      LAYER M3 ;
      RECT 0 230.195 0.07 230.265 ;
    END
  END rw0_rd_out[309]
  PIN rw0_rd_out[310]
    DIRECTION OUTPUT ;
    USE SIGNAL ;
    SHAPE ABUTMENT ;
    PORT
      LAYER M3 ;
      RECT 0 230.475 0.07 230.545 ;
    END
  END rw0_rd_out[310]
  PIN rw0_rd_out[311]
    DIRECTION OUTPUT ;
    USE SIGNAL ;
    SHAPE ABUTMENT ;
    PORT
      LAYER M3 ;
      RECT 0 230.755 0.07 230.825 ;
    END
  END rw0_rd_out[311]
  PIN rw0_rd_out[312]
    DIRECTION OUTPUT ;
    USE SIGNAL ;
    SHAPE ABUTMENT ;
    PORT
      LAYER M3 ;
      RECT 0 231.035 0.07 231.105 ;
    END
  END rw0_rd_out[312]
  PIN rw0_rd_out[313]
    DIRECTION OUTPUT ;
    USE SIGNAL ;
    SHAPE ABUTMENT ;
    PORT
      LAYER M3 ;
      RECT 0 231.315 0.07 231.385 ;
    END
  END rw0_rd_out[313]
  PIN rw0_rd_out[314]
    DIRECTION OUTPUT ;
    USE SIGNAL ;
    SHAPE ABUTMENT ;
    PORT
      LAYER M3 ;
      RECT 0 231.595 0.07 231.665 ;
    END
  END rw0_rd_out[314]
  PIN rw0_rd_out[315]
    DIRECTION OUTPUT ;
    USE SIGNAL ;
    SHAPE ABUTMENT ;
    PORT
      LAYER M3 ;
      RECT 0 231.875 0.07 231.945 ;
    END
  END rw0_rd_out[315]
  PIN rw0_rd_out[316]
    DIRECTION OUTPUT ;
    USE SIGNAL ;
    SHAPE ABUTMENT ;
    PORT
      LAYER M3 ;
      RECT 0 232.155 0.07 232.225 ;
    END
  END rw0_rd_out[316]
  PIN rw0_rd_out[317]
    DIRECTION OUTPUT ;
    USE SIGNAL ;
    SHAPE ABUTMENT ;
    PORT
      LAYER M3 ;
      RECT 0 232.435 0.07 232.505 ;
    END
  END rw0_rd_out[317]
  PIN rw0_rd_out[318]
    DIRECTION OUTPUT ;
    USE SIGNAL ;
    SHAPE ABUTMENT ;
    PORT
      LAYER M3 ;
      RECT 0 232.715 0.07 232.785 ;
    END
  END rw0_rd_out[318]
  PIN rw0_rd_out[319]
    DIRECTION OUTPUT ;
    USE SIGNAL ;
    SHAPE ABUTMENT ;
    PORT
      LAYER M3 ;
      RECT 0 232.995 0.07 233.065 ;
    END
  END rw0_rd_out[319]
  PIN rw0_rd_out[320]
    DIRECTION OUTPUT ;
    USE SIGNAL ;
    SHAPE ABUTMENT ;
    PORT
      LAYER M3 ;
      RECT 0 233.275 0.07 233.345 ;
    END
  END rw0_rd_out[320]
  PIN rw0_rd_out[321]
    DIRECTION OUTPUT ;
    USE SIGNAL ;
    SHAPE ABUTMENT ;
    PORT
      LAYER M3 ;
      RECT 0 233.555 0.07 233.625 ;
    END
  END rw0_rd_out[321]
  PIN rw0_rd_out[322]
    DIRECTION OUTPUT ;
    USE SIGNAL ;
    SHAPE ABUTMENT ;
    PORT
      LAYER M3 ;
      RECT 0 233.835 0.07 233.905 ;
    END
  END rw0_rd_out[322]
  PIN rw0_rd_out[323]
    DIRECTION OUTPUT ;
    USE SIGNAL ;
    SHAPE ABUTMENT ;
    PORT
      LAYER M3 ;
      RECT 0 234.115 0.07 234.185 ;
    END
  END rw0_rd_out[323]
  PIN rw0_rd_out[324]
    DIRECTION OUTPUT ;
    USE SIGNAL ;
    SHAPE ABUTMENT ;
    PORT
      LAYER M3 ;
      RECT 0 234.395 0.07 234.465 ;
    END
  END rw0_rd_out[324]
  PIN rw0_rd_out[325]
    DIRECTION OUTPUT ;
    USE SIGNAL ;
    SHAPE ABUTMENT ;
    PORT
      LAYER M3 ;
      RECT 0 234.675 0.07 234.745 ;
    END
  END rw0_rd_out[325]
  PIN rw0_rd_out[326]
    DIRECTION OUTPUT ;
    USE SIGNAL ;
    SHAPE ABUTMENT ;
    PORT
      LAYER M3 ;
      RECT 0 234.955 0.07 235.025 ;
    END
  END rw0_rd_out[326]
  PIN rw0_rd_out[327]
    DIRECTION OUTPUT ;
    USE SIGNAL ;
    SHAPE ABUTMENT ;
    PORT
      LAYER M3 ;
      RECT 0 235.235 0.07 235.305 ;
    END
  END rw0_rd_out[327]
  PIN rw0_rd_out[328]
    DIRECTION OUTPUT ;
    USE SIGNAL ;
    SHAPE ABUTMENT ;
    PORT
      LAYER M3 ;
      RECT 0 235.515 0.07 235.585 ;
    END
  END rw0_rd_out[328]
  PIN rw0_rd_out[329]
    DIRECTION OUTPUT ;
    USE SIGNAL ;
    SHAPE ABUTMENT ;
    PORT
      LAYER M3 ;
      RECT 0 235.795 0.07 235.865 ;
    END
  END rw0_rd_out[329]
  PIN rw0_rd_out[330]
    DIRECTION OUTPUT ;
    USE SIGNAL ;
    SHAPE ABUTMENT ;
    PORT
      LAYER M3 ;
      RECT 0 236.075 0.07 236.145 ;
    END
  END rw0_rd_out[330]
  PIN rw0_rd_out[331]
    DIRECTION OUTPUT ;
    USE SIGNAL ;
    SHAPE ABUTMENT ;
    PORT
      LAYER M3 ;
      RECT 0 236.355 0.07 236.425 ;
    END
  END rw0_rd_out[331]
  PIN rw0_rd_out[332]
    DIRECTION OUTPUT ;
    USE SIGNAL ;
    SHAPE ABUTMENT ;
    PORT
      LAYER M3 ;
      RECT 0 236.635 0.07 236.705 ;
    END
  END rw0_rd_out[332]
  PIN rw0_rd_out[333]
    DIRECTION OUTPUT ;
    USE SIGNAL ;
    SHAPE ABUTMENT ;
    PORT
      LAYER M3 ;
      RECT 0 236.915 0.07 236.985 ;
    END
  END rw0_rd_out[333]
  PIN rw0_rd_out[334]
    DIRECTION OUTPUT ;
    USE SIGNAL ;
    SHAPE ABUTMENT ;
    PORT
      LAYER M3 ;
      RECT 0 237.195 0.07 237.265 ;
    END
  END rw0_rd_out[334]
  PIN rw0_rd_out[335]
    DIRECTION OUTPUT ;
    USE SIGNAL ;
    SHAPE ABUTMENT ;
    PORT
      LAYER M3 ;
      RECT 0 237.475 0.07 237.545 ;
    END
  END rw0_rd_out[335]
  PIN rw0_rd_out[336]
    DIRECTION OUTPUT ;
    USE SIGNAL ;
    SHAPE ABUTMENT ;
    PORT
      LAYER M3 ;
      RECT 0 237.755 0.07 237.825 ;
    END
  END rw0_rd_out[336]
  PIN rw0_rd_out[337]
    DIRECTION OUTPUT ;
    USE SIGNAL ;
    SHAPE ABUTMENT ;
    PORT
      LAYER M3 ;
      RECT 0 238.035 0.07 238.105 ;
    END
  END rw0_rd_out[337]
  PIN rw0_rd_out[338]
    DIRECTION OUTPUT ;
    USE SIGNAL ;
    SHAPE ABUTMENT ;
    PORT
      LAYER M3 ;
      RECT 0 238.315 0.07 238.385 ;
    END
  END rw0_rd_out[338]
  PIN rw0_rd_out[339]
    DIRECTION OUTPUT ;
    USE SIGNAL ;
    SHAPE ABUTMENT ;
    PORT
      LAYER M3 ;
      RECT 0 238.595 0.07 238.665 ;
    END
  END rw0_rd_out[339]
  PIN rw0_rd_out[340]
    DIRECTION OUTPUT ;
    USE SIGNAL ;
    SHAPE ABUTMENT ;
    PORT
      LAYER M3 ;
      RECT 0 238.875 0.07 238.945 ;
    END
  END rw0_rd_out[340]
  PIN rw0_rd_out[341]
    DIRECTION OUTPUT ;
    USE SIGNAL ;
    SHAPE ABUTMENT ;
    PORT
      LAYER M3 ;
      RECT 0 239.155 0.07 239.225 ;
    END
  END rw0_rd_out[341]
  PIN rw0_rd_out[342]
    DIRECTION OUTPUT ;
    USE SIGNAL ;
    SHAPE ABUTMENT ;
    PORT
      LAYER M3 ;
      RECT 0 239.435 0.07 239.505 ;
    END
  END rw0_rd_out[342]
  PIN rw0_rd_out[343]
    DIRECTION OUTPUT ;
    USE SIGNAL ;
    SHAPE ABUTMENT ;
    PORT
      LAYER M3 ;
      RECT 0 239.715 0.07 239.785 ;
    END
  END rw0_rd_out[343]
  PIN rw0_rd_out[344]
    DIRECTION OUTPUT ;
    USE SIGNAL ;
    SHAPE ABUTMENT ;
    PORT
      LAYER M3 ;
      RECT 0 239.995 0.07 240.065 ;
    END
  END rw0_rd_out[344]
  PIN rw0_rd_out[345]
    DIRECTION OUTPUT ;
    USE SIGNAL ;
    SHAPE ABUTMENT ;
    PORT
      LAYER M3 ;
      RECT 0 240.275 0.07 240.345 ;
    END
  END rw0_rd_out[345]
  PIN rw0_rd_out[346]
    DIRECTION OUTPUT ;
    USE SIGNAL ;
    SHAPE ABUTMENT ;
    PORT
      LAYER M3 ;
      RECT 0 240.555 0.07 240.625 ;
    END
  END rw0_rd_out[346]
  PIN rw0_rd_out[347]
    DIRECTION OUTPUT ;
    USE SIGNAL ;
    SHAPE ABUTMENT ;
    PORT
      LAYER M3 ;
      RECT 0 240.835 0.07 240.905 ;
    END
  END rw0_rd_out[347]
  PIN rw0_rd_out[348]
    DIRECTION OUTPUT ;
    USE SIGNAL ;
    SHAPE ABUTMENT ;
    PORT
      LAYER M3 ;
      RECT 0 241.115 0.07 241.185 ;
    END
  END rw0_rd_out[348]
  PIN rw0_rd_out[349]
    DIRECTION OUTPUT ;
    USE SIGNAL ;
    SHAPE ABUTMENT ;
    PORT
      LAYER M3 ;
      RECT 0 241.395 0.07 241.465 ;
    END
  END rw0_rd_out[349]
  PIN rw0_rd_out[350]
    DIRECTION OUTPUT ;
    USE SIGNAL ;
    SHAPE ABUTMENT ;
    PORT
      LAYER M3 ;
      RECT 0 241.675 0.07 241.745 ;
    END
  END rw0_rd_out[350]
  PIN rw0_rd_out[351]
    DIRECTION OUTPUT ;
    USE SIGNAL ;
    SHAPE ABUTMENT ;
    PORT
      LAYER M3 ;
      RECT 0 241.955 0.07 242.025 ;
    END
  END rw0_rd_out[351]
  PIN rw0_rd_out[352]
    DIRECTION OUTPUT ;
    USE SIGNAL ;
    SHAPE ABUTMENT ;
    PORT
      LAYER M3 ;
      RECT 0 242.235 0.07 242.305 ;
    END
  END rw0_rd_out[352]
  PIN rw0_rd_out[353]
    DIRECTION OUTPUT ;
    USE SIGNAL ;
    SHAPE ABUTMENT ;
    PORT
      LAYER M3 ;
      RECT 0 242.515 0.07 242.585 ;
    END
  END rw0_rd_out[353]
  PIN rw0_rd_out[354]
    DIRECTION OUTPUT ;
    USE SIGNAL ;
    SHAPE ABUTMENT ;
    PORT
      LAYER M3 ;
      RECT 0 242.795 0.07 242.865 ;
    END
  END rw0_rd_out[354]
  PIN rw0_rd_out[355]
    DIRECTION OUTPUT ;
    USE SIGNAL ;
    SHAPE ABUTMENT ;
    PORT
      LAYER M3 ;
      RECT 0 243.075 0.07 243.145 ;
    END
  END rw0_rd_out[355]
  PIN rw0_rd_out[356]
    DIRECTION OUTPUT ;
    USE SIGNAL ;
    SHAPE ABUTMENT ;
    PORT
      LAYER M3 ;
      RECT 0 243.355 0.07 243.425 ;
    END
  END rw0_rd_out[356]
  PIN rw0_rd_out[357]
    DIRECTION OUTPUT ;
    USE SIGNAL ;
    SHAPE ABUTMENT ;
    PORT
      LAYER M3 ;
      RECT 0 243.635 0.07 243.705 ;
    END
  END rw0_rd_out[357]
  PIN rw0_rd_out[358]
    DIRECTION OUTPUT ;
    USE SIGNAL ;
    SHAPE ABUTMENT ;
    PORT
      LAYER M3 ;
      RECT 0 243.915 0.07 243.985 ;
    END
  END rw0_rd_out[358]
  PIN rw0_rd_out[359]
    DIRECTION OUTPUT ;
    USE SIGNAL ;
    SHAPE ABUTMENT ;
    PORT
      LAYER M3 ;
      RECT 0 244.195 0.07 244.265 ;
    END
  END rw0_rd_out[359]
  PIN rw0_rd_out[360]
    DIRECTION OUTPUT ;
    USE SIGNAL ;
    SHAPE ABUTMENT ;
    PORT
      LAYER M3 ;
      RECT 0 244.475 0.07 244.545 ;
    END
  END rw0_rd_out[360]
  PIN rw0_rd_out[361]
    DIRECTION OUTPUT ;
    USE SIGNAL ;
    SHAPE ABUTMENT ;
    PORT
      LAYER M3 ;
      RECT 0 244.755 0.07 244.825 ;
    END
  END rw0_rd_out[361]
  PIN rw0_rd_out[362]
    DIRECTION OUTPUT ;
    USE SIGNAL ;
    SHAPE ABUTMENT ;
    PORT
      LAYER M3 ;
      RECT 0 245.035 0.07 245.105 ;
    END
  END rw0_rd_out[362]
  PIN rw0_rd_out[363]
    DIRECTION OUTPUT ;
    USE SIGNAL ;
    SHAPE ABUTMENT ;
    PORT
      LAYER M3 ;
      RECT 0 245.315 0.07 245.385 ;
    END
  END rw0_rd_out[363]
  PIN rw0_rd_out[364]
    DIRECTION OUTPUT ;
    USE SIGNAL ;
    SHAPE ABUTMENT ;
    PORT
      LAYER M3 ;
      RECT 0 245.595 0.07 245.665 ;
    END
  END rw0_rd_out[364]
  PIN rw0_rd_out[365]
    DIRECTION OUTPUT ;
    USE SIGNAL ;
    SHAPE ABUTMENT ;
    PORT
      LAYER M3 ;
      RECT 0 245.875 0.07 245.945 ;
    END
  END rw0_rd_out[365]
  PIN rw0_rd_out[366]
    DIRECTION OUTPUT ;
    USE SIGNAL ;
    SHAPE ABUTMENT ;
    PORT
      LAYER M3 ;
      RECT 0 246.155 0.07 246.225 ;
    END
  END rw0_rd_out[366]
  PIN rw0_rd_out[367]
    DIRECTION OUTPUT ;
    USE SIGNAL ;
    SHAPE ABUTMENT ;
    PORT
      LAYER M3 ;
      RECT 0 246.435 0.07 246.505 ;
    END
  END rw0_rd_out[367]
  PIN rw0_rd_out[368]
    DIRECTION OUTPUT ;
    USE SIGNAL ;
    SHAPE ABUTMENT ;
    PORT
      LAYER M3 ;
      RECT 0 246.715 0.07 246.785 ;
    END
  END rw0_rd_out[368]
  PIN rw0_rd_out[369]
    DIRECTION OUTPUT ;
    USE SIGNAL ;
    SHAPE ABUTMENT ;
    PORT
      LAYER M3 ;
      RECT 0 246.995 0.07 247.065 ;
    END
  END rw0_rd_out[369]
  PIN rw0_rd_out[370]
    DIRECTION OUTPUT ;
    USE SIGNAL ;
    SHAPE ABUTMENT ;
    PORT
      LAYER M3 ;
      RECT 0 247.275 0.07 247.345 ;
    END
  END rw0_rd_out[370]
  PIN rw0_rd_out[371]
    DIRECTION OUTPUT ;
    USE SIGNAL ;
    SHAPE ABUTMENT ;
    PORT
      LAYER M3 ;
      RECT 0 247.555 0.07 247.625 ;
    END
  END rw0_rd_out[371]
  PIN rw0_rd_out[372]
    DIRECTION OUTPUT ;
    USE SIGNAL ;
    SHAPE ABUTMENT ;
    PORT
      LAYER M3 ;
      RECT 0 247.835 0.07 247.905 ;
    END
  END rw0_rd_out[372]
  PIN rw0_rd_out[373]
    DIRECTION OUTPUT ;
    USE SIGNAL ;
    SHAPE ABUTMENT ;
    PORT
      LAYER M3 ;
      RECT 0 248.115 0.07 248.185 ;
    END
  END rw0_rd_out[373]
  PIN rw0_rd_out[374]
    DIRECTION OUTPUT ;
    USE SIGNAL ;
    SHAPE ABUTMENT ;
    PORT
      LAYER M3 ;
      RECT 0 248.395 0.07 248.465 ;
    END
  END rw0_rd_out[374]
  PIN rw0_rd_out[375]
    DIRECTION OUTPUT ;
    USE SIGNAL ;
    SHAPE ABUTMENT ;
    PORT
      LAYER M3 ;
      RECT 0 248.675 0.07 248.745 ;
    END
  END rw0_rd_out[375]
  PIN rw0_rd_out[376]
    DIRECTION OUTPUT ;
    USE SIGNAL ;
    SHAPE ABUTMENT ;
    PORT
      LAYER M3 ;
      RECT 0 248.955 0.07 249.025 ;
    END
  END rw0_rd_out[376]
  PIN rw0_rd_out[377]
    DIRECTION OUTPUT ;
    USE SIGNAL ;
    SHAPE ABUTMENT ;
    PORT
      LAYER M3 ;
      RECT 0 249.235 0.07 249.305 ;
    END
  END rw0_rd_out[377]
  PIN rw0_rd_out[378]
    DIRECTION OUTPUT ;
    USE SIGNAL ;
    SHAPE ABUTMENT ;
    PORT
      LAYER M3 ;
      RECT 0 249.515 0.07 249.585 ;
    END
  END rw0_rd_out[378]
  PIN rw0_rd_out[379]
    DIRECTION OUTPUT ;
    USE SIGNAL ;
    SHAPE ABUTMENT ;
    PORT
      LAYER M3 ;
      RECT 0 249.795 0.07 249.865 ;
    END
  END rw0_rd_out[379]
  PIN rw0_rd_out[380]
    DIRECTION OUTPUT ;
    USE SIGNAL ;
    SHAPE ABUTMENT ;
    PORT
      LAYER M3 ;
      RECT 0 250.075 0.07 250.145 ;
    END
  END rw0_rd_out[380]
  PIN rw0_rd_out[381]
    DIRECTION OUTPUT ;
    USE SIGNAL ;
    SHAPE ABUTMENT ;
    PORT
      LAYER M3 ;
      RECT 0 250.355 0.07 250.425 ;
    END
  END rw0_rd_out[381]
  PIN rw0_rd_out[382]
    DIRECTION OUTPUT ;
    USE SIGNAL ;
    SHAPE ABUTMENT ;
    PORT
      LAYER M3 ;
      RECT 0 250.635 0.07 250.705 ;
    END
  END rw0_rd_out[382]
  PIN rw0_rd_out[383]
    DIRECTION OUTPUT ;
    USE SIGNAL ;
    SHAPE ABUTMENT ;
    PORT
      LAYER M3 ;
      RECT 0 250.915 0.07 250.985 ;
    END
  END rw0_rd_out[383]
  PIN rw0_rd_out[384]
    DIRECTION OUTPUT ;
    USE SIGNAL ;
    SHAPE ABUTMENT ;
    PORT
      LAYER M3 ;
      RECT 0 251.195 0.07 251.265 ;
    END
  END rw0_rd_out[384]
  PIN rw0_rd_out[385]
    DIRECTION OUTPUT ;
    USE SIGNAL ;
    SHAPE ABUTMENT ;
    PORT
      LAYER M3 ;
      RECT 0 251.475 0.07 251.545 ;
    END
  END rw0_rd_out[385]
  PIN rw0_rd_out[386]
    DIRECTION OUTPUT ;
    USE SIGNAL ;
    SHAPE ABUTMENT ;
    PORT
      LAYER M3 ;
      RECT 0 251.755 0.07 251.825 ;
    END
  END rw0_rd_out[386]
  PIN rw0_rd_out[387]
    DIRECTION OUTPUT ;
    USE SIGNAL ;
    SHAPE ABUTMENT ;
    PORT
      LAYER M3 ;
      RECT 0 252.035 0.07 252.105 ;
    END
  END rw0_rd_out[387]
  PIN rw0_rd_out[388]
    DIRECTION OUTPUT ;
    USE SIGNAL ;
    SHAPE ABUTMENT ;
    PORT
      LAYER M3 ;
      RECT 0 252.315 0.07 252.385 ;
    END
  END rw0_rd_out[388]
  PIN rw0_rd_out[389]
    DIRECTION OUTPUT ;
    USE SIGNAL ;
    SHAPE ABUTMENT ;
    PORT
      LAYER M3 ;
      RECT 0 252.595 0.07 252.665 ;
    END
  END rw0_rd_out[389]
  PIN rw0_rd_out[390]
    DIRECTION OUTPUT ;
    USE SIGNAL ;
    SHAPE ABUTMENT ;
    PORT
      LAYER M3 ;
      RECT 0 252.875 0.07 252.945 ;
    END
  END rw0_rd_out[390]
  PIN rw0_rd_out[391]
    DIRECTION OUTPUT ;
    USE SIGNAL ;
    SHAPE ABUTMENT ;
    PORT
      LAYER M3 ;
      RECT 0 253.155 0.07 253.225 ;
    END
  END rw0_rd_out[391]
  PIN rw0_rd_out[392]
    DIRECTION OUTPUT ;
    USE SIGNAL ;
    SHAPE ABUTMENT ;
    PORT
      LAYER M3 ;
      RECT 0 253.435 0.07 253.505 ;
    END
  END rw0_rd_out[392]
  PIN rw0_rd_out[393]
    DIRECTION OUTPUT ;
    USE SIGNAL ;
    SHAPE ABUTMENT ;
    PORT
      LAYER M3 ;
      RECT 0 253.715 0.07 253.785 ;
    END
  END rw0_rd_out[393]
  PIN rw0_rd_out[394]
    DIRECTION OUTPUT ;
    USE SIGNAL ;
    SHAPE ABUTMENT ;
    PORT
      LAYER M3 ;
      RECT 0 253.995 0.07 254.065 ;
    END
  END rw0_rd_out[394]
  PIN rw0_rd_out[395]
    DIRECTION OUTPUT ;
    USE SIGNAL ;
    SHAPE ABUTMENT ;
    PORT
      LAYER M3 ;
      RECT 0 254.275 0.07 254.345 ;
    END
  END rw0_rd_out[395]
  PIN rw0_rd_out[396]
    DIRECTION OUTPUT ;
    USE SIGNAL ;
    SHAPE ABUTMENT ;
    PORT
      LAYER M3 ;
      RECT 0 254.555 0.07 254.625 ;
    END
  END rw0_rd_out[396]
  PIN rw0_rd_out[397]
    DIRECTION OUTPUT ;
    USE SIGNAL ;
    SHAPE ABUTMENT ;
    PORT
      LAYER M3 ;
      RECT 0 254.835 0.07 254.905 ;
    END
  END rw0_rd_out[397]
  PIN rw0_rd_out[398]
    DIRECTION OUTPUT ;
    USE SIGNAL ;
    SHAPE ABUTMENT ;
    PORT
      LAYER M3 ;
      RECT 0 255.115 0.07 255.185 ;
    END
  END rw0_rd_out[398]
  PIN rw0_rd_out[399]
    DIRECTION OUTPUT ;
    USE SIGNAL ;
    SHAPE ABUTMENT ;
    PORT
      LAYER M3 ;
      RECT 0 255.395 0.07 255.465 ;
    END
  END rw0_rd_out[399]
  PIN rw0_rd_out[400]
    DIRECTION OUTPUT ;
    USE SIGNAL ;
    SHAPE ABUTMENT ;
    PORT
      LAYER M3 ;
      RECT 0 255.675 0.07 255.745 ;
    END
  END rw0_rd_out[400]
  PIN rw0_rd_out[401]
    DIRECTION OUTPUT ;
    USE SIGNAL ;
    SHAPE ABUTMENT ;
    PORT
      LAYER M3 ;
      RECT 0 255.955 0.07 256.025 ;
    END
  END rw0_rd_out[401]
  PIN rw0_rd_out[402]
    DIRECTION OUTPUT ;
    USE SIGNAL ;
    SHAPE ABUTMENT ;
    PORT
      LAYER M3 ;
      RECT 0 256.235 0.07 256.305 ;
    END
  END rw0_rd_out[402]
  PIN rw0_rd_out[403]
    DIRECTION OUTPUT ;
    USE SIGNAL ;
    SHAPE ABUTMENT ;
    PORT
      LAYER M3 ;
      RECT 0 256.515 0.07 256.585 ;
    END
  END rw0_rd_out[403]
  PIN rw0_rd_out[404]
    DIRECTION OUTPUT ;
    USE SIGNAL ;
    SHAPE ABUTMENT ;
    PORT
      LAYER M3 ;
      RECT 0 256.795 0.07 256.865 ;
    END
  END rw0_rd_out[404]
  PIN rw0_rd_out[405]
    DIRECTION OUTPUT ;
    USE SIGNAL ;
    SHAPE ABUTMENT ;
    PORT
      LAYER M3 ;
      RECT 0 257.075 0.07 257.145 ;
    END
  END rw0_rd_out[405]
  PIN rw0_rd_out[406]
    DIRECTION OUTPUT ;
    USE SIGNAL ;
    SHAPE ABUTMENT ;
    PORT
      LAYER M3 ;
      RECT 0 257.355 0.07 257.425 ;
    END
  END rw0_rd_out[406]
  PIN rw0_rd_out[407]
    DIRECTION OUTPUT ;
    USE SIGNAL ;
    SHAPE ABUTMENT ;
    PORT
      LAYER M3 ;
      RECT 0 257.635 0.07 257.705 ;
    END
  END rw0_rd_out[407]
  PIN rw0_rd_out[408]
    DIRECTION OUTPUT ;
    USE SIGNAL ;
    SHAPE ABUTMENT ;
    PORT
      LAYER M3 ;
      RECT 0 257.915 0.07 257.985 ;
    END
  END rw0_rd_out[408]
  PIN rw0_rd_out[409]
    DIRECTION OUTPUT ;
    USE SIGNAL ;
    SHAPE ABUTMENT ;
    PORT
      LAYER M3 ;
      RECT 0 258.195 0.07 258.265 ;
    END
  END rw0_rd_out[409]
  PIN rw0_rd_out[410]
    DIRECTION OUTPUT ;
    USE SIGNAL ;
    SHAPE ABUTMENT ;
    PORT
      LAYER M3 ;
      RECT 0 258.475 0.07 258.545 ;
    END
  END rw0_rd_out[410]
  PIN rw0_rd_out[411]
    DIRECTION OUTPUT ;
    USE SIGNAL ;
    SHAPE ABUTMENT ;
    PORT
      LAYER M3 ;
      RECT 0 258.755 0.07 258.825 ;
    END
  END rw0_rd_out[411]
  PIN rw0_rd_out[412]
    DIRECTION OUTPUT ;
    USE SIGNAL ;
    SHAPE ABUTMENT ;
    PORT
      LAYER M3 ;
      RECT 0 259.035 0.07 259.105 ;
    END
  END rw0_rd_out[412]
  PIN rw0_rd_out[413]
    DIRECTION OUTPUT ;
    USE SIGNAL ;
    SHAPE ABUTMENT ;
    PORT
      LAYER M3 ;
      RECT 0 259.315 0.07 259.385 ;
    END
  END rw0_rd_out[413]
  PIN rw0_rd_out[414]
    DIRECTION OUTPUT ;
    USE SIGNAL ;
    SHAPE ABUTMENT ;
    PORT
      LAYER M3 ;
      RECT 0 259.595 0.07 259.665 ;
    END
  END rw0_rd_out[414]
  PIN rw0_rd_out[415]
    DIRECTION OUTPUT ;
    USE SIGNAL ;
    SHAPE ABUTMENT ;
    PORT
      LAYER M3 ;
      RECT 0 259.875 0.07 259.945 ;
    END
  END rw0_rd_out[415]
  PIN rw0_rd_out[416]
    DIRECTION OUTPUT ;
    USE SIGNAL ;
    SHAPE ABUTMENT ;
    PORT
      LAYER M3 ;
      RECT 0 260.155 0.07 260.225 ;
    END
  END rw0_rd_out[416]
  PIN rw0_rd_out[417]
    DIRECTION OUTPUT ;
    USE SIGNAL ;
    SHAPE ABUTMENT ;
    PORT
      LAYER M3 ;
      RECT 0 260.435 0.07 260.505 ;
    END
  END rw0_rd_out[417]
  PIN rw0_rd_out[418]
    DIRECTION OUTPUT ;
    USE SIGNAL ;
    SHAPE ABUTMENT ;
    PORT
      LAYER M3 ;
      RECT 0 260.715 0.07 260.785 ;
    END
  END rw0_rd_out[418]
  PIN rw0_rd_out[419]
    DIRECTION OUTPUT ;
    USE SIGNAL ;
    SHAPE ABUTMENT ;
    PORT
      LAYER M3 ;
      RECT 0 260.995 0.07 261.065 ;
    END
  END rw0_rd_out[419]
  PIN rw0_rd_out[420]
    DIRECTION OUTPUT ;
    USE SIGNAL ;
    SHAPE ABUTMENT ;
    PORT
      LAYER M3 ;
      RECT 0 261.275 0.07 261.345 ;
    END
  END rw0_rd_out[420]
  PIN rw0_rd_out[421]
    DIRECTION OUTPUT ;
    USE SIGNAL ;
    SHAPE ABUTMENT ;
    PORT
      LAYER M3 ;
      RECT 0 261.555 0.07 261.625 ;
    END
  END rw0_rd_out[421]
  PIN rw0_rd_out[422]
    DIRECTION OUTPUT ;
    USE SIGNAL ;
    SHAPE ABUTMENT ;
    PORT
      LAYER M3 ;
      RECT 0 261.835 0.07 261.905 ;
    END
  END rw0_rd_out[422]
  PIN rw0_rd_out[423]
    DIRECTION OUTPUT ;
    USE SIGNAL ;
    SHAPE ABUTMENT ;
    PORT
      LAYER M3 ;
      RECT 0 262.115 0.07 262.185 ;
    END
  END rw0_rd_out[423]
  PIN rw0_rd_out[424]
    DIRECTION OUTPUT ;
    USE SIGNAL ;
    SHAPE ABUTMENT ;
    PORT
      LAYER M3 ;
      RECT 0 262.395 0.07 262.465 ;
    END
  END rw0_rd_out[424]
  PIN rw0_rd_out[425]
    DIRECTION OUTPUT ;
    USE SIGNAL ;
    SHAPE ABUTMENT ;
    PORT
      LAYER M3 ;
      RECT 0 262.675 0.07 262.745 ;
    END
  END rw0_rd_out[425]
  PIN rw0_rd_out[426]
    DIRECTION OUTPUT ;
    USE SIGNAL ;
    SHAPE ABUTMENT ;
    PORT
      LAYER M3 ;
      RECT 0 262.955 0.07 263.025 ;
    END
  END rw0_rd_out[426]
  PIN rw0_rd_out[427]
    DIRECTION OUTPUT ;
    USE SIGNAL ;
    SHAPE ABUTMENT ;
    PORT
      LAYER M3 ;
      RECT 0 263.235 0.07 263.305 ;
    END
  END rw0_rd_out[427]
  PIN rw0_rd_out[428]
    DIRECTION OUTPUT ;
    USE SIGNAL ;
    SHAPE ABUTMENT ;
    PORT
      LAYER M3 ;
      RECT 0 263.515 0.07 263.585 ;
    END
  END rw0_rd_out[428]
  PIN rw0_rd_out[429]
    DIRECTION OUTPUT ;
    USE SIGNAL ;
    SHAPE ABUTMENT ;
    PORT
      LAYER M3 ;
      RECT 0 263.795 0.07 263.865 ;
    END
  END rw0_rd_out[429]
  PIN rw0_rd_out[430]
    DIRECTION OUTPUT ;
    USE SIGNAL ;
    SHAPE ABUTMENT ;
    PORT
      LAYER M3 ;
      RECT 0 264.075 0.07 264.145 ;
    END
  END rw0_rd_out[430]
  PIN rw0_rd_out[431]
    DIRECTION OUTPUT ;
    USE SIGNAL ;
    SHAPE ABUTMENT ;
    PORT
      LAYER M3 ;
      RECT 0 264.355 0.07 264.425 ;
    END
  END rw0_rd_out[431]
  PIN rw0_rd_out[432]
    DIRECTION OUTPUT ;
    USE SIGNAL ;
    SHAPE ABUTMENT ;
    PORT
      LAYER M3 ;
      RECT 0 264.635 0.07 264.705 ;
    END
  END rw0_rd_out[432]
  PIN rw0_rd_out[433]
    DIRECTION OUTPUT ;
    USE SIGNAL ;
    SHAPE ABUTMENT ;
    PORT
      LAYER M3 ;
      RECT 0 264.915 0.07 264.985 ;
    END
  END rw0_rd_out[433]
  PIN rw0_rd_out[434]
    DIRECTION OUTPUT ;
    USE SIGNAL ;
    SHAPE ABUTMENT ;
    PORT
      LAYER M3 ;
      RECT 0 265.195 0.07 265.265 ;
    END
  END rw0_rd_out[434]
  PIN rw0_rd_out[435]
    DIRECTION OUTPUT ;
    USE SIGNAL ;
    SHAPE ABUTMENT ;
    PORT
      LAYER M3 ;
      RECT 0 265.475 0.07 265.545 ;
    END
  END rw0_rd_out[435]
  PIN rw0_rd_out[436]
    DIRECTION OUTPUT ;
    USE SIGNAL ;
    SHAPE ABUTMENT ;
    PORT
      LAYER M3 ;
      RECT 0 265.755 0.07 265.825 ;
    END
  END rw0_rd_out[436]
  PIN rw0_rd_out[437]
    DIRECTION OUTPUT ;
    USE SIGNAL ;
    SHAPE ABUTMENT ;
    PORT
      LAYER M3 ;
      RECT 0 266.035 0.07 266.105 ;
    END
  END rw0_rd_out[437]
  PIN rw0_rd_out[438]
    DIRECTION OUTPUT ;
    USE SIGNAL ;
    SHAPE ABUTMENT ;
    PORT
      LAYER M3 ;
      RECT 0 266.315 0.07 266.385 ;
    END
  END rw0_rd_out[438]
  PIN rw0_rd_out[439]
    DIRECTION OUTPUT ;
    USE SIGNAL ;
    SHAPE ABUTMENT ;
    PORT
      LAYER M3 ;
      RECT 0 266.595 0.07 266.665 ;
    END
  END rw0_rd_out[439]
  PIN rw0_rd_out[440]
    DIRECTION OUTPUT ;
    USE SIGNAL ;
    SHAPE ABUTMENT ;
    PORT
      LAYER M3 ;
      RECT 0 266.875 0.07 266.945 ;
    END
  END rw0_rd_out[440]
  PIN rw0_rd_out[441]
    DIRECTION OUTPUT ;
    USE SIGNAL ;
    SHAPE ABUTMENT ;
    PORT
      LAYER M3 ;
      RECT 0 267.155 0.07 267.225 ;
    END
  END rw0_rd_out[441]
  PIN rw0_rd_out[442]
    DIRECTION OUTPUT ;
    USE SIGNAL ;
    SHAPE ABUTMENT ;
    PORT
      LAYER M3 ;
      RECT 0 267.435 0.07 267.505 ;
    END
  END rw0_rd_out[442]
  PIN rw0_rd_out[443]
    DIRECTION OUTPUT ;
    USE SIGNAL ;
    SHAPE ABUTMENT ;
    PORT
      LAYER M3 ;
      RECT 0 267.715 0.07 267.785 ;
    END
  END rw0_rd_out[443]
  PIN rw0_rd_out[444]
    DIRECTION OUTPUT ;
    USE SIGNAL ;
    SHAPE ABUTMENT ;
    PORT
      LAYER M3 ;
      RECT 0 267.995 0.07 268.065 ;
    END
  END rw0_rd_out[444]
  PIN rw0_rd_out[445]
    DIRECTION OUTPUT ;
    USE SIGNAL ;
    SHAPE ABUTMENT ;
    PORT
      LAYER M3 ;
      RECT 0 268.275 0.07 268.345 ;
    END
  END rw0_rd_out[445]
  PIN rw0_rd_out[446]
    DIRECTION OUTPUT ;
    USE SIGNAL ;
    SHAPE ABUTMENT ;
    PORT
      LAYER M3 ;
      RECT 0 268.555 0.07 268.625 ;
    END
  END rw0_rd_out[446]
  PIN rw0_rd_out[447]
    DIRECTION OUTPUT ;
    USE SIGNAL ;
    SHAPE ABUTMENT ;
    PORT
      LAYER M3 ;
      RECT 0 268.835 0.07 268.905 ;
    END
  END rw0_rd_out[447]
  PIN rw0_rd_out[448]
    DIRECTION OUTPUT ;
    USE SIGNAL ;
    SHAPE ABUTMENT ;
    PORT
      LAYER M3 ;
      RECT 0 269.115 0.07 269.185 ;
    END
  END rw0_rd_out[448]
  PIN rw0_rd_out[449]
    DIRECTION OUTPUT ;
    USE SIGNAL ;
    SHAPE ABUTMENT ;
    PORT
      LAYER M3 ;
      RECT 0 269.395 0.07 269.465 ;
    END
  END rw0_rd_out[449]
  PIN rw0_rd_out[450]
    DIRECTION OUTPUT ;
    USE SIGNAL ;
    SHAPE ABUTMENT ;
    PORT
      LAYER M3 ;
      RECT 0 269.675 0.07 269.745 ;
    END
  END rw0_rd_out[450]
  PIN rw0_rd_out[451]
    DIRECTION OUTPUT ;
    USE SIGNAL ;
    SHAPE ABUTMENT ;
    PORT
      LAYER M3 ;
      RECT 0 269.955 0.07 270.025 ;
    END
  END rw0_rd_out[451]
  PIN rw0_rd_out[452]
    DIRECTION OUTPUT ;
    USE SIGNAL ;
    SHAPE ABUTMENT ;
    PORT
      LAYER M3 ;
      RECT 0 270.235 0.07 270.305 ;
    END
  END rw0_rd_out[452]
  PIN rw0_rd_out[453]
    DIRECTION OUTPUT ;
    USE SIGNAL ;
    SHAPE ABUTMENT ;
    PORT
      LAYER M3 ;
      RECT 0 270.515 0.07 270.585 ;
    END
  END rw0_rd_out[453]
  PIN rw0_rd_out[454]
    DIRECTION OUTPUT ;
    USE SIGNAL ;
    SHAPE ABUTMENT ;
    PORT
      LAYER M3 ;
      RECT 0 270.795 0.07 270.865 ;
    END
  END rw0_rd_out[454]
  PIN rw0_rd_out[455]
    DIRECTION OUTPUT ;
    USE SIGNAL ;
    SHAPE ABUTMENT ;
    PORT
      LAYER M3 ;
      RECT 0 271.075 0.07 271.145 ;
    END
  END rw0_rd_out[455]
  PIN rw0_rd_out[456]
    DIRECTION OUTPUT ;
    USE SIGNAL ;
    SHAPE ABUTMENT ;
    PORT
      LAYER M3 ;
      RECT 0 271.355 0.07 271.425 ;
    END
  END rw0_rd_out[456]
  PIN rw0_rd_out[457]
    DIRECTION OUTPUT ;
    USE SIGNAL ;
    SHAPE ABUTMENT ;
    PORT
      LAYER M3 ;
      RECT 0 271.635 0.07 271.705 ;
    END
  END rw0_rd_out[457]
  PIN rw0_rd_out[458]
    DIRECTION OUTPUT ;
    USE SIGNAL ;
    SHAPE ABUTMENT ;
    PORT
      LAYER M3 ;
      RECT 0 271.915 0.07 271.985 ;
    END
  END rw0_rd_out[458]
  PIN rw0_rd_out[459]
    DIRECTION OUTPUT ;
    USE SIGNAL ;
    SHAPE ABUTMENT ;
    PORT
      LAYER M3 ;
      RECT 0 272.195 0.07 272.265 ;
    END
  END rw0_rd_out[459]
  PIN rw0_rd_out[460]
    DIRECTION OUTPUT ;
    USE SIGNAL ;
    SHAPE ABUTMENT ;
    PORT
      LAYER M3 ;
      RECT 0 272.475 0.07 272.545 ;
    END
  END rw0_rd_out[460]
  PIN rw0_rd_out[461]
    DIRECTION OUTPUT ;
    USE SIGNAL ;
    SHAPE ABUTMENT ;
    PORT
      LAYER M3 ;
      RECT 0 272.755 0.07 272.825 ;
    END
  END rw0_rd_out[461]
  PIN rw0_rd_out[462]
    DIRECTION OUTPUT ;
    USE SIGNAL ;
    SHAPE ABUTMENT ;
    PORT
      LAYER M3 ;
      RECT 0 273.035 0.07 273.105 ;
    END
  END rw0_rd_out[462]
  PIN rw0_rd_out[463]
    DIRECTION OUTPUT ;
    USE SIGNAL ;
    SHAPE ABUTMENT ;
    PORT
      LAYER M3 ;
      RECT 0 273.315 0.07 273.385 ;
    END
  END rw0_rd_out[463]
  PIN rw0_rd_out[464]
    DIRECTION OUTPUT ;
    USE SIGNAL ;
    SHAPE ABUTMENT ;
    PORT
      LAYER M3 ;
      RECT 0 273.595 0.07 273.665 ;
    END
  END rw0_rd_out[464]
  PIN rw0_rd_out[465]
    DIRECTION OUTPUT ;
    USE SIGNAL ;
    SHAPE ABUTMENT ;
    PORT
      LAYER M3 ;
      RECT 0 273.875 0.07 273.945 ;
    END
  END rw0_rd_out[465]
  PIN rw0_rd_out[466]
    DIRECTION OUTPUT ;
    USE SIGNAL ;
    SHAPE ABUTMENT ;
    PORT
      LAYER M3 ;
      RECT 0 274.155 0.07 274.225 ;
    END
  END rw0_rd_out[466]
  PIN rw0_rd_out[467]
    DIRECTION OUTPUT ;
    USE SIGNAL ;
    SHAPE ABUTMENT ;
    PORT
      LAYER M3 ;
      RECT 0 274.435 0.07 274.505 ;
    END
  END rw0_rd_out[467]
  PIN rw0_rd_out[468]
    DIRECTION OUTPUT ;
    USE SIGNAL ;
    SHAPE ABUTMENT ;
    PORT
      LAYER M3 ;
      RECT 0 274.715 0.07 274.785 ;
    END
  END rw0_rd_out[468]
  PIN rw0_rd_out[469]
    DIRECTION OUTPUT ;
    USE SIGNAL ;
    SHAPE ABUTMENT ;
    PORT
      LAYER M3 ;
      RECT 0 274.995 0.07 275.065 ;
    END
  END rw0_rd_out[469]
  PIN rw0_rd_out[470]
    DIRECTION OUTPUT ;
    USE SIGNAL ;
    SHAPE ABUTMENT ;
    PORT
      LAYER M3 ;
      RECT 0 275.275 0.07 275.345 ;
    END
  END rw0_rd_out[470]
  PIN rw0_rd_out[471]
    DIRECTION OUTPUT ;
    USE SIGNAL ;
    SHAPE ABUTMENT ;
    PORT
      LAYER M3 ;
      RECT 0 275.555 0.07 275.625 ;
    END
  END rw0_rd_out[471]
  PIN rw0_rd_out[472]
    DIRECTION OUTPUT ;
    USE SIGNAL ;
    SHAPE ABUTMENT ;
    PORT
      LAYER M3 ;
      RECT 0 275.835 0.07 275.905 ;
    END
  END rw0_rd_out[472]
  PIN rw0_rd_out[473]
    DIRECTION OUTPUT ;
    USE SIGNAL ;
    SHAPE ABUTMENT ;
    PORT
      LAYER M3 ;
      RECT 0 276.115 0.07 276.185 ;
    END
  END rw0_rd_out[473]
  PIN rw0_rd_out[474]
    DIRECTION OUTPUT ;
    USE SIGNAL ;
    SHAPE ABUTMENT ;
    PORT
      LAYER M3 ;
      RECT 0 276.395 0.07 276.465 ;
    END
  END rw0_rd_out[474]
  PIN rw0_rd_out[475]
    DIRECTION OUTPUT ;
    USE SIGNAL ;
    SHAPE ABUTMENT ;
    PORT
      LAYER M3 ;
      RECT 0 276.675 0.07 276.745 ;
    END
  END rw0_rd_out[475]
  PIN rw0_rd_out[476]
    DIRECTION OUTPUT ;
    USE SIGNAL ;
    SHAPE ABUTMENT ;
    PORT
      LAYER M3 ;
      RECT 0 276.955 0.07 277.025 ;
    END
  END rw0_rd_out[476]
  PIN rw0_rd_out[477]
    DIRECTION OUTPUT ;
    USE SIGNAL ;
    SHAPE ABUTMENT ;
    PORT
      LAYER M3 ;
      RECT 0 277.235 0.07 277.305 ;
    END
  END rw0_rd_out[477]
  PIN rw0_rd_out[478]
    DIRECTION OUTPUT ;
    USE SIGNAL ;
    SHAPE ABUTMENT ;
    PORT
      LAYER M3 ;
      RECT 0 277.515 0.07 277.585 ;
    END
  END rw0_rd_out[478]
  PIN rw0_rd_out[479]
    DIRECTION OUTPUT ;
    USE SIGNAL ;
    SHAPE ABUTMENT ;
    PORT
      LAYER M3 ;
      RECT 0 277.795 0.07 277.865 ;
    END
  END rw0_rd_out[479]
  PIN rw0_rd_out[480]
    DIRECTION OUTPUT ;
    USE SIGNAL ;
    SHAPE ABUTMENT ;
    PORT
      LAYER M3 ;
      RECT 0 278.075 0.07 278.145 ;
    END
  END rw0_rd_out[480]
  PIN rw0_rd_out[481]
    DIRECTION OUTPUT ;
    USE SIGNAL ;
    SHAPE ABUTMENT ;
    PORT
      LAYER M3 ;
      RECT 0 278.355 0.07 278.425 ;
    END
  END rw0_rd_out[481]
  PIN rw0_rd_out[482]
    DIRECTION OUTPUT ;
    USE SIGNAL ;
    SHAPE ABUTMENT ;
    PORT
      LAYER M3 ;
      RECT 0 278.635 0.07 278.705 ;
    END
  END rw0_rd_out[482]
  PIN rw0_rd_out[483]
    DIRECTION OUTPUT ;
    USE SIGNAL ;
    SHAPE ABUTMENT ;
    PORT
      LAYER M3 ;
      RECT 0 278.915 0.07 278.985 ;
    END
  END rw0_rd_out[483]
  PIN rw0_rd_out[484]
    DIRECTION OUTPUT ;
    USE SIGNAL ;
    SHAPE ABUTMENT ;
    PORT
      LAYER M3 ;
      RECT 0 279.195 0.07 279.265 ;
    END
  END rw0_rd_out[484]
  PIN rw0_rd_out[485]
    DIRECTION OUTPUT ;
    USE SIGNAL ;
    SHAPE ABUTMENT ;
    PORT
      LAYER M3 ;
      RECT 0 279.475 0.07 279.545 ;
    END
  END rw0_rd_out[485]
  PIN rw0_rd_out[486]
    DIRECTION OUTPUT ;
    USE SIGNAL ;
    SHAPE ABUTMENT ;
    PORT
      LAYER M3 ;
      RECT 0 279.755 0.07 279.825 ;
    END
  END rw0_rd_out[486]
  PIN rw0_rd_out[487]
    DIRECTION OUTPUT ;
    USE SIGNAL ;
    SHAPE ABUTMENT ;
    PORT
      LAYER M3 ;
      RECT 0 280.035 0.07 280.105 ;
    END
  END rw0_rd_out[487]
  PIN rw0_rd_out[488]
    DIRECTION OUTPUT ;
    USE SIGNAL ;
    SHAPE ABUTMENT ;
    PORT
      LAYER M3 ;
      RECT 0 280.315 0.07 280.385 ;
    END
  END rw0_rd_out[488]
  PIN rw0_rd_out[489]
    DIRECTION OUTPUT ;
    USE SIGNAL ;
    SHAPE ABUTMENT ;
    PORT
      LAYER M3 ;
      RECT 0 280.595 0.07 280.665 ;
    END
  END rw0_rd_out[489]
  PIN rw0_rd_out[490]
    DIRECTION OUTPUT ;
    USE SIGNAL ;
    SHAPE ABUTMENT ;
    PORT
      LAYER M3 ;
      RECT 0 280.875 0.07 280.945 ;
    END
  END rw0_rd_out[490]
  PIN rw0_rd_out[491]
    DIRECTION OUTPUT ;
    USE SIGNAL ;
    SHAPE ABUTMENT ;
    PORT
      LAYER M3 ;
      RECT 0 281.155 0.07 281.225 ;
    END
  END rw0_rd_out[491]
  PIN rw0_rd_out[492]
    DIRECTION OUTPUT ;
    USE SIGNAL ;
    SHAPE ABUTMENT ;
    PORT
      LAYER M3 ;
      RECT 0 281.435 0.07 281.505 ;
    END
  END rw0_rd_out[492]
  PIN rw0_rd_out[493]
    DIRECTION OUTPUT ;
    USE SIGNAL ;
    SHAPE ABUTMENT ;
    PORT
      LAYER M3 ;
      RECT 0 281.715 0.07 281.785 ;
    END
  END rw0_rd_out[493]
  PIN rw0_rd_out[494]
    DIRECTION OUTPUT ;
    USE SIGNAL ;
    SHAPE ABUTMENT ;
    PORT
      LAYER M3 ;
      RECT 0 281.995 0.07 282.065 ;
    END
  END rw0_rd_out[494]
  PIN rw0_rd_out[495]
    DIRECTION OUTPUT ;
    USE SIGNAL ;
    SHAPE ABUTMENT ;
    PORT
      LAYER M3 ;
      RECT 0 282.275 0.07 282.345 ;
    END
  END rw0_rd_out[495]
  PIN rw0_rd_out[496]
    DIRECTION OUTPUT ;
    USE SIGNAL ;
    SHAPE ABUTMENT ;
    PORT
      LAYER M3 ;
      RECT 0 282.555 0.07 282.625 ;
    END
  END rw0_rd_out[496]
  PIN rw0_rd_out[497]
    DIRECTION OUTPUT ;
    USE SIGNAL ;
    SHAPE ABUTMENT ;
    PORT
      LAYER M3 ;
      RECT 0 282.835 0.07 282.905 ;
    END
  END rw0_rd_out[497]
  PIN rw0_rd_out[498]
    DIRECTION OUTPUT ;
    USE SIGNAL ;
    SHAPE ABUTMENT ;
    PORT
      LAYER M3 ;
      RECT 0 283.115 0.07 283.185 ;
    END
  END rw0_rd_out[498]
  PIN rw0_rd_out[499]
    DIRECTION OUTPUT ;
    USE SIGNAL ;
    SHAPE ABUTMENT ;
    PORT
      LAYER M3 ;
      RECT 0 283.395 0.07 283.465 ;
    END
  END rw0_rd_out[499]
  PIN rw0_rd_out[500]
    DIRECTION OUTPUT ;
    USE SIGNAL ;
    SHAPE ABUTMENT ;
    PORT
      LAYER M3 ;
      RECT 0 283.675 0.07 283.745 ;
    END
  END rw0_rd_out[500]
  PIN rw0_rd_out[501]
    DIRECTION OUTPUT ;
    USE SIGNAL ;
    SHAPE ABUTMENT ;
    PORT
      LAYER M3 ;
      RECT 0 283.955 0.07 284.025 ;
    END
  END rw0_rd_out[501]
  PIN rw0_rd_out[502]
    DIRECTION OUTPUT ;
    USE SIGNAL ;
    SHAPE ABUTMENT ;
    PORT
      LAYER M3 ;
      RECT 0 284.235 0.07 284.305 ;
    END
  END rw0_rd_out[502]
  PIN rw0_rd_out[503]
    DIRECTION OUTPUT ;
    USE SIGNAL ;
    SHAPE ABUTMENT ;
    PORT
      LAYER M3 ;
      RECT 0 284.515 0.07 284.585 ;
    END
  END rw0_rd_out[503]
  PIN rw0_rd_out[504]
    DIRECTION OUTPUT ;
    USE SIGNAL ;
    SHAPE ABUTMENT ;
    PORT
      LAYER M3 ;
      RECT 0 284.795 0.07 284.865 ;
    END
  END rw0_rd_out[504]
  PIN rw0_rd_out[505]
    DIRECTION OUTPUT ;
    USE SIGNAL ;
    SHAPE ABUTMENT ;
    PORT
      LAYER M3 ;
      RECT 0 285.075 0.07 285.145 ;
    END
  END rw0_rd_out[505]
  PIN rw0_rd_out[506]
    DIRECTION OUTPUT ;
    USE SIGNAL ;
    SHAPE ABUTMENT ;
    PORT
      LAYER M3 ;
      RECT 0 285.355 0.07 285.425 ;
    END
  END rw0_rd_out[506]
  PIN rw0_rd_out[507]
    DIRECTION OUTPUT ;
    USE SIGNAL ;
    SHAPE ABUTMENT ;
    PORT
      LAYER M3 ;
      RECT 0 285.635 0.07 285.705 ;
    END
  END rw0_rd_out[507]
  PIN rw0_rd_out[508]
    DIRECTION OUTPUT ;
    USE SIGNAL ;
    SHAPE ABUTMENT ;
    PORT
      LAYER M3 ;
      RECT 0 285.915 0.07 285.985 ;
    END
  END rw0_rd_out[508]
  PIN rw0_rd_out[509]
    DIRECTION OUTPUT ;
    USE SIGNAL ;
    SHAPE ABUTMENT ;
    PORT
      LAYER M3 ;
      RECT 0 286.195 0.07 286.265 ;
    END
  END rw0_rd_out[509]
  PIN rw0_rd_out[510]
    DIRECTION OUTPUT ;
    USE SIGNAL ;
    SHAPE ABUTMENT ;
    PORT
      LAYER M3 ;
      RECT 0 286.475 0.07 286.545 ;
    END
  END rw0_rd_out[510]
  PIN rw0_rd_out[511]
    DIRECTION OUTPUT ;
    USE SIGNAL ;
    SHAPE ABUTMENT ;
    PORT
      LAYER M3 ;
      RECT 0 286.755 0.07 286.825 ;
    END
  END rw0_rd_out[511]
  PIN rw0_addr_in[0]
    DIRECTION INPUT ;
    USE SIGNAL ;
    SHAPE ABUTMENT ;
    PORT
      LAYER M3 ;
      RECT 0 287.035 0.07 287.105 ;
    END
  END rw0_addr_in[0]
  PIN rw0_addr_in[1]
    DIRECTION INPUT ;
    USE SIGNAL ;
    SHAPE ABUTMENT ;
    PORT
      LAYER M3 ;
      RECT 0 287.315 0.07 287.385 ;
    END
  END rw0_addr_in[1]
  PIN rw0_addr_in[2]
    DIRECTION INPUT ;
    USE SIGNAL ;
    SHAPE ABUTMENT ;
    PORT
      LAYER M3 ;
      RECT 0 287.595 0.07 287.665 ;
    END
  END rw0_addr_in[2]
  PIN rw0_addr_in[3]
    DIRECTION INPUT ;
    USE SIGNAL ;
    SHAPE ABUTMENT ;
    PORT
      LAYER M3 ;
      RECT 0 287.875 0.07 287.945 ;
    END
  END rw0_addr_in[3]
  PIN rw0_addr_in[4]
    DIRECTION INPUT ;
    USE SIGNAL ;
    SHAPE ABUTMENT ;
    PORT
      LAYER M3 ;
      RECT 0 288.155 0.07 288.225 ;
    END
  END rw0_addr_in[4]
  PIN rw0_addr_in[5]
    DIRECTION INPUT ;
    USE SIGNAL ;
    SHAPE ABUTMENT ;
    PORT
      LAYER M3 ;
      RECT 0 288.435 0.07 288.505 ;
    END
  END rw0_addr_in[5]
  PIN rw0_we_in
    DIRECTION INPUT ;
    USE SIGNAL ;
    SHAPE ABUTMENT ;
    PORT
      LAYER M3 ;
      RECT 0 288.715 0.07 288.785 ;
    END
  END rw0_we_in
  PIN rw0_ce_in
    DIRECTION INPUT ;
    USE SIGNAL ;
    SHAPE ABUTMENT ;
    PORT
      LAYER M3 ;
      RECT 0 288.995 0.07 289.065 ;
    END
  END rw0_ce_in
  PIN rw0_clk
    DIRECTION INPUT ;
    USE SIGNAL ;
    SHAPE ABUTMENT ;
    PORT
      LAYER M3 ;
      RECT 0 289.275 0.07 289.345 ;
    END
  END rw0_clk
  PIN VSS
    DIRECTION INOUT ;
    USE GROUND ;
    PORT
      LAYER M4 ;
      RECT 1 0.84 1.28 332.36 ;
      RECT 3.24 0.84 3.52 332.36 ;
      RECT 5.48 0.84 5.76 332.36 ;
      RECT 7.72 0.84 8 332.36 ;
      RECT 9.96 0.84 10.24 332.36 ;
      RECT 12.2 0.84 12.48 332.36 ;
      RECT 14.44 0.84 14.72 332.36 ;
      RECT 16.68 0.84 16.96 332.36 ;
      RECT 18.92 0.84 19.2 332.36 ;
      RECT 21.16 0.84 21.44 332.36 ;
      RECT 23.4 0.84 23.68 332.36 ;
      RECT 25.64 0.84 25.92 332.36 ;
      RECT 27.88 0.84 28.16 332.36 ;
      RECT 30.12 0.84 30.4 332.36 ;
      RECT 32.36 0.84 32.64 332.36 ;
      RECT 34.6 0.84 34.88 332.36 ;
      RECT 36.84 0.84 37.12 332.36 ;
      RECT 39.08 0.84 39.36 332.36 ;
      RECT 41.32 0.84 41.6 332.36 ;
      RECT 43.56 0.84 43.84 332.36 ;
      RECT 45.8 0.84 46.08 332.36 ;
      RECT 48.04 0.84 48.32 332.36 ;
      RECT 50.28 0.84 50.56 332.36 ;
      RECT 52.52 0.84 52.8 332.36 ;
      RECT 54.76 0.84 55.04 332.36 ;
      RECT 57 0.84 57.28 332.36 ;
      RECT 59.24 0.84 59.52 332.36 ;
      RECT 61.48 0.84 61.76 332.36 ;
      RECT 63.72 0.84 64 332.36 ;
      RECT 65.96 0.84 66.24 332.36 ;
      RECT 68.2 0.84 68.48 332.36 ;
      RECT 70.44 0.84 70.72 332.36 ;
      RECT 72.68 0.84 72.96 332.36 ;
      RECT 74.92 0.84 75.2 332.36 ;
      RECT 77.16 0.84 77.44 332.36 ;
      RECT 79.4 0.84 79.68 332.36 ;
      RECT 81.64 0.84 81.92 332.36 ;
      RECT 83.88 0.84 84.16 332.36 ;
      RECT 86.12 0.84 86.4 332.36 ;
      RECT 88.36 0.84 88.64 332.36 ;
      RECT 90.6 0.84 90.88 332.36 ;
      RECT 92.84 0.84 93.12 332.36 ;
      RECT 95.08 0.84 95.36 332.36 ;
      RECT 97.32 0.84 97.6 332.36 ;
      RECT 99.56 0.84 99.84 332.36 ;
      RECT 101.8 0.84 102.08 332.36 ;
      RECT 104.04 0.84 104.32 332.36 ;
      RECT 106.28 0.84 106.56 332.36 ;
      RECT 108.52 0.84 108.8 332.36 ;
      RECT 110.76 0.84 111.04 332.36 ;
      RECT 113 0.84 113.28 332.36 ;
      RECT 115.24 0.84 115.52 332.36 ;
      RECT 117.48 0.84 117.76 332.36 ;
      RECT 119.72 0.84 120 332.36 ;
      RECT 121.96 0.84 122.24 332.36 ;
      RECT 124.2 0.84 124.48 332.36 ;
      RECT 126.44 0.84 126.72 332.36 ;
      RECT 128.68 0.84 128.96 332.36 ;
      RECT 130.92 0.84 131.2 332.36 ;
      RECT 133.16 0.84 133.44 332.36 ;
      RECT 135.4 0.84 135.68 332.36 ;
      RECT 137.64 0.84 137.92 332.36 ;
      RECT 139.88 0.84 140.16 332.36 ;
      RECT 142.12 0.84 142.4 332.36 ;
      RECT 144.36 0.84 144.64 332.36 ;
      RECT 146.6 0.84 146.88 332.36 ;
      RECT 148.84 0.84 149.12 332.36 ;
      RECT 151.08 0.84 151.36 332.36 ;
      RECT 153.32 0.84 153.6 332.36 ;
      RECT 155.56 0.84 155.84 332.36 ;
      RECT 157.8 0.84 158.08 332.36 ;
      RECT 160.04 0.84 160.32 332.36 ;
      RECT 162.28 0.84 162.56 332.36 ;
      RECT 164.52 0.84 164.8 332.36 ;
    END
  END VSS
  PIN VDD
    DIRECTION INOUT ;
    USE POWER ;
    PORT
      LAYER M4 ;
      RECT 2.12 0.84 2.4 332.36 ;
      RECT 4.36 0.84 4.64 332.36 ;
      RECT 6.6 0.84 6.88 332.36 ;
      RECT 8.84 0.84 9.12 332.36 ;
      RECT 11.08 0.84 11.36 332.36 ;
      RECT 13.32 0.84 13.6 332.36 ;
      RECT 15.56 0.84 15.84 332.36 ;
      RECT 17.8 0.84 18.08 332.36 ;
      RECT 20.04 0.84 20.32 332.36 ;
      RECT 22.28 0.84 22.56 332.36 ;
      RECT 24.52 0.84 24.8 332.36 ;
      RECT 26.76 0.84 27.04 332.36 ;
      RECT 29 0.84 29.28 332.36 ;
      RECT 31.24 0.84 31.52 332.36 ;
      RECT 33.48 0.84 33.76 332.36 ;
      RECT 35.72 0.84 36 332.36 ;
      RECT 37.96 0.84 38.24 332.36 ;
      RECT 40.2 0.84 40.48 332.36 ;
      RECT 42.44 0.84 42.72 332.36 ;
      RECT 44.68 0.84 44.96 332.36 ;
      RECT 46.92 0.84 47.2 332.36 ;
      RECT 49.16 0.84 49.44 332.36 ;
      RECT 51.4 0.84 51.68 332.36 ;
      RECT 53.64 0.84 53.92 332.36 ;
      RECT 55.88 0.84 56.16 332.36 ;
      RECT 58.12 0.84 58.4 332.36 ;
      RECT 60.36 0.84 60.64 332.36 ;
      RECT 62.6 0.84 62.88 332.36 ;
      RECT 64.84 0.84 65.12 332.36 ;
      RECT 67.08 0.84 67.36 332.36 ;
      RECT 69.32 0.84 69.6 332.36 ;
      RECT 71.56 0.84 71.84 332.36 ;
      RECT 73.8 0.84 74.08 332.36 ;
      RECT 76.04 0.84 76.32 332.36 ;
      RECT 78.28 0.84 78.56 332.36 ;
      RECT 80.52 0.84 80.8 332.36 ;
      RECT 82.76 0.84 83.04 332.36 ;
      RECT 85 0.84 85.28 332.36 ;
      RECT 87.24 0.84 87.52 332.36 ;
      RECT 89.48 0.84 89.76 332.36 ;
      RECT 91.72 0.84 92 332.36 ;
      RECT 93.96 0.84 94.24 332.36 ;
      RECT 96.2 0.84 96.48 332.36 ;
      RECT 98.44 0.84 98.72 332.36 ;
      RECT 100.68 0.84 100.96 332.36 ;
      RECT 102.92 0.84 103.2 332.36 ;
      RECT 105.16 0.84 105.44 332.36 ;
      RECT 107.4 0.84 107.68 332.36 ;
      RECT 109.64 0.84 109.92 332.36 ;
      RECT 111.88 0.84 112.16 332.36 ;
      RECT 114.12 0.84 114.4 332.36 ;
      RECT 116.36 0.84 116.64 332.36 ;
      RECT 118.6 0.84 118.88 332.36 ;
      RECT 120.84 0.84 121.12 332.36 ;
      RECT 123.08 0.84 123.36 332.36 ;
      RECT 125.32 0.84 125.6 332.36 ;
      RECT 127.56 0.84 127.84 332.36 ;
      RECT 129.8 0.84 130.08 332.36 ;
      RECT 132.04 0.84 132.32 332.36 ;
      RECT 134.28 0.84 134.56 332.36 ;
      RECT 136.52 0.84 136.8 332.36 ;
      RECT 138.76 0.84 139.04 332.36 ;
      RECT 141 0.84 141.28 332.36 ;
      RECT 143.24 0.84 143.52 332.36 ;
      RECT 145.48 0.84 145.76 332.36 ;
      RECT 147.72 0.84 148 332.36 ;
      RECT 149.96 0.84 150.24 332.36 ;
      RECT 152.2 0.84 152.48 332.36 ;
      RECT 154.44 0.84 154.72 332.36 ;
      RECT 156.68 0.84 156.96 332.36 ;
      RECT 158.92 0.84 159.2 332.36 ;
      RECT 161.16 0.84 161.44 332.36 ;
      RECT 163.4 0.84 163.68 332.36 ;
    END
  END VDD
  OBS
    LAYER M1 ;
    RECT 0 0 165.87 333.2 ;
    LAYER M2 ;
    RECT 0 0 165.87 333.2 ;
  END
END ht45_mempoolgroup_512x64

END LIBRARY
